VERSION 5.8 ;
BUSBITCHARS "[]" ;
DIVIDERCHAR "/" ;
UNITS
    DATABASE MICRONS 1000 ;
END UNITS

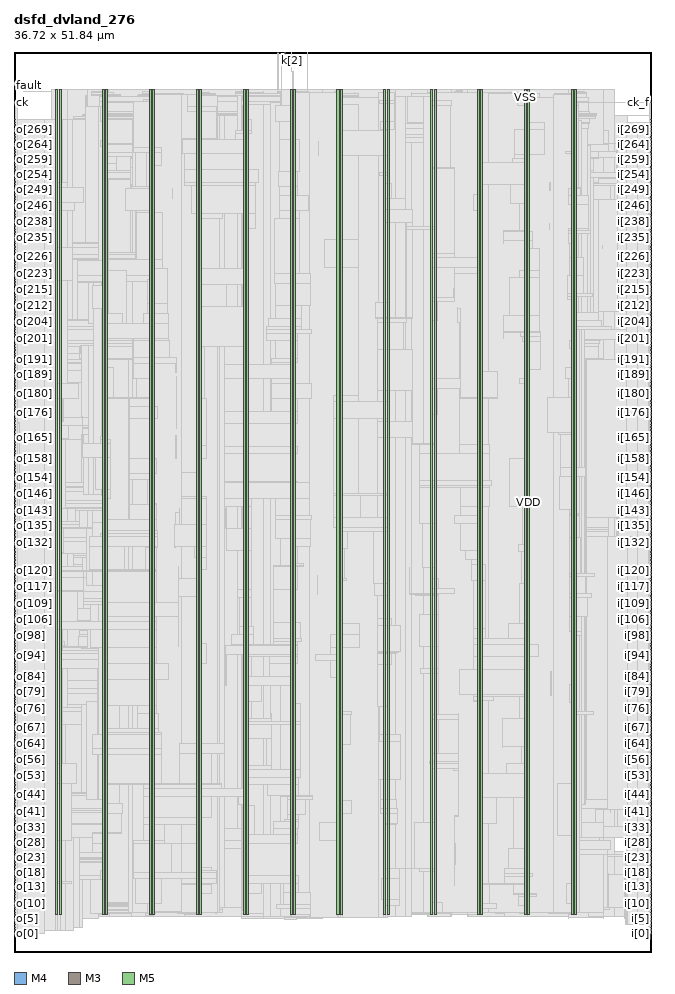
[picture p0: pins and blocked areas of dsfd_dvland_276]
MACRO dsfd_dvland_276
  FOREIGN dsfd_dvland_276 0 0 ;
  CLASS BLOCK ;
  SIZE 36.72 BY 51.84 ;
  PIN ck
    DIRECTION INPUT ;
    USE SIGNAL ;
    PORT
      LAYER M4 ;
        RECT  0 48.912 0.084 48.936 ;
    END
  END ck
  PIN ck_f
    DIRECTION INPUT ;
    USE SIGNAL ;
    PORT
      LAYER M4 ;
        RECT  36.636 48.912 36.72 48.936 ;
    END
  END ck_f
  PIN fault
    DIRECTION OUTPUT ;
    USE SIGNAL ;
    PORT
      LAYER M4 ;
        RECT  0 49.92 0.084 49.944 ;
    END
  END fault
  PIN i[0]
    DIRECTION INPUT ;
    USE SIGNAL ;
    PORT
      LAYER M4 ;
        RECT  36.636 1.056 36.72 1.08 ;
    END
  END i[0]
  PIN i[100]
    DIRECTION INPUT ;
    USE SIGNAL ;
    PORT
      LAYER M4 ;
        RECT  36.636 18.096 36.72 18.12 ;
    END
  END i[100]
  PIN i[101]
    DIRECTION INPUT ;
    USE SIGNAL ;
    PORT
      LAYER M4 ;
        RECT  36.636 18.288 36.72 18.312 ;
    END
  END i[101]
  PIN i[102]
    DIRECTION INPUT ;
    USE SIGNAL ;
    PORT
      LAYER M4 ;
        RECT  36.636 18.48 36.72 18.504 ;
    END
  END i[102]
  PIN i[103]
    DIRECTION INPUT ;
    USE SIGNAL ;
    PORT
      LAYER M4 ;
        RECT  36.636 18.624 36.72 18.648 ;
    END
  END i[103]
  PIN i[104]
    DIRECTION INPUT ;
    USE SIGNAL ;
    PORT
      LAYER M4 ;
        RECT  36.636 18.816 36.72 18.84 ;
    END
  END i[104]
  PIN i[105]
    DIRECTION INPUT ;
    USE SIGNAL ;
    PORT
      LAYER M4 ;
        RECT  36.636 18.96 36.72 18.984 ;
    END
  END i[105]
  PIN i[106]
    DIRECTION INPUT ;
    USE SIGNAL ;
    PORT
      LAYER M4 ;
        RECT  36.636 19.152 36.72 19.176 ;
    END
  END i[106]
  PIN i[107]
    DIRECTION INPUT ;
    USE SIGNAL ;
    PORT
      LAYER M4 ;
        RECT  36.636 19.296 36.72 19.32 ;
    END
  END i[107]
  PIN i[108]
    DIRECTION INPUT ;
    USE SIGNAL ;
    PORT
      LAYER M4 ;
        RECT  36.636 19.488 36.72 19.512 ;
    END
  END i[108]
  PIN i[109]
    DIRECTION INPUT ;
    USE SIGNAL ;
    PORT
      LAYER M4 ;
        RECT  36.636 19.632 36.72 19.656 ;
    END
  END i[109]
  PIN i[10]
    DIRECTION INPUT ;
    USE SIGNAL ;
    PORT
      LAYER M4 ;
        RECT  36.636 2.784 36.72 2.808 ;
    END
  END i[10]
  PIN i[110]
    DIRECTION INPUT ;
    USE SIGNAL ;
    PORT
      LAYER M4 ;
        RECT  36.636 19.824 36.72 19.848 ;
    END
  END i[110]
  PIN i[111]
    DIRECTION INPUT ;
    USE SIGNAL ;
    PORT
      LAYER M4 ;
        RECT  36.636 19.968 36.72 19.992 ;
    END
  END i[111]
  PIN i[112]
    DIRECTION INPUT ;
    USE SIGNAL ;
    PORT
      LAYER M4 ;
        RECT  36.636 20.16 36.72 20.184 ;
    END
  END i[112]
  PIN i[113]
    DIRECTION INPUT ;
    USE SIGNAL ;
    PORT
      LAYER M4 ;
        RECT  36.636 20.352 36.72 20.376 ;
    END
  END i[113]
  PIN i[114]
    DIRECTION INPUT ;
    USE SIGNAL ;
    PORT
      LAYER M4 ;
        RECT  36.636 20.496 36.72 20.52 ;
    END
  END i[114]
  PIN i[115]
    DIRECTION INPUT ;
    USE SIGNAL ;
    PORT
      LAYER M4 ;
        RECT  36.636 20.688 36.72 20.712 ;
    END
  END i[115]
  PIN i[116]
    DIRECTION INPUT ;
    USE SIGNAL ;
    PORT
      LAYER M4 ;
        RECT  36.636 20.832 36.72 20.856 ;
    END
  END i[116]
  PIN i[117]
    DIRECTION INPUT ;
    USE SIGNAL ;
    PORT
      LAYER M4 ;
        RECT  36.636 21.024 36.72 21.048 ;
    END
  END i[117]
  PIN i[118]
    DIRECTION INPUT ;
    USE SIGNAL ;
    PORT
      LAYER M4 ;
        RECT  36.636 21.168 36.72 21.192 ;
    END
  END i[118]
  PIN i[119]
    DIRECTION INPUT ;
    USE SIGNAL ;
    PORT
      LAYER M4 ;
        RECT  36.636 21.36 36.72 21.384 ;
    END
  END i[119]
  PIN i[11]
    DIRECTION INPUT ;
    USE SIGNAL ;
    PORT
      LAYER M4 ;
        RECT  36.636 2.928 36.72 2.952 ;
    END
  END i[11]
  PIN i[120]
    DIRECTION INPUT ;
    USE SIGNAL ;
    PORT
      LAYER M4 ;
        RECT  36.636 21.504 36.72 21.528 ;
    END
  END i[120]
  PIN i[121]
    DIRECTION INPUT ;
    USE SIGNAL ;
    PORT
      LAYER M4 ;
        RECT  36.636 21.696 36.72 21.72 ;
    END
  END i[121]
  PIN i[122]
    DIRECTION INPUT ;
    USE SIGNAL ;
    PORT
      LAYER M4 ;
        RECT  36.636 21.888 36.72 21.912 ;
    END
  END i[122]
  PIN i[123]
    DIRECTION INPUT ;
    USE SIGNAL ;
    PORT
      LAYER M4 ;
        RECT  36.636 22.032 36.72 22.056 ;
    END
  END i[123]
  PIN i[124]
    DIRECTION INPUT ;
    USE SIGNAL ;
    PORT
      LAYER M4 ;
        RECT  36.636 22.224 36.72 22.248 ;
    END
  END i[124]
  PIN i[125]
    DIRECTION INPUT ;
    USE SIGNAL ;
    PORT
      LAYER M4 ;
        RECT  36.636 22.368 36.72 22.392 ;
    END
  END i[125]
  PIN i[126]
    DIRECTION INPUT ;
    USE SIGNAL ;
    PORT
      LAYER M4 ;
        RECT  36.636 22.56 36.72 22.584 ;
    END
  END i[126]
  PIN i[127]
    DIRECTION INPUT ;
    USE SIGNAL ;
    PORT
      LAYER M4 ;
        RECT  36.636 22.704 36.72 22.728 ;
    END
  END i[127]
  PIN i[128]
    DIRECTION INPUT ;
    USE SIGNAL ;
    PORT
      LAYER M4 ;
        RECT  36.636 22.896 36.72 22.92 ;
    END
  END i[128]
  PIN i[129]
    DIRECTION INPUT ;
    USE SIGNAL ;
    PORT
      LAYER M4 ;
        RECT  36.636 23.04 36.72 23.064 ;
    END
  END i[129]
  PIN i[12]
    DIRECTION INPUT ;
    USE SIGNAL ;
    PORT
      LAYER M4 ;
        RECT  36.636 3.12 36.72 3.144 ;
    END
  END i[12]
  PIN i[130]
    DIRECTION INPUT ;
    USE SIGNAL ;
    PORT
      LAYER M4 ;
        RECT  36.636 23.232 36.72 23.256 ;
    END
  END i[130]
  PIN i[131]
    DIRECTION INPUT ;
    USE SIGNAL ;
    PORT
      LAYER M4 ;
        RECT  36.636 23.424 36.72 23.448 ;
    END
  END i[131]
  PIN i[132]
    DIRECTION INPUT ;
    USE SIGNAL ;
    PORT
      LAYER M4 ;
        RECT  36.636 23.568 36.72 23.592 ;
    END
  END i[132]
  PIN i[133]
    DIRECTION INPUT ;
    USE SIGNAL ;
    PORT
      LAYER M4 ;
        RECT  36.636 23.76 36.72 23.784 ;
    END
  END i[133]
  PIN i[134]
    DIRECTION INPUT ;
    USE SIGNAL ;
    PORT
      LAYER M4 ;
        RECT  36.636 23.904 36.72 23.928 ;
    END
  END i[134]
  PIN i[135]
    DIRECTION INPUT ;
    USE SIGNAL ;
    PORT
      LAYER M4 ;
        RECT  36.636 24.096 36.72 24.12 ;
    END
  END i[135]
  PIN i[136]
    DIRECTION INPUT ;
    USE SIGNAL ;
    PORT
      LAYER M4 ;
        RECT  36.636 24.24 36.72 24.264 ;
    END
  END i[136]
  PIN i[137]
    DIRECTION INPUT ;
    USE SIGNAL ;
    PORT
      LAYER M4 ;
        RECT  36.636 24.432 36.72 24.456 ;
    END
  END i[137]
  PIN i[138]
    DIRECTION INPUT ;
    USE SIGNAL ;
    PORT
      LAYER M4 ;
        RECT  36.636 24.576 36.72 24.6 ;
    END
  END i[138]
  PIN i[139]
    DIRECTION INPUT ;
    USE SIGNAL ;
    PORT
      LAYER M4 ;
        RECT  36.636 24.768 36.72 24.792 ;
    END
  END i[139]
  PIN i[13]
    DIRECTION INPUT ;
    USE SIGNAL ;
    PORT
      LAYER M4 ;
        RECT  36.636 3.312 36.72 3.336 ;
    END
  END i[13]
  PIN i[140]
    DIRECTION INPUT ;
    USE SIGNAL ;
    PORT
      LAYER M4 ;
        RECT  36.636 24.912 36.72 24.936 ;
    END
  END i[140]
  PIN i[141]
    DIRECTION INPUT ;
    USE SIGNAL ;
    PORT
      LAYER M4 ;
        RECT  36.636 25.104 36.72 25.128 ;
    END
  END i[141]
  PIN i[142]
    DIRECTION INPUT ;
    USE SIGNAL ;
    PORT
      LAYER M4 ;
        RECT  36.636 25.296 36.72 25.32 ;
    END
  END i[142]
  PIN i[143]
    DIRECTION INPUT ;
    USE SIGNAL ;
    PORT
      LAYER M4 ;
        RECT  36.636 25.44 36.72 25.464 ;
    END
  END i[143]
  PIN i[144]
    DIRECTION INPUT ;
    USE SIGNAL ;
    PORT
      LAYER M4 ;
        RECT  36.636 25.632 36.72 25.656 ;
    END
  END i[144]
  PIN i[145]
    DIRECTION INPUT ;
    USE SIGNAL ;
    PORT
      LAYER M4 ;
        RECT  36.636 25.776 36.72 25.8 ;
    END
  END i[145]
  PIN i[146]
    DIRECTION INPUT ;
    USE SIGNAL ;
    PORT
      LAYER M4 ;
        RECT  36.636 25.968 36.72 25.992 ;
    END
  END i[146]
  PIN i[147]
    DIRECTION INPUT ;
    USE SIGNAL ;
    PORT
      LAYER M4 ;
        RECT  36.636 26.112 36.72 26.136 ;
    END
  END i[147]
  PIN i[148]
    DIRECTION INPUT ;
    USE SIGNAL ;
    PORT
      LAYER M4 ;
        RECT  36.636 26.304 36.72 26.328 ;
    END
  END i[148]
  PIN i[149]
    DIRECTION INPUT ;
    USE SIGNAL ;
    PORT
      LAYER M4 ;
        RECT  36.636 26.448 36.72 26.472 ;
    END
  END i[149]
  PIN i[14]
    DIRECTION INPUT ;
    USE SIGNAL ;
    PORT
      LAYER M4 ;
        RECT  36.636 3.456 36.72 3.48 ;
    END
  END i[14]
  PIN i[150]
    DIRECTION INPUT ;
    USE SIGNAL ;
    PORT
      LAYER M4 ;
        RECT  36.636 26.64 36.72 26.664 ;
    END
  END i[150]
  PIN i[151]
    DIRECTION INPUT ;
    USE SIGNAL ;
    PORT
      LAYER M4 ;
        RECT  36.636 26.832 36.72 26.856 ;
    END
  END i[151]
  PIN i[152]
    DIRECTION INPUT ;
    USE SIGNAL ;
    PORT
      LAYER M4 ;
        RECT  36.636 26.976 36.72 27 ;
    END
  END i[152]
  PIN i[153]
    DIRECTION INPUT ;
    USE SIGNAL ;
    PORT
      LAYER M4 ;
        RECT  36.636 27.168 36.72 27.192 ;
    END
  END i[153]
  PIN i[154]
    DIRECTION INPUT ;
    USE SIGNAL ;
    PORT
      LAYER M4 ;
        RECT  36.636 27.312 36.72 27.336 ;
    END
  END i[154]
  PIN i[155]
    DIRECTION INPUT ;
    USE SIGNAL ;
    PORT
      LAYER M4 ;
        RECT  36.636 27.504 36.72 27.528 ;
    END
  END i[155]
  PIN i[156]
    DIRECTION INPUT ;
    USE SIGNAL ;
    PORT
      LAYER M4 ;
        RECT  36.636 27.648 36.72 27.672 ;
    END
  END i[156]
  PIN i[157]
    DIRECTION INPUT ;
    USE SIGNAL ;
    PORT
      LAYER M4 ;
        RECT  36.636 27.84 36.72 27.864 ;
    END
  END i[157]
  PIN i[158]
    DIRECTION INPUT ;
    USE SIGNAL ;
    PORT
      LAYER M4 ;
        RECT  36.636 27.984 36.72 28.008 ;
    END
  END i[158]
  PIN i[159]
    DIRECTION INPUT ;
    USE SIGNAL ;
    PORT
      LAYER M4 ;
        RECT  36.636 28.176 36.72 28.2 ;
    END
  END i[159]
  PIN i[15]
    DIRECTION INPUT ;
    USE SIGNAL ;
    PORT
      LAYER M4 ;
        RECT  36.636 3.648 36.72 3.672 ;
    END
  END i[15]
  PIN i[160]
    DIRECTION INPUT ;
    USE SIGNAL ;
    PORT
      LAYER M4 ;
        RECT  36.636 28.32 36.72 28.344 ;
    END
  END i[160]
  PIN i[161]
    DIRECTION INPUT ;
    USE SIGNAL ;
    PORT
      LAYER M4 ;
        RECT  36.636 28.512 36.72 28.536 ;
    END
  END i[161]
  PIN i[162]
    DIRECTION INPUT ;
    USE SIGNAL ;
    PORT
      LAYER M4 ;
        RECT  36.636 28.704 36.72 28.728 ;
    END
  END i[162]
  PIN i[163]
    DIRECTION INPUT ;
    USE SIGNAL ;
    PORT
      LAYER M4 ;
        RECT  36.636 28.848 36.72 28.872 ;
    END
  END i[163]
  PIN i[164]
    DIRECTION INPUT ;
    USE SIGNAL ;
    PORT
      LAYER M4 ;
        RECT  36.636 29.04 36.72 29.064 ;
    END
  END i[164]
  PIN i[165]
    DIRECTION INPUT ;
    USE SIGNAL ;
    PORT
      LAYER M4 ;
        RECT  36.636 29.184 36.72 29.208 ;
    END
  END i[165]
  PIN i[166]
    DIRECTION INPUT ;
    USE SIGNAL ;
    PORT
      LAYER M4 ;
        RECT  36.636 29.376 36.72 29.4 ;
    END
  END i[166]
  PIN i[167]
    DIRECTION INPUT ;
    USE SIGNAL ;
    PORT
      LAYER M4 ;
        RECT  36.636 29.52 36.72 29.544 ;
    END
  END i[167]
  PIN i[168]
    DIRECTION INPUT ;
    USE SIGNAL ;
    PORT
      LAYER M4 ;
        RECT  36.636 29.712 36.72 29.736 ;
    END
  END i[168]
  PIN i[169]
    DIRECTION INPUT ;
    USE SIGNAL ;
    PORT
      LAYER M4 ;
        RECT  36.636 29.856 36.72 29.88 ;
    END
  END i[169]
  PIN i[16]
    DIRECTION INPUT ;
    USE SIGNAL ;
    PORT
      LAYER M4 ;
        RECT  36.636 3.792 36.72 3.816 ;
    END
  END i[16]
  PIN i[170]
    DIRECTION INPUT ;
    USE SIGNAL ;
    PORT
      LAYER M4 ;
        RECT  36.636 30.048 36.72 30.072 ;
    END
  END i[170]
  PIN i[171]
    DIRECTION INPUT ;
    USE SIGNAL ;
    PORT
      LAYER M4 ;
        RECT  36.636 30.24 36.72 30.264 ;
    END
  END i[171]
  PIN i[172]
    DIRECTION INPUT ;
    USE SIGNAL ;
    PORT
      LAYER M4 ;
        RECT  36.636 30.384 36.72 30.408 ;
    END
  END i[172]
  PIN i[173]
    DIRECTION INPUT ;
    USE SIGNAL ;
    PORT
      LAYER M4 ;
        RECT  36.636 30.576 36.72 30.6 ;
    END
  END i[173]
  PIN i[174]
    DIRECTION INPUT ;
    USE SIGNAL ;
    PORT
      LAYER M4 ;
        RECT  36.636 30.72 36.72 30.744 ;
    END
  END i[174]
  PIN i[175]
    DIRECTION INPUT ;
    USE SIGNAL ;
    PORT
      LAYER M4 ;
        RECT  36.636 30.912 36.72 30.936 ;
    END
  END i[175]
  PIN i[176]
    DIRECTION INPUT ;
    USE SIGNAL ;
    PORT
      LAYER M4 ;
        RECT  36.636 31.056 36.72 31.08 ;
    END
  END i[176]
  PIN i[177]
    DIRECTION INPUT ;
    USE SIGNAL ;
    PORT
      LAYER M4 ;
        RECT  36.636 31.248 36.72 31.272 ;
    END
  END i[177]
  PIN i[178]
    DIRECTION INPUT ;
    USE SIGNAL ;
    PORT
      LAYER M4 ;
        RECT  36.636 31.392 36.72 31.416 ;
    END
  END i[178]
  PIN i[179]
    DIRECTION INPUT ;
    USE SIGNAL ;
    PORT
      LAYER M4 ;
        RECT  36.636 31.584 36.72 31.608 ;
    END
  END i[179]
  PIN i[17]
    DIRECTION INPUT ;
    USE SIGNAL ;
    PORT
      LAYER M4 ;
        RECT  36.636 3.984 36.72 4.008 ;
    END
  END i[17]
  PIN i[180]
    DIRECTION INPUT ;
    USE SIGNAL ;
    PORT
      LAYER M4 ;
        RECT  36.636 31.728 36.72 31.752 ;
    END
  END i[180]
  PIN i[181]
    DIRECTION INPUT ;
    USE SIGNAL ;
    PORT
      LAYER M4 ;
        RECT  36.636 31.92 36.72 31.944 ;
    END
  END i[181]
  PIN i[182]
    DIRECTION INPUT ;
    USE SIGNAL ;
    PORT
      LAYER M4 ;
        RECT  36.636 32.112 36.72 32.136 ;
    END
  END i[182]
  PIN i[183]
    DIRECTION INPUT ;
    USE SIGNAL ;
    PORT
      LAYER M4 ;
        RECT  36.636 32.256 36.72 32.28 ;
    END
  END i[183]
  PIN i[184]
    DIRECTION INPUT ;
    USE SIGNAL ;
    PORT
      LAYER M4 ;
        RECT  36.636 32.448 36.72 32.472 ;
    END
  END i[184]
  PIN i[185]
    DIRECTION INPUT ;
    USE SIGNAL ;
    PORT
      LAYER M4 ;
        RECT  36.636 32.592 36.72 32.616 ;
    END
  END i[185]
  PIN i[186]
    DIRECTION INPUT ;
    USE SIGNAL ;
    PORT
      LAYER M4 ;
        RECT  36.636 32.784 36.72 32.808 ;
    END
  END i[186]
  PIN i[187]
    DIRECTION INPUT ;
    USE SIGNAL ;
    PORT
      LAYER M4 ;
        RECT  36.636 32.928 36.72 32.952 ;
    END
  END i[187]
  PIN i[188]
    DIRECTION INPUT ;
    USE SIGNAL ;
    PORT
      LAYER M4 ;
        RECT  36.636 33.12 36.72 33.144 ;
    END
  END i[188]
  PIN i[189]
    DIRECTION INPUT ;
    USE SIGNAL ;
    PORT
      LAYER M4 ;
        RECT  36.636 33.264 36.72 33.288 ;
    END
  END i[189]
  PIN i[18]
    DIRECTION INPUT ;
    USE SIGNAL ;
    PORT
      LAYER M4 ;
        RECT  36.636 4.128 36.72 4.152 ;
    END
  END i[18]
  PIN i[190]
    DIRECTION INPUT ;
    USE SIGNAL ;
    PORT
      LAYER M4 ;
        RECT  36.636 33.456 36.72 33.48 ;
    END
  END i[190]
  PIN i[191]
    DIRECTION INPUT ;
    USE SIGNAL ;
    PORT
      LAYER M4 ;
        RECT  36.636 33.648 36.72 33.672 ;
    END
  END i[191]
  PIN i[192]
    DIRECTION INPUT ;
    USE SIGNAL ;
    PORT
      LAYER M4 ;
        RECT  36.636 33.792 36.72 33.816 ;
    END
  END i[192]
  PIN i[193]
    DIRECTION INPUT ;
    USE SIGNAL ;
    PORT
      LAYER M4 ;
        RECT  36.636 33.984 36.72 34.008 ;
    END
  END i[193]
  PIN i[194]
    DIRECTION INPUT ;
    USE SIGNAL ;
    PORT
      LAYER M4 ;
        RECT  36.636 34.128 36.72 34.152 ;
    END
  END i[194]
  PIN i[195]
    DIRECTION INPUT ;
    USE SIGNAL ;
    PORT
      LAYER M4 ;
        RECT  36.636 34.32 36.72 34.344 ;
    END
  END i[195]
  PIN i[196]
    DIRECTION INPUT ;
    USE SIGNAL ;
    PORT
      LAYER M4 ;
        RECT  36.636 34.464 36.72 34.488 ;
    END
  END i[196]
  PIN i[197]
    DIRECTION INPUT ;
    USE SIGNAL ;
    PORT
      LAYER M4 ;
        RECT  36.636 34.656 36.72 34.68 ;
    END
  END i[197]
  PIN i[198]
    DIRECTION INPUT ;
    USE SIGNAL ;
    PORT
      LAYER M4 ;
        RECT  36.636 34.8 36.72 34.824 ;
    END
  END i[198]
  PIN i[199]
    DIRECTION INPUT ;
    USE SIGNAL ;
    PORT
      LAYER M4 ;
        RECT  36.636 34.992 36.72 35.016 ;
    END
  END i[199]
  PIN i[19]
    DIRECTION INPUT ;
    USE SIGNAL ;
    PORT
      LAYER M4 ;
        RECT  36.636 4.32 36.72 4.344 ;
    END
  END i[19]
  PIN i[1]
    DIRECTION INPUT ;
    USE SIGNAL ;
    PORT
      LAYER M4 ;
        RECT  36.636 1.248 36.72 1.272 ;
    END
  END i[1]
  PIN i[200]
    DIRECTION INPUT ;
    USE SIGNAL ;
    PORT
      LAYER M4 ;
        RECT  36.636 35.184 36.72 35.208 ;
    END
  END i[200]
  PIN i[201]
    DIRECTION INPUT ;
    USE SIGNAL ;
    PORT
      LAYER M4 ;
        RECT  36.636 35.328 36.72 35.352 ;
    END
  END i[201]
  PIN i[202]
    DIRECTION INPUT ;
    USE SIGNAL ;
    PORT
      LAYER M4 ;
        RECT  36.636 35.52 36.72 35.544 ;
    END
  END i[202]
  PIN i[203]
    DIRECTION INPUT ;
    USE SIGNAL ;
    PORT
      LAYER M4 ;
        RECT  36.636 35.664 36.72 35.688 ;
    END
  END i[203]
  PIN i[204]
    DIRECTION INPUT ;
    USE SIGNAL ;
    PORT
      LAYER M4 ;
        RECT  36.636 35.856 36.72 35.88 ;
    END
  END i[204]
  PIN i[205]
    DIRECTION INPUT ;
    USE SIGNAL ;
    PORT
      LAYER M4 ;
        RECT  36.636 36 36.72 36.024 ;
    END
  END i[205]
  PIN i[206]
    DIRECTION INPUT ;
    USE SIGNAL ;
    PORT
      LAYER M4 ;
        RECT  36.636 36.192 36.72 36.216 ;
    END
  END i[206]
  PIN i[207]
    DIRECTION INPUT ;
    USE SIGNAL ;
    PORT
      LAYER M4 ;
        RECT  36.636 36.336 36.72 36.36 ;
    END
  END i[207]
  PIN i[208]
    DIRECTION INPUT ;
    USE SIGNAL ;
    PORT
      LAYER M4 ;
        RECT  36.636 36.528 36.72 36.552 ;
    END
  END i[208]
  PIN i[209]
    DIRECTION INPUT ;
    USE SIGNAL ;
    PORT
      LAYER M4 ;
        RECT  36.636 36.672 36.72 36.696 ;
    END
  END i[209]
  PIN i[20]
    DIRECTION INPUT ;
    USE SIGNAL ;
    PORT
      LAYER M4 ;
        RECT  36.636 4.464 36.72 4.488 ;
    END
  END i[20]
  PIN i[210]
    DIRECTION INPUT ;
    USE SIGNAL ;
    PORT
      LAYER M4 ;
        RECT  36.636 36.864 36.72 36.888 ;
    END
  END i[210]
  PIN i[211]
    DIRECTION INPUT ;
    USE SIGNAL ;
    PORT
      LAYER M4 ;
        RECT  36.636 37.056 36.72 37.08 ;
    END
  END i[211]
  PIN i[212]
    DIRECTION INPUT ;
    USE SIGNAL ;
    PORT
      LAYER M4 ;
        RECT  36.636 37.2 36.72 37.224 ;
    END
  END i[212]
  PIN i[213]
    DIRECTION INPUT ;
    USE SIGNAL ;
    PORT
      LAYER M4 ;
        RECT  36.636 37.392 36.72 37.416 ;
    END
  END i[213]
  PIN i[214]
    DIRECTION INPUT ;
    USE SIGNAL ;
    PORT
      LAYER M4 ;
        RECT  36.636 37.536 36.72 37.56 ;
    END
  END i[214]
  PIN i[215]
    DIRECTION INPUT ;
    USE SIGNAL ;
    PORT
      LAYER M4 ;
        RECT  36.636 37.728 36.72 37.752 ;
    END
  END i[215]
  PIN i[216]
    DIRECTION INPUT ;
    USE SIGNAL ;
    PORT
      LAYER M4 ;
        RECT  36.636 37.872 36.72 37.896 ;
    END
  END i[216]
  PIN i[217]
    DIRECTION INPUT ;
    USE SIGNAL ;
    PORT
      LAYER M4 ;
        RECT  36.636 38.064 36.72 38.088 ;
    END
  END i[217]
  PIN i[218]
    DIRECTION INPUT ;
    USE SIGNAL ;
    PORT
      LAYER M4 ;
        RECT  36.636 38.208 36.72 38.232 ;
    END
  END i[218]
  PIN i[219]
    DIRECTION INPUT ;
    USE SIGNAL ;
    PORT
      LAYER M4 ;
        RECT  36.636 38.4 36.72 38.424 ;
    END
  END i[219]
  PIN i[21]
    DIRECTION INPUT ;
    USE SIGNAL ;
    PORT
      LAYER M4 ;
        RECT  36.636 4.656 36.72 4.68 ;
    END
  END i[21]
  PIN i[220]
    DIRECTION INPUT ;
    USE SIGNAL ;
    PORT
      LAYER M4 ;
        RECT  36.636 38.592 36.72 38.616 ;
    END
  END i[220]
  PIN i[221]
    DIRECTION INPUT ;
    USE SIGNAL ;
    PORT
      LAYER M4 ;
        RECT  36.636 38.736 36.72 38.76 ;
    END
  END i[221]
  PIN i[222]
    DIRECTION INPUT ;
    USE SIGNAL ;
    PORT
      LAYER M4 ;
        RECT  36.636 38.928 36.72 38.952 ;
    END
  END i[222]
  PIN i[223]
    DIRECTION INPUT ;
    USE SIGNAL ;
    PORT
      LAYER M4 ;
        RECT  36.636 39.072 36.72 39.096 ;
    END
  END i[223]
  PIN i[224]
    DIRECTION INPUT ;
    USE SIGNAL ;
    PORT
      LAYER M4 ;
        RECT  36.636 39.264 36.72 39.288 ;
    END
  END i[224]
  PIN i[225]
    DIRECTION INPUT ;
    USE SIGNAL ;
    PORT
      LAYER M4 ;
        RECT  36.636 39.408 36.72 39.432 ;
    END
  END i[225]
  PIN i[226]
    DIRECTION INPUT ;
    USE SIGNAL ;
    PORT
      LAYER M4 ;
        RECT  36.636 39.6 36.72 39.624 ;
    END
  END i[226]
  PIN i[227]
    DIRECTION INPUT ;
    USE SIGNAL ;
    PORT
      LAYER M4 ;
        RECT  36.636 39.744 36.72 39.768 ;
    END
  END i[227]
  PIN i[228]
    DIRECTION INPUT ;
    USE SIGNAL ;
    PORT
      LAYER M4 ;
        RECT  36.636 39.936 36.72 39.96 ;
    END
  END i[228]
  PIN i[229]
    DIRECTION INPUT ;
    USE SIGNAL ;
    PORT
      LAYER M4 ;
        RECT  36.636 40.08 36.72 40.104 ;
    END
  END i[229]
  PIN i[22]
    DIRECTION INPUT ;
    USE SIGNAL ;
    PORT
      LAYER M4 ;
        RECT  36.636 4.8 36.72 4.824 ;
    END
  END i[22]
  PIN i[230]
    DIRECTION INPUT ;
    USE SIGNAL ;
    PORT
      LAYER M4 ;
        RECT  36.636 40.272 36.72 40.296 ;
    END
  END i[230]
  PIN i[231]
    DIRECTION INPUT ;
    USE SIGNAL ;
    PORT
      LAYER M4 ;
        RECT  36.636 40.464 36.72 40.488 ;
    END
  END i[231]
  PIN i[232]
    DIRECTION INPUT ;
    USE SIGNAL ;
    PORT
      LAYER M4 ;
        RECT  36.636 40.608 36.72 40.632 ;
    END
  END i[232]
  PIN i[233]
    DIRECTION INPUT ;
    USE SIGNAL ;
    PORT
      LAYER M4 ;
        RECT  36.636 40.8 36.72 40.824 ;
    END
  END i[233]
  PIN i[234]
    DIRECTION INPUT ;
    USE SIGNAL ;
    PORT
      LAYER M4 ;
        RECT  36.636 40.944 36.72 40.968 ;
    END
  END i[234]
  PIN i[235]
    DIRECTION INPUT ;
    USE SIGNAL ;
    PORT
      LAYER M4 ;
        RECT  36.636 41.136 36.72 41.16 ;
    END
  END i[235]
  PIN i[236]
    DIRECTION INPUT ;
    USE SIGNAL ;
    PORT
      LAYER M4 ;
        RECT  36.636 41.28 36.72 41.304 ;
    END
  END i[236]
  PIN i[237]
    DIRECTION INPUT ;
    USE SIGNAL ;
    PORT
      LAYER M4 ;
        RECT  36.636 41.472 36.72 41.496 ;
    END
  END i[237]
  PIN i[238]
    DIRECTION INPUT ;
    USE SIGNAL ;
    PORT
      LAYER M4 ;
        RECT  36.636 41.616 36.72 41.64 ;
    END
  END i[238]
  PIN i[239]
    DIRECTION INPUT ;
    USE SIGNAL ;
    PORT
      LAYER M4 ;
        RECT  36.636 41.808 36.72 41.832 ;
    END
  END i[239]
  PIN i[23]
    DIRECTION INPUT ;
    USE SIGNAL ;
    PORT
      LAYER M4 ;
        RECT  36.636 4.992 36.72 5.016 ;
    END
  END i[23]
  PIN i[240]
    DIRECTION INPUT ;
    USE SIGNAL ;
    PORT
      LAYER M4 ;
        RECT  36.636 42 36.72 42.024 ;
    END
  END i[240]
  PIN i[241]
    DIRECTION INPUT ;
    USE SIGNAL ;
    PORT
      LAYER M4 ;
        RECT  36.636 42.144 36.72 42.168 ;
    END
  END i[241]
  PIN i[242]
    DIRECTION INPUT ;
    USE SIGNAL ;
    PORT
      LAYER M4 ;
        RECT  36.636 42.336 36.72 42.36 ;
    END
  END i[242]
  PIN i[243]
    DIRECTION INPUT ;
    USE SIGNAL ;
    PORT
      LAYER M4 ;
        RECT  36.636 42.48 36.72 42.504 ;
    END
  END i[243]
  PIN i[244]
    DIRECTION INPUT ;
    USE SIGNAL ;
    PORT
      LAYER M4 ;
        RECT  36.636 42.672 36.72 42.696 ;
    END
  END i[244]
  PIN i[245]
    DIRECTION INPUT ;
    USE SIGNAL ;
    PORT
      LAYER M4 ;
        RECT  36.636 42.816 36.72 42.84 ;
    END
  END i[245]
  PIN i[246]
    DIRECTION INPUT ;
    USE SIGNAL ;
    PORT
      LAYER M4 ;
        RECT  36.636 43.008 36.72 43.032 ;
    END
  END i[246]
  PIN i[247]
    DIRECTION INPUT ;
    USE SIGNAL ;
    PORT
      LAYER M4 ;
        RECT  36.636 43.152 36.72 43.176 ;
    END
  END i[247]
  PIN i[248]
    DIRECTION INPUT ;
    USE SIGNAL ;
    PORT
      LAYER M4 ;
        RECT  36.636 43.344 36.72 43.368 ;
    END
  END i[248]
  PIN i[249]
    DIRECTION INPUT ;
    USE SIGNAL ;
    PORT
      LAYER M4 ;
        RECT  36.636 43.488 36.72 43.512 ;
    END
  END i[249]
  PIN i[24]
    DIRECTION INPUT ;
    USE SIGNAL ;
    PORT
      LAYER M4 ;
        RECT  36.636 5.184 36.72 5.208 ;
    END
  END i[24]
  PIN i[250]
    DIRECTION INPUT ;
    USE SIGNAL ;
    PORT
      LAYER M4 ;
        RECT  36.636 43.68 36.72 43.704 ;
    END
  END i[250]
  PIN i[251]
    DIRECTION INPUT ;
    USE SIGNAL ;
    PORT
      LAYER M4 ;
        RECT  36.636 43.872 36.72 43.896 ;
    END
  END i[251]
  PIN i[252]
    DIRECTION INPUT ;
    USE SIGNAL ;
    PORT
      LAYER M4 ;
        RECT  36.636 44.016 36.72 44.04 ;
    END
  END i[252]
  PIN i[253]
    DIRECTION INPUT ;
    USE SIGNAL ;
    PORT
      LAYER M4 ;
        RECT  36.636 44.208 36.72 44.232 ;
    END
  END i[253]
  PIN i[254]
    DIRECTION INPUT ;
    USE SIGNAL ;
    PORT
      LAYER M4 ;
        RECT  36.636 44.352 36.72 44.376 ;
    END
  END i[254]
  PIN i[255]
    DIRECTION INPUT ;
    USE SIGNAL ;
    PORT
      LAYER M4 ;
        RECT  36.636 44.544 36.72 44.568 ;
    END
  END i[255]
  PIN i[256]
    DIRECTION INPUT ;
    USE SIGNAL ;
    PORT
      LAYER M4 ;
        RECT  36.636 44.688 36.72 44.712 ;
    END
  END i[256]
  PIN i[257]
    DIRECTION INPUT ;
    USE SIGNAL ;
    PORT
      LAYER M4 ;
        RECT  36.636 44.88 36.72 44.904 ;
    END
  END i[257]
  PIN i[258]
    DIRECTION INPUT ;
    USE SIGNAL ;
    PORT
      LAYER M4 ;
        RECT  36.636 45.024 36.72 45.048 ;
    END
  END i[258]
  PIN i[259]
    DIRECTION INPUT ;
    USE SIGNAL ;
    PORT
      LAYER M4 ;
        RECT  36.636 45.216 36.72 45.24 ;
    END
  END i[259]
  PIN i[25]
    DIRECTION INPUT ;
    USE SIGNAL ;
    PORT
      LAYER M4 ;
        RECT  36.636 5.328 36.72 5.352 ;
    END
  END i[25]
  PIN i[260]
    DIRECTION INPUT ;
    USE SIGNAL ;
    PORT
      LAYER M4 ;
        RECT  36.636 45.408 36.72 45.432 ;
    END
  END i[260]
  PIN i[261]
    DIRECTION INPUT ;
    USE SIGNAL ;
    PORT
      LAYER M4 ;
        RECT  36.636 45.552 36.72 45.576 ;
    END
  END i[261]
  PIN i[262]
    DIRECTION INPUT ;
    USE SIGNAL ;
    PORT
      LAYER M4 ;
        RECT  36.636 45.744 36.72 45.768 ;
    END
  END i[262]
  PIN i[263]
    DIRECTION INPUT ;
    USE SIGNAL ;
    PORT
      LAYER M4 ;
        RECT  36.636 45.888 36.72 45.912 ;
    END
  END i[263]
  PIN i[264]
    DIRECTION INPUT ;
    USE SIGNAL ;
    PORT
      LAYER M4 ;
        RECT  36.636 46.08 36.72 46.104 ;
    END
  END i[264]
  PIN i[265]
    DIRECTION INPUT ;
    USE SIGNAL ;
    PORT
      LAYER M4 ;
        RECT  36.636 46.224 36.72 46.248 ;
    END
  END i[265]
  PIN i[266]
    DIRECTION INPUT ;
    USE SIGNAL ;
    PORT
      LAYER M4 ;
        RECT  36.636 46.416 36.72 46.44 ;
    END
  END i[266]
  PIN i[267]
    DIRECTION INPUT ;
    USE SIGNAL ;
    PORT
      LAYER M4 ;
        RECT  36.636 46.56 36.72 46.584 ;
    END
  END i[267]
  PIN i[268]
    DIRECTION INPUT ;
    USE SIGNAL ;
    PORT
      LAYER M4 ;
        RECT  36.636 46.752 36.72 46.776 ;
    END
  END i[268]
  PIN i[269]
    DIRECTION INPUT ;
    USE SIGNAL ;
    PORT
      LAYER M4 ;
        RECT  36.636 46.944 36.72 46.968 ;
    END
  END i[269]
  PIN i[26]
    DIRECTION INPUT ;
    USE SIGNAL ;
    PORT
      LAYER M4 ;
        RECT  36.636 5.52 36.72 5.544 ;
    END
  END i[26]
  PIN i[270]
    DIRECTION INPUT ;
    USE SIGNAL ;
    PORT
      LAYER M4 ;
        RECT  36.636 47.088 36.72 47.112 ;
    END
  END i[270]
  PIN i[271]
    DIRECTION INPUT ;
    USE SIGNAL ;
    PORT
      LAYER M4 ;
        RECT  36.636 47.28 36.72 47.304 ;
    END
  END i[271]
  PIN i[272]
    DIRECTION INPUT ;
    USE SIGNAL ;
    PORT
      LAYER M4 ;
        RECT  36.636 47.424 36.72 47.448 ;
    END
  END i[272]
  PIN i[273]
    DIRECTION INPUT ;
    USE SIGNAL ;
    PORT
      LAYER M4 ;
        RECT  36.636 47.616 36.72 47.64 ;
    END
  END i[273]
  PIN i[274]
    DIRECTION INPUT ;
    USE SIGNAL ;
    PORT
      LAYER M4 ;
        RECT  36.636 47.76 36.72 47.784 ;
    END
  END i[274]
  PIN i[275]
    DIRECTION INPUT ;
    USE SIGNAL ;
    PORT
      LAYER M4 ;
        RECT  36.636 47.952 36.72 47.976 ;
    END
  END i[275]
  PIN i[27]
    DIRECTION INPUT ;
    USE SIGNAL ;
    PORT
      LAYER M4 ;
        RECT  36.636 5.664 36.72 5.688 ;
    END
  END i[27]
  PIN i[28]
    DIRECTION INPUT ;
    USE SIGNAL ;
    PORT
      LAYER M4 ;
        RECT  36.636 5.856 36.72 5.88 ;
    END
  END i[28]
  PIN i[29]
    DIRECTION INPUT ;
    USE SIGNAL ;
    PORT
      LAYER M4 ;
        RECT  36.636 6 36.72 6.024 ;
    END
  END i[29]
  PIN i[2]
    DIRECTION INPUT ;
    USE SIGNAL ;
    PORT
      LAYER M4 ;
        RECT  36.636 1.392 36.72 1.416 ;
    END
  END i[2]
  PIN i[30]
    DIRECTION INPUT ;
    USE SIGNAL ;
    PORT
      LAYER M4 ;
        RECT  36.636 6.192 36.72 6.216 ;
    END
  END i[30]
  PIN i[31]
    DIRECTION INPUT ;
    USE SIGNAL ;
    PORT
      LAYER M4 ;
        RECT  36.636 6.336 36.72 6.36 ;
    END
  END i[31]
  PIN i[32]
    DIRECTION INPUT ;
    USE SIGNAL ;
    PORT
      LAYER M4 ;
        RECT  36.636 6.528 36.72 6.552 ;
    END
  END i[32]
  PIN i[33]
    DIRECTION INPUT ;
    USE SIGNAL ;
    PORT
      LAYER M4 ;
        RECT  36.636 6.72 36.72 6.744 ;
    END
  END i[33]
  PIN i[34]
    DIRECTION INPUT ;
    USE SIGNAL ;
    PORT
      LAYER M4 ;
        RECT  36.636 6.864 36.72 6.888 ;
    END
  END i[34]
  PIN i[35]
    DIRECTION INPUT ;
    USE SIGNAL ;
    PORT
      LAYER M4 ;
        RECT  36.636 7.056 36.72 7.08 ;
    END
  END i[35]
  PIN i[36]
    DIRECTION INPUT ;
    USE SIGNAL ;
    PORT
      LAYER M4 ;
        RECT  36.636 7.2 36.72 7.224 ;
    END
  END i[36]
  PIN i[37]
    DIRECTION INPUT ;
    USE SIGNAL ;
    PORT
      LAYER M4 ;
        RECT  36.636 7.392 36.72 7.416 ;
    END
  END i[37]
  PIN i[38]
    DIRECTION INPUT ;
    USE SIGNAL ;
    PORT
      LAYER M4 ;
        RECT  36.636 7.536 36.72 7.56 ;
    END
  END i[38]
  PIN i[39]
    DIRECTION INPUT ;
    USE SIGNAL ;
    PORT
      LAYER M4 ;
        RECT  36.636 7.728 36.72 7.752 ;
    END
  END i[39]
  PIN i[3]
    DIRECTION INPUT ;
    USE SIGNAL ;
    PORT
      LAYER M4 ;
        RECT  36.636 1.584 36.72 1.608 ;
    END
  END i[3]
  PIN i[40]
    DIRECTION INPUT ;
    USE SIGNAL ;
    PORT
      LAYER M4 ;
        RECT  36.636 7.872 36.72 7.896 ;
    END
  END i[40]
  PIN i[41]
    DIRECTION INPUT ;
    USE SIGNAL ;
    PORT
      LAYER M4 ;
        RECT  36.636 8.064 36.72 8.088 ;
    END
  END i[41]
  PIN i[42]
    DIRECTION INPUT ;
    USE SIGNAL ;
    PORT
      LAYER M4 ;
        RECT  36.636 8.208 36.72 8.232 ;
    END
  END i[42]
  PIN i[43]
    DIRECTION INPUT ;
    USE SIGNAL ;
    PORT
      LAYER M4 ;
        RECT  36.636 8.4 36.72 8.424 ;
    END
  END i[43]
  PIN i[44]
    DIRECTION INPUT ;
    USE SIGNAL ;
    PORT
      LAYER M4 ;
        RECT  36.636 8.592 36.72 8.616 ;
    END
  END i[44]
  PIN i[45]
    DIRECTION INPUT ;
    USE SIGNAL ;
    PORT
      LAYER M4 ;
        RECT  36.636 8.736 36.72 8.76 ;
    END
  END i[45]
  PIN i[46]
    DIRECTION INPUT ;
    USE SIGNAL ;
    PORT
      LAYER M4 ;
        RECT  36.636 8.928 36.72 8.952 ;
    END
  END i[46]
  PIN i[47]
    DIRECTION INPUT ;
    USE SIGNAL ;
    PORT
      LAYER M4 ;
        RECT  36.636 9.072 36.72 9.096 ;
    END
  END i[47]
  PIN i[48]
    DIRECTION INPUT ;
    USE SIGNAL ;
    PORT
      LAYER M4 ;
        RECT  36.636 9.264 36.72 9.288 ;
    END
  END i[48]
  PIN i[49]
    DIRECTION INPUT ;
    USE SIGNAL ;
    PORT
      LAYER M4 ;
        RECT  36.636 9.408 36.72 9.432 ;
    END
  END i[49]
  PIN i[4]
    DIRECTION INPUT ;
    USE SIGNAL ;
    PORT
      LAYER M4 ;
        RECT  36.636 1.776 36.72 1.8 ;
    END
  END i[4]
  PIN i[50]
    DIRECTION INPUT ;
    USE SIGNAL ;
    PORT
      LAYER M4 ;
        RECT  36.636 9.6 36.72 9.624 ;
    END
  END i[50]
  PIN i[51]
    DIRECTION INPUT ;
    USE SIGNAL ;
    PORT
      LAYER M4 ;
        RECT  36.636 9.744 36.72 9.768 ;
    END
  END i[51]
  PIN i[52]
    DIRECTION INPUT ;
    USE SIGNAL ;
    PORT
      LAYER M4 ;
        RECT  36.636 9.936 36.72 9.96 ;
    END
  END i[52]
  PIN i[53]
    DIRECTION INPUT ;
    USE SIGNAL ;
    PORT
      LAYER M4 ;
        RECT  36.636 10.128 36.72 10.152 ;
    END
  END i[53]
  PIN i[54]
    DIRECTION INPUT ;
    USE SIGNAL ;
    PORT
      LAYER M4 ;
        RECT  36.636 10.272 36.72 10.296 ;
    END
  END i[54]
  PIN i[55]
    DIRECTION INPUT ;
    USE SIGNAL ;
    PORT
      LAYER M4 ;
        RECT  36.636 10.464 36.72 10.488 ;
    END
  END i[55]
  PIN i[56]
    DIRECTION INPUT ;
    USE SIGNAL ;
    PORT
      LAYER M4 ;
        RECT  36.636 10.608 36.72 10.632 ;
    END
  END i[56]
  PIN i[57]
    DIRECTION INPUT ;
    USE SIGNAL ;
    PORT
      LAYER M4 ;
        RECT  36.636 10.8 36.72 10.824 ;
    END
  END i[57]
  PIN i[58]
    DIRECTION INPUT ;
    USE SIGNAL ;
    PORT
      LAYER M4 ;
        RECT  36.636 10.944 36.72 10.968 ;
    END
  END i[58]
  PIN i[59]
    DIRECTION INPUT ;
    USE SIGNAL ;
    PORT
      LAYER M4 ;
        RECT  36.636 11.136 36.72 11.16 ;
    END
  END i[59]
  PIN i[5]
    DIRECTION INPUT ;
    USE SIGNAL ;
    PORT
      LAYER M4 ;
        RECT  36.636 1.92 36.72 1.944 ;
    END
  END i[5]
  PIN i[60]
    DIRECTION INPUT ;
    USE SIGNAL ;
    PORT
      LAYER M4 ;
        RECT  36.636 11.28 36.72 11.304 ;
    END
  END i[60]
  PIN i[61]
    DIRECTION INPUT ;
    USE SIGNAL ;
    PORT
      LAYER M4 ;
        RECT  36.636 11.472 36.72 11.496 ;
    END
  END i[61]
  PIN i[62]
    DIRECTION INPUT ;
    USE SIGNAL ;
    PORT
      LAYER M4 ;
        RECT  36.636 11.664 36.72 11.688 ;
    END
  END i[62]
  PIN i[63]
    DIRECTION INPUT ;
    USE SIGNAL ;
    PORT
      LAYER M4 ;
        RECT  36.636 11.808 36.72 11.832 ;
    END
  END i[63]
  PIN i[64]
    DIRECTION INPUT ;
    USE SIGNAL ;
    PORT
      LAYER M4 ;
        RECT  36.636 12 36.72 12.024 ;
    END
  END i[64]
  PIN i[65]
    DIRECTION INPUT ;
    USE SIGNAL ;
    PORT
      LAYER M4 ;
        RECT  36.636 12.144 36.72 12.168 ;
    END
  END i[65]
  PIN i[66]
    DIRECTION INPUT ;
    USE SIGNAL ;
    PORT
      LAYER M4 ;
        RECT  36.636 12.336 36.72 12.36 ;
    END
  END i[66]
  PIN i[67]
    DIRECTION INPUT ;
    USE SIGNAL ;
    PORT
      LAYER M4 ;
        RECT  36.636 12.48 36.72 12.504 ;
    END
  END i[67]
  PIN i[68]
    DIRECTION INPUT ;
    USE SIGNAL ;
    PORT
      LAYER M4 ;
        RECT  36.636 12.672 36.72 12.696 ;
    END
  END i[68]
  PIN i[69]
    DIRECTION INPUT ;
    USE SIGNAL ;
    PORT
      LAYER M4 ;
        RECT  36.636 12.816 36.72 12.84 ;
    END
  END i[69]
  PIN i[6]
    DIRECTION INPUT ;
    USE SIGNAL ;
    PORT
      LAYER M4 ;
        RECT  36.636 2.112 36.72 2.136 ;
    END
  END i[6]
  PIN i[70]
    DIRECTION INPUT ;
    USE SIGNAL ;
    PORT
      LAYER M4 ;
        RECT  36.636 13.008 36.72 13.032 ;
    END
  END i[70]
  PIN i[71]
    DIRECTION INPUT ;
    USE SIGNAL ;
    PORT
      LAYER M4 ;
        RECT  36.636 13.152 36.72 13.176 ;
    END
  END i[71]
  PIN i[72]
    DIRECTION INPUT ;
    USE SIGNAL ;
    PORT
      LAYER M4 ;
        RECT  36.636 13.344 36.72 13.368 ;
    END
  END i[72]
  PIN i[73]
    DIRECTION INPUT ;
    USE SIGNAL ;
    PORT
      LAYER M4 ;
        RECT  36.636 13.536 36.72 13.56 ;
    END
  END i[73]
  PIN i[74]
    DIRECTION INPUT ;
    USE SIGNAL ;
    PORT
      LAYER M4 ;
        RECT  36.636 13.68 36.72 13.704 ;
    END
  END i[74]
  PIN i[75]
    DIRECTION INPUT ;
    USE SIGNAL ;
    PORT
      LAYER M4 ;
        RECT  36.636 13.872 36.72 13.896 ;
    END
  END i[75]
  PIN i[76]
    DIRECTION INPUT ;
    USE SIGNAL ;
    PORT
      LAYER M4 ;
        RECT  36.636 14.016 36.72 14.04 ;
    END
  END i[76]
  PIN i[77]
    DIRECTION INPUT ;
    USE SIGNAL ;
    PORT
      LAYER M4 ;
        RECT  36.636 14.208 36.72 14.232 ;
    END
  END i[77]
  PIN i[78]
    DIRECTION INPUT ;
    USE SIGNAL ;
    PORT
      LAYER M4 ;
        RECT  36.636 14.352 36.72 14.376 ;
    END
  END i[78]
  PIN i[79]
    DIRECTION INPUT ;
    USE SIGNAL ;
    PORT
      LAYER M4 ;
        RECT  36.636 14.544 36.72 14.568 ;
    END
  END i[79]
  PIN i[7]
    DIRECTION INPUT ;
    USE SIGNAL ;
    PORT
      LAYER M4 ;
        RECT  36.636 2.256 36.72 2.28 ;
    END
  END i[7]
  PIN i[80]
    DIRECTION INPUT ;
    USE SIGNAL ;
    PORT
      LAYER M4 ;
        RECT  36.636 14.688 36.72 14.712 ;
    END
  END i[80]
  PIN i[81]
    DIRECTION INPUT ;
    USE SIGNAL ;
    PORT
      LAYER M4 ;
        RECT  36.636 14.88 36.72 14.904 ;
    END
  END i[81]
  PIN i[82]
    DIRECTION INPUT ;
    USE SIGNAL ;
    PORT
      LAYER M4 ;
        RECT  36.636 15.072 36.72 15.096 ;
    END
  END i[82]
  PIN i[83]
    DIRECTION INPUT ;
    USE SIGNAL ;
    PORT
      LAYER M4 ;
        RECT  36.636 15.216 36.72 15.24 ;
    END
  END i[83]
  PIN i[84]
    DIRECTION INPUT ;
    USE SIGNAL ;
    PORT
      LAYER M4 ;
        RECT  36.636 15.408 36.72 15.432 ;
    END
  END i[84]
  PIN i[85]
    DIRECTION INPUT ;
    USE SIGNAL ;
    PORT
      LAYER M4 ;
        RECT  36.636 15.552 36.72 15.576 ;
    END
  END i[85]
  PIN i[86]
    DIRECTION INPUT ;
    USE SIGNAL ;
    PORT
      LAYER M4 ;
        RECT  36.636 15.744 36.72 15.768 ;
    END
  END i[86]
  PIN i[87]
    DIRECTION INPUT ;
    USE SIGNAL ;
    PORT
      LAYER M4 ;
        RECT  36.636 15.888 36.72 15.912 ;
    END
  END i[87]
  PIN i[88]
    DIRECTION INPUT ;
    USE SIGNAL ;
    PORT
      LAYER M4 ;
        RECT  36.636 16.08 36.72 16.104 ;
    END
  END i[88]
  PIN i[89]
    DIRECTION INPUT ;
    USE SIGNAL ;
    PORT
      LAYER M4 ;
        RECT  36.636 16.224 36.72 16.248 ;
    END
  END i[89]
  PIN i[8]
    DIRECTION INPUT ;
    USE SIGNAL ;
    PORT
      LAYER M4 ;
        RECT  36.636 2.448 36.72 2.472 ;
    END
  END i[8]
  PIN i[90]
    DIRECTION INPUT ;
    USE SIGNAL ;
    PORT
      LAYER M4 ;
        RECT  36.636 16.416 36.72 16.44 ;
    END
  END i[90]
  PIN i[91]
    DIRECTION INPUT ;
    USE SIGNAL ;
    PORT
      LAYER M4 ;
        RECT  36.636 16.56 36.72 16.584 ;
    END
  END i[91]
  PIN i[92]
    DIRECTION INPUT ;
    USE SIGNAL ;
    PORT
      LAYER M4 ;
        RECT  36.636 16.752 36.72 16.776 ;
    END
  END i[92]
  PIN i[93]
    DIRECTION INPUT ;
    USE SIGNAL ;
    PORT
      LAYER M4 ;
        RECT  36.636 16.944 36.72 16.968 ;
    END
  END i[93]
  PIN i[94]
    DIRECTION INPUT ;
    USE SIGNAL ;
    PORT
      LAYER M4 ;
        RECT  36.636 17.088 36.72 17.112 ;
    END
  END i[94]
  PIN i[95]
    DIRECTION INPUT ;
    USE SIGNAL ;
    PORT
      LAYER M4 ;
        RECT  36.636 17.28 36.72 17.304 ;
    END
  END i[95]
  PIN i[96]
    DIRECTION INPUT ;
    USE SIGNAL ;
    PORT
      LAYER M4 ;
        RECT  36.636 17.424 36.72 17.448 ;
    END
  END i[96]
  PIN i[97]
    DIRECTION INPUT ;
    USE SIGNAL ;
    PORT
      LAYER M4 ;
        RECT  36.636 17.616 36.72 17.64 ;
    END
  END i[97]
  PIN i[98]
    DIRECTION INPUT ;
    USE SIGNAL ;
    PORT
      LAYER M4 ;
        RECT  36.636 17.76 36.72 17.784 ;
    END
  END i[98]
  PIN i[99]
    DIRECTION INPUT ;
    USE SIGNAL ;
    PORT
      LAYER M4 ;
        RECT  36.636 17.952 36.72 17.976 ;
    END
  END i[99]
  PIN i[9]
    DIRECTION INPUT ;
    USE SIGNAL ;
    PORT
      LAYER M4 ;
        RECT  36.636 2.592 36.72 2.616 ;
    END
  END i[9]
  PIN k[0]
    DIRECTION INPUT ;
    USE SIGNAL ;
    PORT
      LAYER M3 ;
        RECT  15.192 51.802 15.21 51.84 ;
    END
  END k[0]
  PIN k[1]
    DIRECTION INPUT ;
    USE SIGNAL ;
    PORT
      LAYER M5 ;
        RECT  15.6 51.756 15.624 51.84 ;
    END
  END k[1]
  PIN k[2]
    DIRECTION INPUT ;
    USE SIGNAL ;
    PORT
      LAYER M3 ;
        RECT  15.984 51.802 16.002 51.84 ;
    END
  END k[2]
  PIN o[0]
    DIRECTION OUTPUT ;
    USE SIGNAL ;
    PORT
      LAYER M4 ;
        RECT  0 1.056 0.084 1.08 ;
    END
  END o[0]
  PIN o[100]
    DIRECTION OUTPUT ;
    USE SIGNAL ;
    PORT
      LAYER M4 ;
        RECT  0 18.096 0.084 18.12 ;
    END
  END o[100]
  PIN o[101]
    DIRECTION OUTPUT ;
    USE SIGNAL ;
    PORT
      LAYER M4 ;
        RECT  0 18.288 0.084 18.312 ;
    END
  END o[101]
  PIN o[102]
    DIRECTION OUTPUT ;
    USE SIGNAL ;
    PORT
      LAYER M4 ;
        RECT  0 18.48 0.084 18.504 ;
    END
  END o[102]
  PIN o[103]
    DIRECTION OUTPUT ;
    USE SIGNAL ;
    PORT
      LAYER M4 ;
        RECT  0 18.624 0.084 18.648 ;
    END
  END o[103]
  PIN o[104]
    DIRECTION OUTPUT ;
    USE SIGNAL ;
    PORT
      LAYER M4 ;
        RECT  0 18.816 0.084 18.84 ;
    END
  END o[104]
  PIN o[105]
    DIRECTION OUTPUT ;
    USE SIGNAL ;
    PORT
      LAYER M4 ;
        RECT  0 18.96 0.084 18.984 ;
    END
  END o[105]
  PIN o[106]
    DIRECTION OUTPUT ;
    USE SIGNAL ;
    PORT
      LAYER M4 ;
        RECT  0 19.152 0.084 19.176 ;
    END
  END o[106]
  PIN o[107]
    DIRECTION OUTPUT ;
    USE SIGNAL ;
    PORT
      LAYER M4 ;
        RECT  0 19.296 0.084 19.32 ;
    END
  END o[107]
  PIN o[108]
    DIRECTION OUTPUT ;
    USE SIGNAL ;
    PORT
      LAYER M4 ;
        RECT  0 19.488 0.084 19.512 ;
    END
  END o[108]
  PIN o[109]
    DIRECTION OUTPUT ;
    USE SIGNAL ;
    PORT
      LAYER M4 ;
        RECT  0 19.632 0.084 19.656 ;
    END
  END o[109]
  PIN o[10]
    DIRECTION OUTPUT ;
    USE SIGNAL ;
    PORT
      LAYER M4 ;
        RECT  0 2.784 0.084 2.808 ;
    END
  END o[10]
  PIN o[110]
    DIRECTION OUTPUT ;
    USE SIGNAL ;
    PORT
      LAYER M4 ;
        RECT  0 19.824 0.084 19.848 ;
    END
  END o[110]
  PIN o[111]
    DIRECTION OUTPUT ;
    USE SIGNAL ;
    PORT
      LAYER M4 ;
        RECT  0 19.968 0.084 19.992 ;
    END
  END o[111]
  PIN o[112]
    DIRECTION OUTPUT ;
    USE SIGNAL ;
    PORT
      LAYER M4 ;
        RECT  0 20.16 0.084 20.184 ;
    END
  END o[112]
  PIN o[113]
    DIRECTION OUTPUT ;
    USE SIGNAL ;
    PORT
      LAYER M4 ;
        RECT  0 20.352 0.084 20.376 ;
    END
  END o[113]
  PIN o[114]
    DIRECTION OUTPUT ;
    USE SIGNAL ;
    PORT
      LAYER M4 ;
        RECT  0 20.496 0.084 20.52 ;
    END
  END o[114]
  PIN o[115]
    DIRECTION OUTPUT ;
    USE SIGNAL ;
    PORT
      LAYER M4 ;
        RECT  0 20.688 0.084 20.712 ;
    END
  END o[115]
  PIN o[116]
    DIRECTION OUTPUT ;
    USE SIGNAL ;
    PORT
      LAYER M4 ;
        RECT  0 20.832 0.084 20.856 ;
    END
  END o[116]
  PIN o[117]
    DIRECTION OUTPUT ;
    USE SIGNAL ;
    PORT
      LAYER M4 ;
        RECT  0 21.024 0.084 21.048 ;
    END
  END o[117]
  PIN o[118]
    DIRECTION OUTPUT ;
    USE SIGNAL ;
    PORT
      LAYER M4 ;
        RECT  0 21.168 0.084 21.192 ;
    END
  END o[118]
  PIN o[119]
    DIRECTION OUTPUT ;
    USE SIGNAL ;
    PORT
      LAYER M4 ;
        RECT  0 21.36 0.084 21.384 ;
    END
  END o[119]
  PIN o[11]
    DIRECTION OUTPUT ;
    USE SIGNAL ;
    PORT
      LAYER M4 ;
        RECT  0 2.928 0.084 2.952 ;
    END
  END o[11]
  PIN o[120]
    DIRECTION OUTPUT ;
    USE SIGNAL ;
    PORT
      LAYER M4 ;
        RECT  0 21.504 0.084 21.528 ;
    END
  END o[120]
  PIN o[121]
    DIRECTION OUTPUT ;
    USE SIGNAL ;
    PORT
      LAYER M4 ;
        RECT  0 21.696 0.084 21.72 ;
    END
  END o[121]
  PIN o[122]
    DIRECTION OUTPUT ;
    USE SIGNAL ;
    PORT
      LAYER M4 ;
        RECT  0 21.888 0.084 21.912 ;
    END
  END o[122]
  PIN o[123]
    DIRECTION OUTPUT ;
    USE SIGNAL ;
    PORT
      LAYER M4 ;
        RECT  0 22.032 0.084 22.056 ;
    END
  END o[123]
  PIN o[124]
    DIRECTION OUTPUT ;
    USE SIGNAL ;
    PORT
      LAYER M4 ;
        RECT  0 22.224 0.084 22.248 ;
    END
  END o[124]
  PIN o[125]
    DIRECTION OUTPUT ;
    USE SIGNAL ;
    PORT
      LAYER M4 ;
        RECT  0 22.368 0.084 22.392 ;
    END
  END o[125]
  PIN o[126]
    DIRECTION OUTPUT ;
    USE SIGNAL ;
    PORT
      LAYER M4 ;
        RECT  0 22.56 0.084 22.584 ;
    END
  END o[126]
  PIN o[127]
    DIRECTION OUTPUT ;
    USE SIGNAL ;
    PORT
      LAYER M4 ;
        RECT  0 22.704 0.084 22.728 ;
    END
  END o[127]
  PIN o[128]
    DIRECTION OUTPUT ;
    USE SIGNAL ;
    PORT
      LAYER M4 ;
        RECT  0 22.896 0.084 22.92 ;
    END
  END o[128]
  PIN o[129]
    DIRECTION OUTPUT ;
    USE SIGNAL ;
    PORT
      LAYER M4 ;
        RECT  0 23.04 0.084 23.064 ;
    END
  END o[129]
  PIN o[12]
    DIRECTION OUTPUT ;
    USE SIGNAL ;
    PORT
      LAYER M4 ;
        RECT  0 3.12 0.084 3.144 ;
    END
  END o[12]
  PIN o[130]
    DIRECTION OUTPUT ;
    USE SIGNAL ;
    PORT
      LAYER M4 ;
        RECT  0 23.232 0.084 23.256 ;
    END
  END o[130]
  PIN o[131]
    DIRECTION OUTPUT ;
    USE SIGNAL ;
    PORT
      LAYER M4 ;
        RECT  0 23.424 0.084 23.448 ;
    END
  END o[131]
  PIN o[132]
    DIRECTION OUTPUT ;
    USE SIGNAL ;
    PORT
      LAYER M4 ;
        RECT  0 23.568 0.084 23.592 ;
    END
  END o[132]
  PIN o[133]
    DIRECTION OUTPUT ;
    USE SIGNAL ;
    PORT
      LAYER M4 ;
        RECT  0 23.76 0.084 23.784 ;
    END
  END o[133]
  PIN o[134]
    DIRECTION OUTPUT ;
    USE SIGNAL ;
    PORT
      LAYER M4 ;
        RECT  0 23.904 0.084 23.928 ;
    END
  END o[134]
  PIN o[135]
    DIRECTION OUTPUT ;
    USE SIGNAL ;
    PORT
      LAYER M4 ;
        RECT  0 24.096 0.084 24.12 ;
    END
  END o[135]
  PIN o[136]
    DIRECTION OUTPUT ;
    USE SIGNAL ;
    PORT
      LAYER M4 ;
        RECT  0 24.24 0.084 24.264 ;
    END
  END o[136]
  PIN o[137]
    DIRECTION OUTPUT ;
    USE SIGNAL ;
    PORT
      LAYER M4 ;
        RECT  0 24.432 0.084 24.456 ;
    END
  END o[137]
  PIN o[138]
    DIRECTION OUTPUT ;
    USE SIGNAL ;
    PORT
      LAYER M4 ;
        RECT  0 24.576 0.084 24.6 ;
    END
  END o[138]
  PIN o[139]
    DIRECTION OUTPUT ;
    USE SIGNAL ;
    PORT
      LAYER M4 ;
        RECT  0 24.768 0.084 24.792 ;
    END
  END o[139]
  PIN o[13]
    DIRECTION OUTPUT ;
    USE SIGNAL ;
    PORT
      LAYER M4 ;
        RECT  0 3.312 0.084 3.336 ;
    END
  END o[13]
  PIN o[140]
    DIRECTION OUTPUT ;
    USE SIGNAL ;
    PORT
      LAYER M4 ;
        RECT  0 24.912 0.084 24.936 ;
    END
  END o[140]
  PIN o[141]
    DIRECTION OUTPUT ;
    USE SIGNAL ;
    PORT
      LAYER M4 ;
        RECT  0 25.104 0.084 25.128 ;
    END
  END o[141]
  PIN o[142]
    DIRECTION OUTPUT ;
    USE SIGNAL ;
    PORT
      LAYER M4 ;
        RECT  0 25.296 0.084 25.32 ;
    END
  END o[142]
  PIN o[143]
    DIRECTION OUTPUT ;
    USE SIGNAL ;
    PORT
      LAYER M4 ;
        RECT  0 25.44 0.084 25.464 ;
    END
  END o[143]
  PIN o[144]
    DIRECTION OUTPUT ;
    USE SIGNAL ;
    PORT
      LAYER M4 ;
        RECT  0 25.632 0.084 25.656 ;
    END
  END o[144]
  PIN o[145]
    DIRECTION OUTPUT ;
    USE SIGNAL ;
    PORT
      LAYER M4 ;
        RECT  0 25.776 0.084 25.8 ;
    END
  END o[145]
  PIN o[146]
    DIRECTION OUTPUT ;
    USE SIGNAL ;
    PORT
      LAYER M4 ;
        RECT  0 25.968 0.084 25.992 ;
    END
  END o[146]
  PIN o[147]
    DIRECTION OUTPUT ;
    USE SIGNAL ;
    PORT
      LAYER M4 ;
        RECT  0 26.112 0.084 26.136 ;
    END
  END o[147]
  PIN o[148]
    DIRECTION OUTPUT ;
    USE SIGNAL ;
    PORT
      LAYER M4 ;
        RECT  0 26.304 0.084 26.328 ;
    END
  END o[148]
  PIN o[149]
    DIRECTION OUTPUT ;
    USE SIGNAL ;
    PORT
      LAYER M4 ;
        RECT  0 26.448 0.084 26.472 ;
    END
  END o[149]
  PIN o[14]
    DIRECTION OUTPUT ;
    USE SIGNAL ;
    PORT
      LAYER M4 ;
        RECT  0 3.456 0.084 3.48 ;
    END
  END o[14]
  PIN o[150]
    DIRECTION OUTPUT ;
    USE SIGNAL ;
    PORT
      LAYER M4 ;
        RECT  0 26.64 0.084 26.664 ;
    END
  END o[150]
  PIN o[151]
    DIRECTION OUTPUT ;
    USE SIGNAL ;
    PORT
      LAYER M4 ;
        RECT  0 26.832 0.084 26.856 ;
    END
  END o[151]
  PIN o[152]
    DIRECTION OUTPUT ;
    USE SIGNAL ;
    PORT
      LAYER M4 ;
        RECT  0 26.976 0.084 27 ;
    END
  END o[152]
  PIN o[153]
    DIRECTION OUTPUT ;
    USE SIGNAL ;
    PORT
      LAYER M4 ;
        RECT  0 27.168 0.084 27.192 ;
    END
  END o[153]
  PIN o[154]
    DIRECTION OUTPUT ;
    USE SIGNAL ;
    PORT
      LAYER M4 ;
        RECT  0 27.312 0.084 27.336 ;
    END
  END o[154]
  PIN o[155]
    DIRECTION OUTPUT ;
    USE SIGNAL ;
    PORT
      LAYER M4 ;
        RECT  0 27.504 0.084 27.528 ;
    END
  END o[155]
  PIN o[156]
    DIRECTION OUTPUT ;
    USE SIGNAL ;
    PORT
      LAYER M4 ;
        RECT  0 27.648 0.084 27.672 ;
    END
  END o[156]
  PIN o[157]
    DIRECTION OUTPUT ;
    USE SIGNAL ;
    PORT
      LAYER M4 ;
        RECT  0 27.84 0.084 27.864 ;
    END
  END o[157]
  PIN o[158]
    DIRECTION OUTPUT ;
    USE SIGNAL ;
    PORT
      LAYER M4 ;
        RECT  0 27.984 0.084 28.008 ;
    END
  END o[158]
  PIN o[159]
    DIRECTION OUTPUT ;
    USE SIGNAL ;
    PORT
      LAYER M4 ;
        RECT  0 28.176 0.084 28.2 ;
    END
  END o[159]
  PIN o[15]
    DIRECTION OUTPUT ;
    USE SIGNAL ;
    PORT
      LAYER M4 ;
        RECT  0 3.648 0.084 3.672 ;
    END
  END o[15]
  PIN o[160]
    DIRECTION OUTPUT ;
    USE SIGNAL ;
    PORT
      LAYER M4 ;
        RECT  0 28.32 0.084 28.344 ;
    END
  END o[160]
  PIN o[161]
    DIRECTION OUTPUT ;
    USE SIGNAL ;
    PORT
      LAYER M4 ;
        RECT  0 28.512 0.084 28.536 ;
    END
  END o[161]
  PIN o[162]
    DIRECTION OUTPUT ;
    USE SIGNAL ;
    PORT
      LAYER M4 ;
        RECT  0 28.704 0.084 28.728 ;
    END
  END o[162]
  PIN o[163]
    DIRECTION OUTPUT ;
    USE SIGNAL ;
    PORT
      LAYER M4 ;
        RECT  0 28.848 0.084 28.872 ;
    END
  END o[163]
  PIN o[164]
    DIRECTION OUTPUT ;
    USE SIGNAL ;
    PORT
      LAYER M4 ;
        RECT  0 29.04 0.084 29.064 ;
    END
  END o[164]
  PIN o[165]
    DIRECTION OUTPUT ;
    USE SIGNAL ;
    PORT
      LAYER M4 ;
        RECT  0 29.184 0.084 29.208 ;
    END
  END o[165]
  PIN o[166]
    DIRECTION OUTPUT ;
    USE SIGNAL ;
    PORT
      LAYER M4 ;
        RECT  0 29.376 0.084 29.4 ;
    END
  END o[166]
  PIN o[167]
    DIRECTION OUTPUT ;
    USE SIGNAL ;
    PORT
      LAYER M4 ;
        RECT  0 29.52 0.084 29.544 ;
    END
  END o[167]
  PIN o[168]
    DIRECTION OUTPUT ;
    USE SIGNAL ;
    PORT
      LAYER M4 ;
        RECT  0 29.712 0.084 29.736 ;
    END
  END o[168]
  PIN o[169]
    DIRECTION OUTPUT ;
    USE SIGNAL ;
    PORT
      LAYER M4 ;
        RECT  0 29.856 0.084 29.88 ;
    END
  END o[169]
  PIN o[16]
    DIRECTION OUTPUT ;
    USE SIGNAL ;
    PORT
      LAYER M4 ;
        RECT  0 3.792 0.084 3.816 ;
    END
  END o[16]
  PIN o[170]
    DIRECTION OUTPUT ;
    USE SIGNAL ;
    PORT
      LAYER M4 ;
        RECT  0 30.048 0.084 30.072 ;
    END
  END o[170]
  PIN o[171]
    DIRECTION OUTPUT ;
    USE SIGNAL ;
    PORT
      LAYER M4 ;
        RECT  0 30.24 0.084 30.264 ;
    END
  END o[171]
  PIN o[172]
    DIRECTION OUTPUT ;
    USE SIGNAL ;
    PORT
      LAYER M4 ;
        RECT  0 30.384 0.084 30.408 ;
    END
  END o[172]
  PIN o[173]
    DIRECTION OUTPUT ;
    USE SIGNAL ;
    PORT
      LAYER M4 ;
        RECT  0 30.576 0.084 30.6 ;
    END
  END o[173]
  PIN o[174]
    DIRECTION OUTPUT ;
    USE SIGNAL ;
    PORT
      LAYER M4 ;
        RECT  0 30.72 0.084 30.744 ;
    END
  END o[174]
  PIN o[175]
    DIRECTION OUTPUT ;
    USE SIGNAL ;
    PORT
      LAYER M4 ;
        RECT  0 30.912 0.084 30.936 ;
    END
  END o[175]
  PIN o[176]
    DIRECTION OUTPUT ;
    USE SIGNAL ;
    PORT
      LAYER M4 ;
        RECT  0 31.056 0.084 31.08 ;
    END
  END o[176]
  PIN o[177]
    DIRECTION OUTPUT ;
    USE SIGNAL ;
    PORT
      LAYER M4 ;
        RECT  0 31.248 0.084 31.272 ;
    END
  END o[177]
  PIN o[178]
    DIRECTION OUTPUT ;
    USE SIGNAL ;
    PORT
      LAYER M4 ;
        RECT  0 31.392 0.084 31.416 ;
    END
  END o[178]
  PIN o[179]
    DIRECTION OUTPUT ;
    USE SIGNAL ;
    PORT
      LAYER M4 ;
        RECT  0 31.584 0.084 31.608 ;
    END
  END o[179]
  PIN o[17]
    DIRECTION OUTPUT ;
    USE SIGNAL ;
    PORT
      LAYER M4 ;
        RECT  0 3.984 0.084 4.008 ;
    END
  END o[17]
  PIN o[180]
    DIRECTION OUTPUT ;
    USE SIGNAL ;
    PORT
      LAYER M4 ;
        RECT  0 31.728 0.084 31.752 ;
    END
  END o[180]
  PIN o[181]
    DIRECTION OUTPUT ;
    USE SIGNAL ;
    PORT
      LAYER M4 ;
        RECT  0 31.92 0.084 31.944 ;
    END
  END o[181]
  PIN o[182]
    DIRECTION OUTPUT ;
    USE SIGNAL ;
    PORT
      LAYER M4 ;
        RECT  0 32.112 0.084 32.136 ;
    END
  END o[182]
  PIN o[183]
    DIRECTION OUTPUT ;
    USE SIGNAL ;
    PORT
      LAYER M4 ;
        RECT  0 32.256 0.084 32.28 ;
    END
  END o[183]
  PIN o[184]
    DIRECTION OUTPUT ;
    USE SIGNAL ;
    PORT
      LAYER M4 ;
        RECT  0 32.448 0.084 32.472 ;
    END
  END o[184]
  PIN o[185]
    DIRECTION OUTPUT ;
    USE SIGNAL ;
    PORT
      LAYER M4 ;
        RECT  0 32.592 0.084 32.616 ;
    END
  END o[185]
  PIN o[186]
    DIRECTION OUTPUT ;
    USE SIGNAL ;
    PORT
      LAYER M4 ;
        RECT  0 32.784 0.084 32.808 ;
    END
  END o[186]
  PIN o[187]
    DIRECTION OUTPUT ;
    USE SIGNAL ;
    PORT
      LAYER M4 ;
        RECT  0 32.928 0.084 32.952 ;
    END
  END o[187]
  PIN o[188]
    DIRECTION OUTPUT ;
    USE SIGNAL ;
    PORT
      LAYER M4 ;
        RECT  0 33.12 0.084 33.144 ;
    END
  END o[188]
  PIN o[189]
    DIRECTION OUTPUT ;
    USE SIGNAL ;
    PORT
      LAYER M4 ;
        RECT  0 33.264 0.084 33.288 ;
    END
  END o[189]
  PIN o[18]
    DIRECTION OUTPUT ;
    USE SIGNAL ;
    PORT
      LAYER M4 ;
        RECT  0 4.128 0.084 4.152 ;
    END
  END o[18]
  PIN o[190]
    DIRECTION OUTPUT ;
    USE SIGNAL ;
    PORT
      LAYER M4 ;
        RECT  0 33.456 0.084 33.48 ;
    END
  END o[190]
  PIN o[191]
    DIRECTION OUTPUT ;
    USE SIGNAL ;
    PORT
      LAYER M4 ;
        RECT  0 33.648 0.084 33.672 ;
    END
  END o[191]
  PIN o[192]
    DIRECTION OUTPUT ;
    USE SIGNAL ;
    PORT
      LAYER M4 ;
        RECT  0 33.792 0.084 33.816 ;
    END
  END o[192]
  PIN o[193]
    DIRECTION OUTPUT ;
    USE SIGNAL ;
    PORT
      LAYER M4 ;
        RECT  0 33.984 0.084 34.008 ;
    END
  END o[193]
  PIN o[194]
    DIRECTION OUTPUT ;
    USE SIGNAL ;
    PORT
      LAYER M4 ;
        RECT  0 34.128 0.084 34.152 ;
    END
  END o[194]
  PIN o[195]
    DIRECTION OUTPUT ;
    USE SIGNAL ;
    PORT
      LAYER M4 ;
        RECT  0 34.32 0.084 34.344 ;
    END
  END o[195]
  PIN o[196]
    DIRECTION OUTPUT ;
    USE SIGNAL ;
    PORT
      LAYER M4 ;
        RECT  0 34.464 0.084 34.488 ;
    END
  END o[196]
  PIN o[197]
    DIRECTION OUTPUT ;
    USE SIGNAL ;
    PORT
      LAYER M4 ;
        RECT  0 34.656 0.084 34.68 ;
    END
  END o[197]
  PIN o[198]
    DIRECTION OUTPUT ;
    USE SIGNAL ;
    PORT
      LAYER M4 ;
        RECT  0 34.8 0.084 34.824 ;
    END
  END o[198]
  PIN o[199]
    DIRECTION OUTPUT ;
    USE SIGNAL ;
    PORT
      LAYER M4 ;
        RECT  0 34.992 0.084 35.016 ;
    END
  END o[199]
  PIN o[19]
    DIRECTION OUTPUT ;
    USE SIGNAL ;
    PORT
      LAYER M4 ;
        RECT  0 4.32 0.084 4.344 ;
    END
  END o[19]
  PIN o[1]
    DIRECTION OUTPUT ;
    USE SIGNAL ;
    PORT
      LAYER M4 ;
        RECT  0 1.248 0.084 1.272 ;
    END
  END o[1]
  PIN o[200]
    DIRECTION OUTPUT ;
    USE SIGNAL ;
    PORT
      LAYER M4 ;
        RECT  0 35.184 0.084 35.208 ;
    END
  END o[200]
  PIN o[201]
    DIRECTION OUTPUT ;
    USE SIGNAL ;
    PORT
      LAYER M4 ;
        RECT  0 35.328 0.084 35.352 ;
    END
  END o[201]
  PIN o[202]
    DIRECTION OUTPUT ;
    USE SIGNAL ;
    PORT
      LAYER M4 ;
        RECT  0 35.52 0.084 35.544 ;
    END
  END o[202]
  PIN o[203]
    DIRECTION OUTPUT ;
    USE SIGNAL ;
    PORT
      LAYER M4 ;
        RECT  0 35.664 0.084 35.688 ;
    END
  END o[203]
  PIN o[204]
    DIRECTION OUTPUT ;
    USE SIGNAL ;
    PORT
      LAYER M4 ;
        RECT  0 35.856 0.084 35.88 ;
    END
  END o[204]
  PIN o[205]
    DIRECTION OUTPUT ;
    USE SIGNAL ;
    PORT
      LAYER M4 ;
        RECT  0 36 0.084 36.024 ;
    END
  END o[205]
  PIN o[206]
    DIRECTION OUTPUT ;
    USE SIGNAL ;
    PORT
      LAYER M4 ;
        RECT  0 36.192 0.084 36.216 ;
    END
  END o[206]
  PIN o[207]
    DIRECTION OUTPUT ;
    USE SIGNAL ;
    PORT
      LAYER M4 ;
        RECT  0 36.336 0.084 36.36 ;
    END
  END o[207]
  PIN o[208]
    DIRECTION OUTPUT ;
    USE SIGNAL ;
    PORT
      LAYER M4 ;
        RECT  0 36.528 0.084 36.552 ;
    END
  END o[208]
  PIN o[209]
    DIRECTION OUTPUT ;
    USE SIGNAL ;
    PORT
      LAYER M4 ;
        RECT  0 36.672 0.084 36.696 ;
    END
  END o[209]
  PIN o[20]
    DIRECTION OUTPUT ;
    USE SIGNAL ;
    PORT
      LAYER M4 ;
        RECT  0 4.464 0.084 4.488 ;
    END
  END o[20]
  PIN o[210]
    DIRECTION OUTPUT ;
    USE SIGNAL ;
    PORT
      LAYER M4 ;
        RECT  0 36.864 0.084 36.888 ;
    END
  END o[210]
  PIN o[211]
    DIRECTION OUTPUT ;
    USE SIGNAL ;
    PORT
      LAYER M4 ;
        RECT  0 37.056 0.084 37.08 ;
    END
  END o[211]
  PIN o[212]
    DIRECTION OUTPUT ;
    USE SIGNAL ;
    PORT
      LAYER M4 ;
        RECT  0 37.2 0.084 37.224 ;
    END
  END o[212]
  PIN o[213]
    DIRECTION OUTPUT ;
    USE SIGNAL ;
    PORT
      LAYER M4 ;
        RECT  0 37.392 0.084 37.416 ;
    END
  END o[213]
  PIN o[214]
    DIRECTION OUTPUT ;
    USE SIGNAL ;
    PORT
      LAYER M4 ;
        RECT  0 37.536 0.084 37.56 ;
    END
  END o[214]
  PIN o[215]
    DIRECTION OUTPUT ;
    USE SIGNAL ;
    PORT
      LAYER M4 ;
        RECT  0 37.728 0.084 37.752 ;
    END
  END o[215]
  PIN o[216]
    DIRECTION OUTPUT ;
    USE SIGNAL ;
    PORT
      LAYER M4 ;
        RECT  0 37.872 0.084 37.896 ;
    END
  END o[216]
  PIN o[217]
    DIRECTION OUTPUT ;
    USE SIGNAL ;
    PORT
      LAYER M4 ;
        RECT  0 38.064 0.084 38.088 ;
    END
  END o[217]
  PIN o[218]
    DIRECTION OUTPUT ;
    USE SIGNAL ;
    PORT
      LAYER M4 ;
        RECT  0 38.208 0.084 38.232 ;
    END
  END o[218]
  PIN o[219]
    DIRECTION OUTPUT ;
    USE SIGNAL ;
    PORT
      LAYER M4 ;
        RECT  0 38.4 0.084 38.424 ;
    END
  END o[219]
  PIN o[21]
    DIRECTION OUTPUT ;
    USE SIGNAL ;
    PORT
      LAYER M4 ;
        RECT  0 4.656 0.084 4.68 ;
    END
  END o[21]
  PIN o[220]
    DIRECTION OUTPUT ;
    USE SIGNAL ;
    PORT
      LAYER M4 ;
        RECT  0 38.592 0.084 38.616 ;
    END
  END o[220]
  PIN o[221]
    DIRECTION OUTPUT ;
    USE SIGNAL ;
    PORT
      LAYER M4 ;
        RECT  0 38.736 0.084 38.76 ;
    END
  END o[221]
  PIN o[222]
    DIRECTION OUTPUT ;
    USE SIGNAL ;
    PORT
      LAYER M4 ;
        RECT  0 38.928 0.084 38.952 ;
    END
  END o[222]
  PIN o[223]
    DIRECTION OUTPUT ;
    USE SIGNAL ;
    PORT
      LAYER M4 ;
        RECT  0 39.072 0.084 39.096 ;
    END
  END o[223]
  PIN o[224]
    DIRECTION OUTPUT ;
    USE SIGNAL ;
    PORT
      LAYER M4 ;
        RECT  0 39.264 0.084 39.288 ;
    END
  END o[224]
  PIN o[225]
    DIRECTION OUTPUT ;
    USE SIGNAL ;
    PORT
      LAYER M4 ;
        RECT  0 39.408 0.084 39.432 ;
    END
  END o[225]
  PIN o[226]
    DIRECTION OUTPUT ;
    USE SIGNAL ;
    PORT
      LAYER M4 ;
        RECT  0 39.6 0.084 39.624 ;
    END
  END o[226]
  PIN o[227]
    DIRECTION OUTPUT ;
    USE SIGNAL ;
    PORT
      LAYER M4 ;
        RECT  0 39.744 0.084 39.768 ;
    END
  END o[227]
  PIN o[228]
    DIRECTION OUTPUT ;
    USE SIGNAL ;
    PORT
      LAYER M4 ;
        RECT  0 39.936 0.084 39.96 ;
    END
  END o[228]
  PIN o[229]
    DIRECTION OUTPUT ;
    USE SIGNAL ;
    PORT
      LAYER M4 ;
        RECT  0 40.08 0.084 40.104 ;
    END
  END o[229]
  PIN o[22]
    DIRECTION OUTPUT ;
    USE SIGNAL ;
    PORT
      LAYER M4 ;
        RECT  0 4.8 0.084 4.824 ;
    END
  END o[22]
  PIN o[230]
    DIRECTION OUTPUT ;
    USE SIGNAL ;
    PORT
      LAYER M4 ;
        RECT  0 40.272 0.084 40.296 ;
    END
  END o[230]
  PIN o[231]
    DIRECTION OUTPUT ;
    USE SIGNAL ;
    PORT
      LAYER M4 ;
        RECT  0 40.464 0.084 40.488 ;
    END
  END o[231]
  PIN o[232]
    DIRECTION OUTPUT ;
    USE SIGNAL ;
    PORT
      LAYER M4 ;
        RECT  0 40.608 0.084 40.632 ;
    END
  END o[232]
  PIN o[233]
    DIRECTION OUTPUT ;
    USE SIGNAL ;
    PORT
      LAYER M4 ;
        RECT  0 40.8 0.084 40.824 ;
    END
  END o[233]
  PIN o[234]
    DIRECTION OUTPUT ;
    USE SIGNAL ;
    PORT
      LAYER M4 ;
        RECT  0 40.944 0.084 40.968 ;
    END
  END o[234]
  PIN o[235]
    DIRECTION OUTPUT ;
    USE SIGNAL ;
    PORT
      LAYER M4 ;
        RECT  0 41.136 0.084 41.16 ;
    END
  END o[235]
  PIN o[236]
    DIRECTION OUTPUT ;
    USE SIGNAL ;
    PORT
      LAYER M4 ;
        RECT  0 41.28 0.084 41.304 ;
    END
  END o[236]
  PIN o[237]
    DIRECTION OUTPUT ;
    USE SIGNAL ;
    PORT
      LAYER M4 ;
        RECT  0 41.472 0.084 41.496 ;
    END
  END o[237]
  PIN o[238]
    DIRECTION OUTPUT ;
    USE SIGNAL ;
    PORT
      LAYER M4 ;
        RECT  0 41.616 0.084 41.64 ;
    END
  END o[238]
  PIN o[239]
    DIRECTION OUTPUT ;
    USE SIGNAL ;
    PORT
      LAYER M4 ;
        RECT  0 41.808 0.084 41.832 ;
    END
  END o[239]
  PIN o[23]
    DIRECTION OUTPUT ;
    USE SIGNAL ;
    PORT
      LAYER M4 ;
        RECT  0 4.992 0.084 5.016 ;
    END
  END o[23]
  PIN o[240]
    DIRECTION OUTPUT ;
    USE SIGNAL ;
    PORT
      LAYER M4 ;
        RECT  0 42 0.084 42.024 ;
    END
  END o[240]
  PIN o[241]
    DIRECTION OUTPUT ;
    USE SIGNAL ;
    PORT
      LAYER M4 ;
        RECT  0 42.144 0.084 42.168 ;
    END
  END o[241]
  PIN o[242]
    DIRECTION OUTPUT ;
    USE SIGNAL ;
    PORT
      LAYER M4 ;
        RECT  0 42.336 0.084 42.36 ;
    END
  END o[242]
  PIN o[243]
    DIRECTION OUTPUT ;
    USE SIGNAL ;
    PORT
      LAYER M4 ;
        RECT  0 42.48 0.084 42.504 ;
    END
  END o[243]
  PIN o[244]
    DIRECTION OUTPUT ;
    USE SIGNAL ;
    PORT
      LAYER M4 ;
        RECT  0 42.672 0.084 42.696 ;
    END
  END o[244]
  PIN o[245]
    DIRECTION OUTPUT ;
    USE SIGNAL ;
    PORT
      LAYER M4 ;
        RECT  0 42.816 0.084 42.84 ;
    END
  END o[245]
  PIN o[246]
    DIRECTION OUTPUT ;
    USE SIGNAL ;
    PORT
      LAYER M4 ;
        RECT  0 43.008 0.084 43.032 ;
    END
  END o[246]
  PIN o[247]
    DIRECTION OUTPUT ;
    USE SIGNAL ;
    PORT
      LAYER M4 ;
        RECT  0 43.152 0.084 43.176 ;
    END
  END o[247]
  PIN o[248]
    DIRECTION OUTPUT ;
    USE SIGNAL ;
    PORT
      LAYER M4 ;
        RECT  0 43.344 0.084 43.368 ;
    END
  END o[248]
  PIN o[249]
    DIRECTION OUTPUT ;
    USE SIGNAL ;
    PORT
      LAYER M4 ;
        RECT  0 43.488 0.084 43.512 ;
    END
  END o[249]
  PIN o[24]
    DIRECTION OUTPUT ;
    USE SIGNAL ;
    PORT
      LAYER M4 ;
        RECT  0 5.184 0.084 5.208 ;
    END
  END o[24]
  PIN o[250]
    DIRECTION OUTPUT ;
    USE SIGNAL ;
    PORT
      LAYER M4 ;
        RECT  0 43.68 0.084 43.704 ;
    END
  END o[250]
  PIN o[251]
    DIRECTION OUTPUT ;
    USE SIGNAL ;
    PORT
      LAYER M4 ;
        RECT  0 43.872 0.084 43.896 ;
    END
  END o[251]
  PIN o[252]
    DIRECTION OUTPUT ;
    USE SIGNAL ;
    PORT
      LAYER M4 ;
        RECT  0 44.016 0.084 44.04 ;
    END
  END o[252]
  PIN o[253]
    DIRECTION OUTPUT ;
    USE SIGNAL ;
    PORT
      LAYER M4 ;
        RECT  0 44.208 0.084 44.232 ;
    END
  END o[253]
  PIN o[254]
    DIRECTION OUTPUT ;
    USE SIGNAL ;
    PORT
      LAYER M4 ;
        RECT  0 44.352 0.084 44.376 ;
    END
  END o[254]
  PIN o[255]
    DIRECTION OUTPUT ;
    USE SIGNAL ;
    PORT
      LAYER M4 ;
        RECT  0 44.544 0.084 44.568 ;
    END
  END o[255]
  PIN o[256]
    DIRECTION OUTPUT ;
    USE SIGNAL ;
    PORT
      LAYER M4 ;
        RECT  0 44.688 0.084 44.712 ;
    END
  END o[256]
  PIN o[257]
    DIRECTION OUTPUT ;
    USE SIGNAL ;
    PORT
      LAYER M4 ;
        RECT  0 44.88 0.084 44.904 ;
    END
  END o[257]
  PIN o[258]
    DIRECTION OUTPUT ;
    USE SIGNAL ;
    PORT
      LAYER M4 ;
        RECT  0 45.024 0.084 45.048 ;
    END
  END o[258]
  PIN o[259]
    DIRECTION OUTPUT ;
    USE SIGNAL ;
    PORT
      LAYER M4 ;
        RECT  0 45.216 0.084 45.24 ;
    END
  END o[259]
  PIN o[25]
    DIRECTION OUTPUT ;
    USE SIGNAL ;
    PORT
      LAYER M4 ;
        RECT  0 5.328 0.084 5.352 ;
    END
  END o[25]
  PIN o[260]
    DIRECTION OUTPUT ;
    USE SIGNAL ;
    PORT
      LAYER M4 ;
        RECT  0 45.408 0.084 45.432 ;
    END
  END o[260]
  PIN o[261]
    DIRECTION OUTPUT ;
    USE SIGNAL ;
    PORT
      LAYER M4 ;
        RECT  0 45.552 0.084 45.576 ;
    END
  END o[261]
  PIN o[262]
    DIRECTION OUTPUT ;
    USE SIGNAL ;
    PORT
      LAYER M4 ;
        RECT  0 45.744 0.084 45.768 ;
    END
  END o[262]
  PIN o[263]
    DIRECTION OUTPUT ;
    USE SIGNAL ;
    PORT
      LAYER M4 ;
        RECT  0 45.888 0.084 45.912 ;
    END
  END o[263]
  PIN o[264]
    DIRECTION OUTPUT ;
    USE SIGNAL ;
    PORT
      LAYER M4 ;
        RECT  0 46.08 0.084 46.104 ;
    END
  END o[264]
  PIN o[265]
    DIRECTION OUTPUT ;
    USE SIGNAL ;
    PORT
      LAYER M4 ;
        RECT  0 46.224 0.084 46.248 ;
    END
  END o[265]
  PIN o[266]
    DIRECTION OUTPUT ;
    USE SIGNAL ;
    PORT
      LAYER M4 ;
        RECT  0 46.416 0.084 46.44 ;
    END
  END o[266]
  PIN o[267]
    DIRECTION OUTPUT ;
    USE SIGNAL ;
    PORT
      LAYER M4 ;
        RECT  0 46.56 0.084 46.584 ;
    END
  END o[267]
  PIN o[268]
    DIRECTION OUTPUT ;
    USE SIGNAL ;
    PORT
      LAYER M4 ;
        RECT  0 46.752 0.084 46.776 ;
    END
  END o[268]
  PIN o[269]
    DIRECTION OUTPUT ;
    USE SIGNAL ;
    PORT
      LAYER M4 ;
        RECT  0 46.944 0.084 46.968 ;
    END
  END o[269]
  PIN o[26]
    DIRECTION OUTPUT ;
    USE SIGNAL ;
    PORT
      LAYER M4 ;
        RECT  0 5.52 0.084 5.544 ;
    END
  END o[26]
  PIN o[270]
    DIRECTION OUTPUT ;
    USE SIGNAL ;
    PORT
      LAYER M4 ;
        RECT  0 47.088 0.084 47.112 ;
    END
  END o[270]
  PIN o[271]
    DIRECTION OUTPUT ;
    USE SIGNAL ;
    PORT
      LAYER M4 ;
        RECT  0 47.28 0.084 47.304 ;
    END
  END o[271]
  PIN o[272]
    DIRECTION OUTPUT ;
    USE SIGNAL ;
    PORT
      LAYER M4 ;
        RECT  0 47.424 0.084 47.448 ;
    END
  END o[272]
  PIN o[273]
    DIRECTION OUTPUT ;
    USE SIGNAL ;
    PORT
      LAYER M4 ;
        RECT  0 47.616 0.084 47.64 ;
    END
  END o[273]
  PIN o[274]
    DIRECTION OUTPUT ;
    USE SIGNAL ;
    PORT
      LAYER M4 ;
        RECT  0 47.76 0.084 47.784 ;
    END
  END o[274]
  PIN o[275]
    DIRECTION OUTPUT ;
    USE SIGNAL ;
    PORT
      LAYER M4 ;
        RECT  0 47.952 0.084 47.976 ;
    END
  END o[275]
  PIN o[27]
    DIRECTION OUTPUT ;
    USE SIGNAL ;
    PORT
      LAYER M4 ;
        RECT  0 5.664 0.084 5.688 ;
    END
  END o[27]
  PIN o[28]
    DIRECTION OUTPUT ;
    USE SIGNAL ;
    PORT
      LAYER M4 ;
        RECT  0 5.856 0.084 5.88 ;
    END
  END o[28]
  PIN o[29]
    DIRECTION OUTPUT ;
    USE SIGNAL ;
    PORT
      LAYER M4 ;
        RECT  0 6 0.084 6.024 ;
    END
  END o[29]
  PIN o[2]
    DIRECTION OUTPUT ;
    USE SIGNAL ;
    PORT
      LAYER M4 ;
        RECT  0 1.392 0.084 1.416 ;
    END
  END o[2]
  PIN o[30]
    DIRECTION OUTPUT ;
    USE SIGNAL ;
    PORT
      LAYER M4 ;
        RECT  0 6.192 0.084 6.216 ;
    END
  END o[30]
  PIN o[31]
    DIRECTION OUTPUT ;
    USE SIGNAL ;
    PORT
      LAYER M4 ;
        RECT  0 6.336 0.084 6.36 ;
    END
  END o[31]
  PIN o[32]
    DIRECTION OUTPUT ;
    USE SIGNAL ;
    PORT
      LAYER M4 ;
        RECT  0 6.528 0.084 6.552 ;
    END
  END o[32]
  PIN o[33]
    DIRECTION OUTPUT ;
    USE SIGNAL ;
    PORT
      LAYER M4 ;
        RECT  0 6.72 0.084 6.744 ;
    END
  END o[33]
  PIN o[34]
    DIRECTION OUTPUT ;
    USE SIGNAL ;
    PORT
      LAYER M4 ;
        RECT  0 6.864 0.084 6.888 ;
    END
  END o[34]
  PIN o[35]
    DIRECTION OUTPUT ;
    USE SIGNAL ;
    PORT
      LAYER M4 ;
        RECT  0 7.056 0.084 7.08 ;
    END
  END o[35]
  PIN o[36]
    DIRECTION OUTPUT ;
    USE SIGNAL ;
    PORT
      LAYER M4 ;
        RECT  0 7.2 0.084 7.224 ;
    END
  END o[36]
  PIN o[37]
    DIRECTION OUTPUT ;
    USE SIGNAL ;
    PORT
      LAYER M4 ;
        RECT  0 7.392 0.084 7.416 ;
    END
  END o[37]
  PIN o[38]
    DIRECTION OUTPUT ;
    USE SIGNAL ;
    PORT
      LAYER M4 ;
        RECT  0 7.536 0.084 7.56 ;
    END
  END o[38]
  PIN o[39]
    DIRECTION OUTPUT ;
    USE SIGNAL ;
    PORT
      LAYER M4 ;
        RECT  0 7.728 0.084 7.752 ;
    END
  END o[39]
  PIN o[3]
    DIRECTION OUTPUT ;
    USE SIGNAL ;
    PORT
      LAYER M4 ;
        RECT  0 1.584 0.084 1.608 ;
    END
  END o[3]
  PIN o[40]
    DIRECTION OUTPUT ;
    USE SIGNAL ;
    PORT
      LAYER M4 ;
        RECT  0 7.872 0.084 7.896 ;
    END
  END o[40]
  PIN o[41]
    DIRECTION OUTPUT ;
    USE SIGNAL ;
    PORT
      LAYER M4 ;
        RECT  0 8.064 0.084 8.088 ;
    END
  END o[41]
  PIN o[42]
    DIRECTION OUTPUT ;
    USE SIGNAL ;
    PORT
      LAYER M4 ;
        RECT  0 8.208 0.084 8.232 ;
    END
  END o[42]
  PIN o[43]
    DIRECTION OUTPUT ;
    USE SIGNAL ;
    PORT
      LAYER M4 ;
        RECT  0 8.4 0.084 8.424 ;
    END
  END o[43]
  PIN o[44]
    DIRECTION OUTPUT ;
    USE SIGNAL ;
    PORT
      LAYER M4 ;
        RECT  0 8.592 0.084 8.616 ;
    END
  END o[44]
  PIN o[45]
    DIRECTION OUTPUT ;
    USE SIGNAL ;
    PORT
      LAYER M4 ;
        RECT  0 8.736 0.084 8.76 ;
    END
  END o[45]
  PIN o[46]
    DIRECTION OUTPUT ;
    USE SIGNAL ;
    PORT
      LAYER M4 ;
        RECT  0 8.928 0.084 8.952 ;
    END
  END o[46]
  PIN o[47]
    DIRECTION OUTPUT ;
    USE SIGNAL ;
    PORT
      LAYER M4 ;
        RECT  0 9.072 0.084 9.096 ;
    END
  END o[47]
  PIN o[48]
    DIRECTION OUTPUT ;
    USE SIGNAL ;
    PORT
      LAYER M4 ;
        RECT  0 9.264 0.084 9.288 ;
    END
  END o[48]
  PIN o[49]
    DIRECTION OUTPUT ;
    USE SIGNAL ;
    PORT
      LAYER M4 ;
        RECT  0 9.408 0.084 9.432 ;
    END
  END o[49]
  PIN o[4]
    DIRECTION OUTPUT ;
    USE SIGNAL ;
    PORT
      LAYER M4 ;
        RECT  0 1.776 0.084 1.8 ;
    END
  END o[4]
  PIN o[50]
    DIRECTION OUTPUT ;
    USE SIGNAL ;
    PORT
      LAYER M4 ;
        RECT  0 9.6 0.084 9.624 ;
    END
  END o[50]
  PIN o[51]
    DIRECTION OUTPUT ;
    USE SIGNAL ;
    PORT
      LAYER M4 ;
        RECT  0 9.744 0.084 9.768 ;
    END
  END o[51]
  PIN o[52]
    DIRECTION OUTPUT ;
    USE SIGNAL ;
    PORT
      LAYER M4 ;
        RECT  0 9.936 0.084 9.96 ;
    END
  END o[52]
  PIN o[53]
    DIRECTION OUTPUT ;
    USE SIGNAL ;
    PORT
      LAYER M4 ;
        RECT  0 10.128 0.084 10.152 ;
    END
  END o[53]
  PIN o[54]
    DIRECTION OUTPUT ;
    USE SIGNAL ;
    PORT
      LAYER M4 ;
        RECT  0 10.272 0.084 10.296 ;
    END
  END o[54]
  PIN o[55]
    DIRECTION OUTPUT ;
    USE SIGNAL ;
    PORT
      LAYER M4 ;
        RECT  0 10.464 0.084 10.488 ;
    END
  END o[55]
  PIN o[56]
    DIRECTION OUTPUT ;
    USE SIGNAL ;
    PORT
      LAYER M4 ;
        RECT  0 10.608 0.084 10.632 ;
    END
  END o[56]
  PIN o[57]
    DIRECTION OUTPUT ;
    USE SIGNAL ;
    PORT
      LAYER M4 ;
        RECT  0 10.8 0.084 10.824 ;
    END
  END o[57]
  PIN o[58]
    DIRECTION OUTPUT ;
    USE SIGNAL ;
    PORT
      LAYER M4 ;
        RECT  0 10.944 0.084 10.968 ;
    END
  END o[58]
  PIN o[59]
    DIRECTION OUTPUT ;
    USE SIGNAL ;
    PORT
      LAYER M4 ;
        RECT  0 11.136 0.084 11.16 ;
    END
  END o[59]
  PIN o[5]
    DIRECTION OUTPUT ;
    USE SIGNAL ;
    PORT
      LAYER M4 ;
        RECT  0 1.92 0.084 1.944 ;
    END
  END o[5]
  PIN o[60]
    DIRECTION OUTPUT ;
    USE SIGNAL ;
    PORT
      LAYER M4 ;
        RECT  0 11.28 0.084 11.304 ;
    END
  END o[60]
  PIN o[61]
    DIRECTION OUTPUT ;
    USE SIGNAL ;
    PORT
      LAYER M4 ;
        RECT  0 11.472 0.084 11.496 ;
    END
  END o[61]
  PIN o[62]
    DIRECTION OUTPUT ;
    USE SIGNAL ;
    PORT
      LAYER M4 ;
        RECT  0 11.664 0.084 11.688 ;
    END
  END o[62]
  PIN o[63]
    DIRECTION OUTPUT ;
    USE SIGNAL ;
    PORT
      LAYER M4 ;
        RECT  0 11.808 0.084 11.832 ;
    END
  END o[63]
  PIN o[64]
    DIRECTION OUTPUT ;
    USE SIGNAL ;
    PORT
      LAYER M4 ;
        RECT  0 12 0.084 12.024 ;
    END
  END o[64]
  PIN o[65]
    DIRECTION OUTPUT ;
    USE SIGNAL ;
    PORT
      LAYER M4 ;
        RECT  0 12.144 0.084 12.168 ;
    END
  END o[65]
  PIN o[66]
    DIRECTION OUTPUT ;
    USE SIGNAL ;
    PORT
      LAYER M4 ;
        RECT  0 12.336 0.084 12.36 ;
    END
  END o[66]
  PIN o[67]
    DIRECTION OUTPUT ;
    USE SIGNAL ;
    PORT
      LAYER M4 ;
        RECT  0 12.48 0.084 12.504 ;
    END
  END o[67]
  PIN o[68]
    DIRECTION OUTPUT ;
    USE SIGNAL ;
    PORT
      LAYER M4 ;
        RECT  0 12.672 0.084 12.696 ;
    END
  END o[68]
  PIN o[69]
    DIRECTION OUTPUT ;
    USE SIGNAL ;
    PORT
      LAYER M4 ;
        RECT  0 12.816 0.084 12.84 ;
    END
  END o[69]
  PIN o[6]
    DIRECTION OUTPUT ;
    USE SIGNAL ;
    PORT
      LAYER M4 ;
        RECT  0 2.112 0.084 2.136 ;
    END
  END o[6]
  PIN o[70]
    DIRECTION OUTPUT ;
    USE SIGNAL ;
    PORT
      LAYER M4 ;
        RECT  0 13.008 0.084 13.032 ;
    END
  END o[70]
  PIN o[71]
    DIRECTION OUTPUT ;
    USE SIGNAL ;
    PORT
      LAYER M4 ;
        RECT  0 13.152 0.084 13.176 ;
    END
  END o[71]
  PIN o[72]
    DIRECTION OUTPUT ;
    USE SIGNAL ;
    PORT
      LAYER M4 ;
        RECT  0 13.344 0.084 13.368 ;
    END
  END o[72]
  PIN o[73]
    DIRECTION OUTPUT ;
    USE SIGNAL ;
    PORT
      LAYER M4 ;
        RECT  0 13.536 0.084 13.56 ;
    END
  END o[73]
  PIN o[74]
    DIRECTION OUTPUT ;
    USE SIGNAL ;
    PORT
      LAYER M4 ;
        RECT  0 13.68 0.084 13.704 ;
    END
  END o[74]
  PIN o[75]
    DIRECTION OUTPUT ;
    USE SIGNAL ;
    PORT
      LAYER M4 ;
        RECT  0 13.872 0.084 13.896 ;
    END
  END o[75]
  PIN o[76]
    DIRECTION OUTPUT ;
    USE SIGNAL ;
    PORT
      LAYER M4 ;
        RECT  0 14.016 0.084 14.04 ;
    END
  END o[76]
  PIN o[77]
    DIRECTION OUTPUT ;
    USE SIGNAL ;
    PORT
      LAYER M4 ;
        RECT  0 14.208 0.084 14.232 ;
    END
  END o[77]
  PIN o[78]
    DIRECTION OUTPUT ;
    USE SIGNAL ;
    PORT
      LAYER M4 ;
        RECT  0 14.352 0.084 14.376 ;
    END
  END o[78]
  PIN o[79]
    DIRECTION OUTPUT ;
    USE SIGNAL ;
    PORT
      LAYER M4 ;
        RECT  0 14.544 0.084 14.568 ;
    END
  END o[79]
  PIN o[7]
    DIRECTION OUTPUT ;
    USE SIGNAL ;
    PORT
      LAYER M4 ;
        RECT  0 2.256 0.084 2.28 ;
    END
  END o[7]
  PIN o[80]
    DIRECTION OUTPUT ;
    USE SIGNAL ;
    PORT
      LAYER M4 ;
        RECT  0 14.688 0.084 14.712 ;
    END
  END o[80]
  PIN o[81]
    DIRECTION OUTPUT ;
    USE SIGNAL ;
    PORT
      LAYER M4 ;
        RECT  0 14.88 0.084 14.904 ;
    END
  END o[81]
  PIN o[82]
    DIRECTION OUTPUT ;
    USE SIGNAL ;
    PORT
      LAYER M4 ;
        RECT  0 15.072 0.084 15.096 ;
    END
  END o[82]
  PIN o[83]
    DIRECTION OUTPUT ;
    USE SIGNAL ;
    PORT
      LAYER M4 ;
        RECT  0 15.216 0.084 15.24 ;
    END
  END o[83]
  PIN o[84]
    DIRECTION OUTPUT ;
    USE SIGNAL ;
    PORT
      LAYER M4 ;
        RECT  0 15.408 0.084 15.432 ;
    END
  END o[84]
  PIN o[85]
    DIRECTION OUTPUT ;
    USE SIGNAL ;
    PORT
      LAYER M4 ;
        RECT  0 15.552 0.084 15.576 ;
    END
  END o[85]
  PIN o[86]
    DIRECTION OUTPUT ;
    USE SIGNAL ;
    PORT
      LAYER M4 ;
        RECT  0 15.744 0.084 15.768 ;
    END
  END o[86]
  PIN o[87]
    DIRECTION OUTPUT ;
    USE SIGNAL ;
    PORT
      LAYER M4 ;
        RECT  0 15.888 0.084 15.912 ;
    END
  END o[87]
  PIN o[88]
    DIRECTION OUTPUT ;
    USE SIGNAL ;
    PORT
      LAYER M4 ;
        RECT  0 16.08 0.084 16.104 ;
    END
  END o[88]
  PIN o[89]
    DIRECTION OUTPUT ;
    USE SIGNAL ;
    PORT
      LAYER M4 ;
        RECT  0 16.224 0.084 16.248 ;
    END
  END o[89]
  PIN o[8]
    DIRECTION OUTPUT ;
    USE SIGNAL ;
    PORT
      LAYER M4 ;
        RECT  0 2.448 0.084 2.472 ;
    END
  END o[8]
  PIN o[90]
    DIRECTION OUTPUT ;
    USE SIGNAL ;
    PORT
      LAYER M4 ;
        RECT  0 16.416 0.084 16.44 ;
    END
  END o[90]
  PIN o[91]
    DIRECTION OUTPUT ;
    USE SIGNAL ;
    PORT
      LAYER M4 ;
        RECT  0 16.56 0.084 16.584 ;
    END
  END o[91]
  PIN o[92]
    DIRECTION OUTPUT ;
    USE SIGNAL ;
    PORT
      LAYER M4 ;
        RECT  0 16.752 0.084 16.776 ;
    END
  END o[92]
  PIN o[93]
    DIRECTION OUTPUT ;
    USE SIGNAL ;
    PORT
      LAYER M4 ;
        RECT  0 16.944 0.084 16.968 ;
    END
  END o[93]
  PIN o[94]
    DIRECTION OUTPUT ;
    USE SIGNAL ;
    PORT
      LAYER M4 ;
        RECT  0 17.088 0.084 17.112 ;
    END
  END o[94]
  PIN o[95]
    DIRECTION OUTPUT ;
    USE SIGNAL ;
    PORT
      LAYER M4 ;
        RECT  0 17.28 0.084 17.304 ;
    END
  END o[95]
  PIN o[96]
    DIRECTION OUTPUT ;
    USE SIGNAL ;
    PORT
      LAYER M4 ;
        RECT  0 17.424 0.084 17.448 ;
    END
  END o[96]
  PIN o[97]
    DIRECTION OUTPUT ;
    USE SIGNAL ;
    PORT
      LAYER M4 ;
        RECT  0 17.616 0.084 17.64 ;
    END
  END o[97]
  PIN o[98]
    DIRECTION OUTPUT ;
    USE SIGNAL ;
    PORT
      LAYER M4 ;
        RECT  0 17.76 0.084 17.784 ;
    END
  END o[98]
  PIN o[99]
    DIRECTION OUTPUT ;
    USE SIGNAL ;
    PORT
      LAYER M4 ;
        RECT  0 17.952 0.084 17.976 ;
    END
  END o[99]
  PIN o[9]
    DIRECTION OUTPUT ;
    USE SIGNAL ;
    PORT
      LAYER M4 ;
        RECT  0 2.592 0.084 2.616 ;
    END
  END o[9]
  PIN rs
    DIRECTION INPUT ;
    USE SIGNAL ;
    PORT
      LAYER M3 ;
        RECT  16.884 51.802 16.902 51.84 ;
    END
  END rs
  PIN VDD
    DIRECTION INOUT ;
    USE POWER ;
    PORT
      LAYER M5 ;
        RECT  32.292 2.151 32.412 49.689 ;
        RECT  29.592 2.151 29.712 49.689 ;
        RECT  26.892 2.151 27.012 49.689 ;
        RECT  24.192 2.151 24.312 49.689 ;
        RECT  21.492 2.151 21.612 49.689 ;
        RECT  18.792 2.151 18.912 49.689 ;
        RECT  16.092 2.151 16.212 49.689 ;
        RECT  13.392 2.151 13.512 49.689 ;
        RECT  10.692 2.151 10.812 49.689 ;
        RECT  7.992 2.151 8.112 49.689 ;
        RECT  5.292 2.151 5.412 49.689 ;
        RECT  2.592 2.151 2.712 49.689 ;
    END
  END VDD
  PIN VSS
    DIRECTION INOUT ;
    USE GROUND ;
    PORT
      LAYER M5 ;
        RECT  32.1 2.137 32.22 49.703 ;
        RECT  29.4 2.137 29.52 49.703 ;
        RECT  26.7 2.137 26.82 49.703 ;
        RECT  24 2.137 24.12 49.703 ;
        RECT  21.3 2.137 21.42 49.703 ;
        RECT  18.6 2.137 18.72 49.703 ;
        RECT  15.9 2.137 16.02 49.703 ;
        RECT  13.2 2.137 13.32 49.703 ;
        RECT  10.5 2.137 10.62 49.703 ;
        RECT  7.8 2.137 7.92 49.703 ;
        RECT  5.1 2.137 5.22 49.703 ;
        RECT  2.4 2.137 2.52 49.703 ;
    END
  END VSS
  OBS
    LAYER RVTN ;
     RECT  2.16 2.16 34.56 2.295 ;
     RECT  2.16 2.565 34.56 2.835 ;
     RECT  2.16 3.105 34.56 3.375 ;
     RECT  2.16 3.645 34.56 3.915 ;
     RECT  2.16 4.185 34.56 4.455 ;
     RECT  2.16 4.725 34.56 4.995 ;
     RECT  2.16 5.265 34.56 5.535 ;
     RECT  2.16 5.805 34.56 6.075 ;
     RECT  2.16 6.345 34.56 6.615 ;
     RECT  2.16 6.885 34.56 7.155 ;
     RECT  2.16 7.425 34.56 7.695 ;
     RECT  2.16 7.965 34.56 8.235 ;
     RECT  2.16 8.505 34.56 8.775 ;
     RECT  2.16 9.045 34.56 9.315 ;
     RECT  2.16 9.585 34.56 9.855 ;
     RECT  2.16 10.125 34.56 10.395 ;
     RECT  2.16 10.665 34.56 10.935 ;
     RECT  2.16 11.205 34.56 11.475 ;
     RECT  2.16 11.745 34.56 12.015 ;
     RECT  2.16 12.285 34.56 12.555 ;
     RECT  2.16 12.825 34.56 13.095 ;
     RECT  2.16 13.365 34.56 13.635 ;
     RECT  2.16 13.905 34.56 14.175 ;
     RECT  2.16 14.445 34.56 14.715 ;
     RECT  2.16 14.985 34.56 15.255 ;
     RECT  2.16 15.525 34.56 15.795 ;
     RECT  2.16 16.065 34.56 16.335 ;
     RECT  2.16 16.605 34.56 16.875 ;
     RECT  2.16 17.145 34.56 17.415 ;
     RECT  2.16 17.685 34.56 17.955 ;
     RECT  2.16 18.225 34.56 18.495 ;
     RECT  2.16 18.765 34.56 19.035 ;
     RECT  2.16 19.305 34.56 19.575 ;
     RECT  2.16 19.845 34.56 20.115 ;
     RECT  2.16 20.385 34.56 20.655 ;
     RECT  2.16 20.925 34.56 21.195 ;
     RECT  2.16 21.465 34.56 21.735 ;
     RECT  2.16 22.005 34.56 22.275 ;
     RECT  2.16 22.545 34.56 22.815 ;
     RECT  2.16 23.085 34.56 23.355 ;
     RECT  2.16 23.625 34.56 23.895 ;
     RECT  2.16 24.165 34.56 24.435 ;
     RECT  2.16 24.705 34.56 24.975 ;
     RECT  2.16 25.245 34.56 25.515 ;
     RECT  2.16 25.785 34.56 26.055 ;
     RECT  2.16 26.325 34.56 26.595 ;
     RECT  2.16 26.865 34.56 27.135 ;
     RECT  2.16 27.405 34.56 27.675 ;
     RECT  2.16 27.945 34.56 28.215 ;
     RECT  2.16 28.485 34.56 28.755 ;
     RECT  2.16 29.025 34.56 29.295 ;
     RECT  2.16 29.565 34.56 29.835 ;
     RECT  2.16 30.105 34.56 30.375 ;
     RECT  2.16 30.645 34.56 30.915 ;
     RECT  2.16 31.185 34.56 31.455 ;
     RECT  2.16 31.725 34.56 31.995 ;
     RECT  2.16 32.265 34.56 32.535 ;
     RECT  2.16 32.805 34.56 33.075 ;
     RECT  2.16 33.345 34.56 33.615 ;
     RECT  2.16 33.885 34.56 34.155 ;
     RECT  2.16 34.425 34.56 34.695 ;
     RECT  2.16 34.965 34.56 35.235 ;
     RECT  2.16 35.505 34.56 35.775 ;
     RECT  2.16 36.045 34.56 36.315 ;
     RECT  2.16 36.585 34.56 36.855 ;
     RECT  2.16 37.125 34.56 37.395 ;
     RECT  2.16 37.665 34.56 37.935 ;
     RECT  2.16 38.205 34.56 38.475 ;
     RECT  2.16 38.745 34.56 39.015 ;
     RECT  2.16 39.285 34.56 39.555 ;
     RECT  2.16 39.825 34.56 40.095 ;
     RECT  2.16 40.365 34.56 40.635 ;
     RECT  2.16 40.905 34.56 41.175 ;
     RECT  2.16 41.445 34.56 41.715 ;
     RECT  2.16 41.985 34.56 42.255 ;
     RECT  2.16 42.525 34.56 42.795 ;
     RECT  2.16 43.065 34.56 43.335 ;
     RECT  2.16 43.605 34.56 43.875 ;
     RECT  2.16 44.145 34.56 44.415 ;
     RECT  2.16 44.685 34.56 44.955 ;
     RECT  2.16 45.225 34.56 45.495 ;
     RECT  2.16 45.765 34.56 46.035 ;
     RECT  2.16 46.305 34.56 46.575 ;
     RECT  2.16 46.845 34.56 47.115 ;
     RECT  2.16 47.385 34.56 47.655 ;
     RECT  2.16 47.925 34.56 48.195 ;
     RECT  2.16 48.465 34.56 48.735 ;
     RECT  2.16 49.005 34.56 49.275 ;
     RECT  2.16 49.545 34.56 49.68 ;
    LAYER RVTP ;
     RECT  2.16 2.295 34.56 2.565 ;
     RECT  2.16 2.835 34.56 3.105 ;
     RECT  2.16 3.375 34.56 3.645 ;
     RECT  2.16 3.915 34.56 4.185 ;
     RECT  2.16 4.455 34.56 4.725 ;
     RECT  2.16 4.995 34.56 5.265 ;
     RECT  2.16 5.535 34.56 5.805 ;
     RECT  2.16 6.075 34.56 6.345 ;
     RECT  2.16 6.615 34.56 6.885 ;
     RECT  2.16 7.155 34.56 7.425 ;
     RECT  2.16 7.695 34.56 7.965 ;
     RECT  2.16 8.235 34.56 8.505 ;
     RECT  2.16 8.775 34.56 9.045 ;
     RECT  2.16 9.315 34.56 9.585 ;
     RECT  2.16 9.855 34.56 10.125 ;
     RECT  2.16 10.395 34.56 10.665 ;
     RECT  2.16 10.935 34.56 11.205 ;
     RECT  2.16 11.475 34.56 11.745 ;
     RECT  2.16 12.015 34.56 12.285 ;
     RECT  2.16 12.555 34.56 12.825 ;
     RECT  2.16 13.095 34.56 13.365 ;
     RECT  2.16 13.635 34.56 13.905 ;
     RECT  2.16 14.175 34.56 14.445 ;
     RECT  2.16 14.715 34.56 14.985 ;
     RECT  2.16 15.255 34.56 15.525 ;
     RECT  2.16 15.795 34.56 16.065 ;
     RECT  2.16 16.335 34.56 16.605 ;
     RECT  2.16 16.875 34.56 17.145 ;
     RECT  2.16 17.415 34.56 17.685 ;
     RECT  2.16 17.955 34.56 18.225 ;
     RECT  2.16 18.495 34.56 18.765 ;
     RECT  2.16 19.035 34.56 19.305 ;
     RECT  2.16 19.575 34.56 19.845 ;
     RECT  2.16 20.115 34.56 20.385 ;
     RECT  2.16 20.655 34.56 20.925 ;
     RECT  2.16 21.195 34.56 21.465 ;
     RECT  2.16 21.735 34.56 22.005 ;
     RECT  2.16 22.275 34.56 22.545 ;
     RECT  2.16 22.815 34.56 23.085 ;
     RECT  2.16 23.355 34.56 23.625 ;
     RECT  2.16 23.895 34.56 24.165 ;
     RECT  2.16 24.435 34.56 24.705 ;
     RECT  2.16 24.975 34.56 25.245 ;
     RECT  2.16 25.515 34.56 25.785 ;
     RECT  2.16 26.055 34.56 26.325 ;
     RECT  2.16 26.595 34.56 26.865 ;
     RECT  2.16 27.135 34.56 27.405 ;
     RECT  2.16 27.675 34.56 27.945 ;
     RECT  2.16 28.215 34.56 28.485 ;
     RECT  2.16 28.755 34.56 29.025 ;
     RECT  2.16 29.295 34.56 29.565 ;
     RECT  2.16 29.835 34.56 30.105 ;
     RECT  2.16 30.375 34.56 30.645 ;
     RECT  2.16 30.915 34.56 31.185 ;
     RECT  2.16 31.455 34.56 31.725 ;
     RECT  2.16 31.995 34.56 32.265 ;
     RECT  2.16 32.535 34.56 32.805 ;
     RECT  2.16 33.075 34.56 33.345 ;
     RECT  2.16 33.615 34.56 33.885 ;
     RECT  2.16 34.155 34.56 34.425 ;
     RECT  2.16 34.695 34.56 34.965 ;
     RECT  2.16 35.235 34.56 35.505 ;
     RECT  2.16 35.775 34.56 36.045 ;
     RECT  2.16 36.315 34.56 36.585 ;
     RECT  2.16 36.855 34.56 37.125 ;
     RECT  2.16 37.395 34.56 37.665 ;
     RECT  2.16 37.935 34.56 38.205 ;
     RECT  2.16 38.475 34.56 38.745 ;
     RECT  2.16 39.015 34.56 39.285 ;
     RECT  2.16 39.555 34.56 39.825 ;
     RECT  2.16 40.095 34.56 40.365 ;
     RECT  2.16 40.635 34.56 40.905 ;
     RECT  2.16 41.175 34.56 41.445 ;
     RECT  2.16 41.715 34.56 41.985 ;
     RECT  2.16 42.255 34.56 42.525 ;
     RECT  2.16 42.795 34.56 43.065 ;
     RECT  2.16 43.335 34.56 43.605 ;
     RECT  2.16 43.875 34.56 44.145 ;
     RECT  2.16 44.415 34.56 44.685 ;
     RECT  2.16 44.955 34.56 45.225 ;
     RECT  2.16 45.495 34.56 45.765 ;
     RECT  2.16 46.035 34.56 46.305 ;
     RECT  2.16 46.575 34.56 46.845 ;
     RECT  2.16 47.115 34.56 47.385 ;
     RECT  2.16 47.655 34.56 47.925 ;
     RECT  2.16 48.195 34.56 48.465 ;
     RECT  2.16 48.735 34.56 49.005 ;
     RECT  2.16 49.275 34.56 49.545 ;
    LAYER M1 ;
     RECT  2.16 2.151 34.56 49.689 ;
    LAYER M2 ;
     RECT  0.103 37.026 0.499 37.044 ;
     RECT  0.103 16.506 0.535 16.524 ;
     RECT  1.723 2.646 2.16 2.664 ;
     RECT  0.535 6.786 2.16 6.804 ;
     RECT  1.975 8.136 2.16 8.154 ;
     RECT  0.103 10.026 2.16 10.044 ;
     RECT  0.535 11.286 2.16 11.304 ;
     RECT  0.103 13.536 2.16 13.554 ;
     RECT  0.535 16.506 2.16 17.676 ;
     RECT  0.535 20.97 2.16 21.726 ;
     RECT  0.535 26.136 2.16 26.586 ;
     RECT  0.103 30.618 2.16 30.636 ;
     RECT  0.103 31.896 2.16 31.914 ;
     RECT  0.103 34.056 2.16 34.074 ;
     RECT  0.499 37.026 2.16 37.764 ;
     RECT  0.535 39.186 2.16 39.204 ;
     RECT  0.535 40.41 2.16 40.428 ;
     RECT  0.535 42.156 2.16 43.704 ;
     RECT  0.535 49.554 2.16 49.572 ;
     RECT  2.16 2.151 3.091 49.689 ;
     RECT  3.091 2.106 4.243 49.689 ;
     RECT  4.243 2.07 5.431 49.689 ;
     RECT  5.431 2.034 13.099 49.689 ;
     RECT  13.099 1.926 15.583 49.689 ;
     RECT  15.979 50.706 16.079 50.724 ;
     RECT  15.583 1.881 16.295 49.689 ;
     RECT  16.295 1.926 17.771 49.689 ;
     RECT  17.771 1.998 18.779 49.689 ;
     RECT  18.779 2.106 21.947 49.689 ;
     RECT  21.947 2.151 23.827 49.689 ;
     RECT  23.827 2.034 25.187 49.689 ;
     RECT  25.187 2.151 26.131 49.689 ;
     RECT  26.131 2.034 31.927 49.689 ;
     RECT  31.927 1.962 33.971 49.689 ;
     RECT  33.971 2.034 34.56 49.689 ;
     RECT  34.56 21.708 34.691 33.066 ;
     RECT  34.56 6.588 34.763 19.944 ;
     RECT  34.691 21.708 34.763 32.868 ;
     RECT  34.763 15.84 34.799 19.944 ;
     RECT  34.763 22.896 34.799 32.868 ;
     RECT  34.56 33.93 35.303 37.692 ;
     RECT  34.56 2.034 35.339 5.796 ;
     RECT  34.763 6.588 35.339 10.044 ;
     RECT  34.763 10.908 35.339 11.808 ;
     RECT  34.763 12.906 35.339 15.084 ;
     RECT  34.799 16.038 35.339 19.944 ;
     RECT  34.56 20.7 35.339 20.718 ;
     RECT  34.763 21.708 35.339 22.068 ;
     RECT  34.799 28.26 35.339 32.22 ;
     RECT  35.303 33.93 35.339 36.684 ;
     RECT  34.56 38.646 35.339 48.186 ;
     RECT  35.339 29.916 35.375 32.22 ;
     RECT  35.339 34.164 35.375 34.758 ;
     RECT  35.339 40.338 35.375 41.508 ;
     RECT  35.339 42.264 35.375 45.828 ;
     RECT  35.339 10.908 35.843 10.926 ;
     RECT  35.339 16.038 35.843 17.676 ;
     RECT  35.339 38.646 35.843 39.276 ;
     RECT  35.339 4.5 35.915 5.796 ;
     RECT  35.339 6.588 35.915 9.036 ;
     RECT  35.339 19.35 35.915 19.944 ;
     RECT  34.799 22.896 35.915 27.504 ;
     RECT  35.375 31.266 35.915 32.22 ;
     RECT  35.375 40.338 35.915 41.436 ;
     RECT  35.375 42.264 35.915 43.866 ;
     RECT  35.339 2.034 35.951 3.402 ;
     RECT  35.339 9.828 35.951 10.044 ;
     RECT  35.339 12.906 35.951 13.662 ;
     RECT  35.915 22.896 35.951 24.93 ;
     RECT  35.339 28.566 35.951 29.124 ;
     RECT  35.915 32.202 35.951 32.22 ;
     RECT  35.375 34.47 35.951 34.758 ;
     RECT  35.339 35.55 35.951 36.684 ;
     RECT  35.303 37.476 35.951 37.692 ;
     RECT  35.843 38.646 35.951 38.664 ;
     RECT  35.915 40.806 35.951 41.004 ;
     RECT  35.915 42.264 35.951 43.668 ;
     RECT  35.375 44.964 35.951 45.828 ;
     RECT  35.951 42.876 35.987 43.434 ;
     RECT  35.915 26.028 36.023 27.504 ;
     RECT  35.951 36.666 36.023 36.684 ;
     RECT  35.951 2.106 36.563 3.402 ;
     RECT  35.915 4.5 36.563 5.058 ;
     RECT  36.023 26.874 36.563 27.504 ;
     RECT  36.563 2.646 36.599 3.402 ;
     RECT  35.951 9.828 36.599 9.918 ;
     RECT  35.951 23.436 36.599 24.93 ;
     RECT  35.339 46.62 36.599 47.412 ;
     RECT  36.599 3.384 36.635 3.402 ;
     RECT  36.563 4.5 36.635 4.518 ;
     RECT  35.915 7.2 36.635 8.334 ;
     RECT  36.599 9.828 36.635 9.846 ;
     RECT  35.339 11.79 36.635 11.808 ;
     RECT  35.339 15.066 36.635 15.084 ;
     RECT  35.843 16.038 36.635 17.1 ;
     RECT  35.339 18.576 36.635 18.594 ;
     RECT  35.915 19.35 36.635 19.872 ;
     RECT  35.339 21.708 36.635 21.726 ;
     RECT  36.599 23.436 36.635 24.264 ;
     RECT  36.023 26.028 36.635 26.046 ;
     RECT  36.563 27.486 36.635 27.504 ;
     RECT  35.951 28.566 36.635 28.584 ;
     RECT  35.375 29.916 36.635 30.168 ;
     RECT  35.915 31.266 36.635 31.284 ;
     RECT  35.951 34.506 36.635 34.758 ;
     RECT  35.951 35.55 36.635 35.568 ;
     RECT  35.951 40.986 36.635 41.004 ;
     RECT  35.951 45.27 36.635 45.828 ;
     RECT  36.599 46.62 36.635 46.638 ;
     RECT  36.599 47.394 36.635 47.412 ;
     RECT  35.339 48.168 36.635 48.186 ;
    LAYER M3 ;
     RECT  36.612 1.051 36.63 1.243 ;
     RECT  3.384 1.243 3.402 1.387 ;
     RECT  36.576 1.243 36.63 1.387 ;
     RECT  3.384 1.387 3.906 1.579 ;
     RECT  1.728 1.051 1.746 1.771 ;
     RECT  3.06 1.579 3.906 1.771 ;
     RECT  35.244 1.579 35.262 1.771 ;
     RECT  35.244 1.771 35.334 1.915 ;
     RECT  13.104 1.921 13.122 1.957 ;
     RECT  15.588 1.876 16.29 1.993 ;
     RECT  4.86 1.915 4.878 2.029 ;
     RECT  15.588 1.993 16.902 2.029 ;
     RECT  33.948 1.957 33.966 2.029 ;
     RECT  35.172 1.915 35.334 2.029 ;
     RECT  36.54 1.387 36.63 2.029 ;
     RECT  13.104 1.957 14.382 2.059 ;
     RECT  1.728 1.771 3.906 2.065 ;
     RECT  4.86 2.029 5.454 2.065 ;
     RECT  13.104 2.059 14.418 2.065 ;
     RECT  21.456 2.011 21.474 2.101 ;
     RECT  9.792 2.101 9.81 2.143 ;
     RECT  18.756 1.993 18.774 2.143 ;
     RECT  21.456 2.101 21.942 2.143 ;
     RECT  23.832 2.029 23.85 2.143 ;
     RECT  26.136 2.029 26.154 2.143 ;
     RECT  29.556 2.101 29.574 2.143 ;
     RECT  31.932 1.957 31.95 2.143 ;
     RECT  7.56 2.101 8.046 2.191 ;
     RECT  13.104 2.065 14.742 2.191 ;
     RECT  15.552 2.029 16.902 2.191 ;
     RECT  17.748 1.921 17.766 2.191 ;
     RECT  18.615 2.143 18.774 2.191 ;
     RECT  22.86 2.059 22.878 2.191 ;
     RECT  23.832 2.143 24.105 2.191 ;
     RECT  25.164 2.029 25.182 2.191 ;
     RECT  28.224 2.101 28.242 2.191 ;
     RECT  31.932 2.143 32.205 2.191 ;
     RECT  1.728 2.065 5.526 2.227 ;
     RECT  6.768 2.065 6.786 2.227 ;
     RECT  9.792 2.143 10.605 2.227 ;
     RECT  21.315 2.143 21.942 2.227 ;
     RECT  22.68 2.191 22.878 2.227 ;
     RECT  23.832 2.191 25.182 2.227 ;
     RECT  29.415 2.143 29.574 2.227 ;
     RECT  31.356 2.191 32.205 2.227 ;
     RECT  26.136 2.143 26.805 2.251 ;
     RECT  29.124 2.227 29.574 2.251 ;
     RECT  30.78 2.227 32.205 2.251 ;
     RECT  7.56 2.191 8.154 2.263 ;
     RECT  9.432 2.227 10.605 2.263 ;
     RECT  11.628 2.227 11.646 2.263 ;
     RECT  21.312 2.227 25.182 2.263 ;
     RECT  26.1 2.251 26.805 2.263 ;
     RECT  1.728 2.227 6.786 2.299 ;
     RECT  7.56 2.263 10.605 2.299 ;
     RECT  21.312 2.263 26.805 2.299 ;
     RECT  21.024 2.299 26.805 2.335 ;
     RECT  27.756 2.191 28.242 2.335 ;
     RECT  29.124 2.251 32.205 2.335 ;
     RECT  33.084 2.029 33.966 2.371 ;
     RECT  1.728 2.299 10.605 2.413 ;
     RECT  13.104 2.191 18.774 2.413 ;
     RECT  21.024 2.335 32.238 2.413 ;
     RECT  32.976 2.371 33.966 2.413 ;
     RECT  1.728 2.413 10.797 2.461 ;
     RECT  11.556 2.263 12.006 2.461 ;
     RECT  13.104 2.413 18.897 2.461 ;
     RECT  21.024 2.413 33.966 2.461 ;
     RECT  13.104 2.461 19.782 2.533 ;
     RECT  13.104 2.533 20.214 2.605 ;
     RECT  21.024 2.461 34.29 2.605 ;
     RECT  13.104 2.605 34.29 2.621 ;
     RECT  1.728 2.461 12.006 2.641 ;
     RECT  1.728 2.641 12.15 2.669 ;
     RECT  2.304 2.669 12.15 2.731 ;
     RECT  13.104 2.621 33.966 2.731 ;
     RECT  2.304 2.731 33.966 2.795 ;
     RECT  35.172 2.029 36.63 2.957 ;
     RECT  36.288 2.957 36.63 3.245 ;
     RECT  35.172 2.957 35.334 3.307 ;
     RECT  2.304 2.795 25.686 3.541 ;
     RECT  26.496 2.795 33.966 3.541 ;
     RECT  0.108 3.787 0.126 3.917 ;
     RECT  2.304 3.541 33.966 3.991 ;
     RECT  1.152 3.979 1.17 4.205 ;
     RECT  35.136 3.307 35.334 4.253 ;
     RECT  2.304 3.991 34.29 4.415 ;
     RECT  34.236 4.415 34.29 4.487 ;
     RECT  36.54 3.245 36.63 4.523 ;
     RECT  34.236 4.487 34.254 4.541 ;
     RECT  35.244 4.253 35.334 4.987 ;
     RECT  36.54 4.523 36.558 4.987 ;
     RECT  35.244 4.987 36.558 4.991 ;
     RECT  2.304 4.415 33.39 5.161 ;
     RECT  2.304 5.161 33.678 5.233 ;
     RECT  2.268 5.233 33.678 5.341 ;
     RECT  2.268 5.341 33.822 5.357 ;
     RECT  2.304 5.357 33.822 5.431 ;
     RECT  35.28 4.991 36.558 5.549 ;
     RECT  35.28 5.549 36.486 5.603 ;
     RECT  2.304 5.431 34.182 5.881 ;
     RECT  2.304 5.881 34.362 6.449 ;
     RECT  35.316 5.603 36.486 6.523 ;
     RECT  35.316 6.523 36.63 6.845 ;
     RECT  35.316 6.845 35.37 7.051 ;
     RECT  0.54 6.781 0.558 7.085 ;
     RECT  35.28 7.051 35.37 7.151 ;
     RECT  35.316 7.151 35.37 7.259 ;
     RECT  2.304 6.449 33.75 7.321 ;
     RECT  2.304 7.321 33.93 7.385 ;
     RECT  33.48 7.385 33.93 7.469 ;
     RECT  35.352 7.259 35.37 7.565 ;
     RECT  36.576 6.845 36.63 7.867 ;
     RECT  2.304 7.385 32.67 8.059 ;
     RECT  1.98 8.059 32.67 8.159 ;
     RECT  33.48 7.469 33.498 8.203 ;
     RECT  34.344 8.041 34.362 8.203 ;
     RECT  2.304 8.159 32.67 8.239 ;
     RECT  33.48 8.203 34.362 8.239 ;
     RECT  0.108 8.395 0.126 8.525 ;
     RECT  2.304 8.239 34.362 9.005 ;
     RECT  35.892 7.867 36.63 9.067 ;
     RECT  2.304 9.005 34.254 9.113 ;
     RECT  35.316 9.067 36.63 9.383 ;
     RECT  0.144 9.403 0.162 9.581 ;
     RECT  2.304 9.113 33.714 9.739 ;
     RECT  2.268 9.739 33.714 9.869 ;
     RECT  2.268 9.869 33.678 9.959 ;
     RECT  35.928 9.383 36.63 10.049 ;
     RECT  36.432 10.049 36.63 10.157 ;
     RECT  0.108 10.021 0.126 10.301 ;
     RECT  34.74 10.267 34.758 10.391 ;
     RECT  36.612 10.157 36.63 10.733 ;
     RECT  2.304 9.959 33.678 10.741 ;
     RECT  2.304 10.741 33.75 10.769 ;
     RECT  35.172 10.459 35.334 10.795 ;
     RECT  31.248 10.769 33.75 10.831 ;
     RECT  35.172 10.795 35.838 10.931 ;
     RECT  31.248 10.831 33.822 10.939 ;
     RECT  31.248 10.939 33.858 11.012 ;
     RECT  31.248 11.012 33.822 11.165 ;
     RECT  31.248 11.165 33.642 11.237 ;
     RECT  2.304 10.769 30.51 11.309 ;
     RECT  0.54 11.281 0.558 11.501 ;
     RECT  36.288 11.371 36.306 11.501 ;
     RECT  35.172 10.931 35.334 11.543 ;
     RECT  7.524 11.309 30.51 11.551 ;
     RECT  31.248 11.237 33.606 11.551 ;
     RECT  2.304 11.309 6.786 12.091 ;
     RECT  7.524 11.551 33.606 12.091 ;
     RECT  36.504 11.659 36.63 12.269 ;
     RECT  36.504 12.269 36.558 12.317 ;
     RECT  34.74 11.803 34.758 12.331 ;
     RECT  2.304 12.091 33.606 12.361 ;
     RECT  34.74 12.331 35.334 12.551 ;
     RECT  2.304 12.361 33.678 12.631 ;
     RECT  35.316 12.551 35.334 12.901 ;
     RECT  36.504 12.317 36.522 12.901 ;
     RECT  2.304 12.631 34.182 13.019 ;
     RECT  35.316 12.901 36.522 13.339 ;
     RECT  35.316 13.339 36.63 13.469 ;
     RECT  0.108 13.531 0.126 13.709 ;
     RECT  2.304 13.019 33.822 13.829 ;
     RECT  35.316 13.469 36.558 14.045 ;
     RECT  2.304 13.829 33.426 14.099 ;
     RECT  34.2 13.945 34.218 14.099 ;
     RECT  1.152 14.107 1.17 14.237 ;
     RECT  36.54 14.045 36.558 14.237 ;
     RECT  35.316 14.045 35.334 14.513 ;
     RECT  2.304 14.099 32.742 14.881 ;
     RECT  2.304 14.881 32.778 14.917 ;
     RECT  36.612 14.683 36.63 15.067 ;
     RECT  2.304 14.917 33.822 15.179 ;
     RECT  34.74 14.539 34.758 15.251 ;
     RECT  36.54 15.067 36.63 15.739 ;
     RECT  0.144 15.787 0.162 15.917 ;
     RECT  34.776 15.835 34.794 15.917 ;
     RECT  2.34 15.179 33.822 15.989 ;
     RECT  2.34 15.989 33.21 16.025 ;
     RECT  2.34 16.025 33.138 16.075 ;
     RECT  2.304 16.075 33.138 16.141 ;
     RECT  36.468 15.739 36.63 16.141 ;
     RECT  34.596 16.033 34.758 16.214 ;
     RECT  2.268 16.141 33.138 16.253 ;
     RECT  34.596 16.214 34.686 16.295 ;
     RECT  0.108 16.501 0.126 16.589 ;
     RECT  2.304 16.253 33.138 16.843 ;
     RECT  33.984 16.411 34.002 16.843 ;
     RECT  35.928 16.141 36.63 17.105 ;
     RECT  2.304 16.843 34.002 17.179 ;
     RECT  35.928 17.105 36.594 17.213 ;
     RECT  35.928 17.213 36.558 17.275 ;
     RECT  2.304 17.179 34.362 17.339 ;
     RECT  35.244 17.275 36.558 17.411 ;
     RECT  2.415 17.339 34.362 17.519 ;
     RECT  2.415 17.519 33.57 17.609 ;
     RECT  34.344 17.519 34.362 17.609 ;
     RECT  2.415 17.609 2.97 17.681 ;
     RECT  35.316 17.411 36.558 17.681 ;
     RECT  0.54 17.041 0.558 17.789 ;
     RECT  2.415 17.681 2.898 17.879 ;
     RECT  2.415 17.879 2.79 17.987 ;
     RECT  35.316 17.681 35.334 18.023 ;
     RECT  2.415 17.987 2.754 18.091 ;
     RECT  36.54 17.681 36.558 18.125 ;
     RECT  3.708 17.609 33.57 18.149 ;
     RECT  3.744 18.149 33.57 18.301 ;
     RECT  3.744 18.301 33.606 18.535 ;
     RECT  3.744 18.535 34.218 18.841 ;
     RECT  2.304 18.091 2.754 19.003 ;
     RECT  3.744 18.841 34.362 19.003 ;
     RECT  2.304 19.003 34.362 19.103 ;
     RECT  35.316 19.291 35.334 19.337 ;
     RECT  36.612 18.475 36.63 19.483 ;
     RECT  36.54 19.483 36.63 19.819 ;
     RECT  35.856 19.819 36.63 19.877 ;
     RECT  35.856 19.877 35.91 19.949 ;
     RECT  35.856 19.949 35.874 19.997 ;
     RECT  2.304 19.103 33.822 20.191 ;
     RECT  2.304 20.191 34.038 20.345 ;
     RECT  0.144 20.395 0.162 20.525 ;
     RECT  35.316 20.683 35.334 20.723 ;
     RECT  2.304 20.345 33.822 20.759 ;
     RECT  36.54 20.827 36.558 20.923 ;
     RECT  36.54 20.923 36.63 21.005 ;
     RECT  6.984 20.759 33.822 21.469 ;
     RECT  6.984 21.469 33.966 21.533 ;
     RECT  18.576 21.533 33.966 21.541 ;
     RECT  2.304 20.759 6.246 21.547 ;
     RECT  6.984 21.533 17.802 21.547 ;
     RECT  35.244 21.355 35.262 21.803 ;
     RECT  36.612 21.005 36.63 21.917 ;
     RECT  35.316 22.027 35.334 22.073 ;
     RECT  2.304 21.547 17.802 22.199 ;
     RECT  0.54 20.965 0.558 22.253 ;
     RECT  3.42 22.199 17.802 22.315 ;
     RECT  18.576 21.541 34.434 22.315 ;
     RECT  2.304 22.199 2.697 22.621 ;
     RECT  3.42 22.315 34.434 22.699 ;
     RECT  2.268 22.621 2.697 22.733 ;
     RECT  3.42 22.699 34.758 22.811 ;
     RECT  36.288 22.363 36.306 22.891 ;
     RECT  2.304 22.733 2.697 22.981 ;
     RECT  3.42 22.811 34.182 22.981 ;
     RECT  35.928 22.891 36.306 23.419 ;
     RECT  0.324 23.419 0.342 23.563 ;
     RECT  0.108 23.563 0.342 23.597 ;
     RECT  2.304 22.981 34.182 23.629 ;
     RECT  0.108 23.597 0.162 23.693 ;
     RECT  35.136 23.035 35.154 23.693 ;
     RECT  35.928 23.419 36.63 23.789 ;
     RECT  2.304 23.629 34.218 24.235 ;
     RECT  2.268 24.235 34.218 24.359 ;
     RECT  0.144 23.693 0.162 24.461 ;
     RECT  2.304 24.359 34.218 24.467 ;
     RECT  36.432 23.789 36.63 24.511 ;
     RECT  35.928 24.511 36.63 24.605 ;
     RECT  2.304 24.467 3.798 24.629 ;
     RECT  2.304 24.629 3.762 24.809 ;
     RECT  3.564 24.809 3.762 25.411 ;
     RECT  4.536 24.467 34.218 25.411 ;
     RECT  35.28 25.099 35.334 25.435 ;
     RECT  36.54 24.605 36.63 25.435 ;
     RECT  2.412 24.809 2.754 25.531 ;
     RECT  3.564 25.411 34.218 25.531 ;
     RECT  2.412 25.531 34.218 25.591 ;
     RECT  0.108 25.531 0.126 25.661 ;
     RECT  35.28 25.435 36.63 25.771 ;
     RECT  35.136 25.771 36.63 25.853 ;
     RECT  2.412 25.591 34.362 25.861 ;
     RECT  2.304 25.861 34.362 25.997 ;
     RECT  35.28 25.853 36.63 26.051 ;
     RECT  33.804 25.997 34.362 26.159 ;
     RECT  2.304 25.997 32.886 26.519 ;
     RECT  2.34 26.519 32.886 26.761 ;
     RECT  35.28 26.051 36.306 26.827 ;
     RECT  2.34 26.761 32.958 26.833 ;
     RECT  0.54 26.131 0.558 26.861 ;
     RECT  35.28 26.827 36.558 26.905 ;
     RECT  0.108 26.971 0.126 27.101 ;
     RECT  2.34 26.833 33.138 27.211 ;
     RECT  34.02 26.159 34.362 27.211 ;
     RECT  2.34 27.211 34.362 27.301 ;
     RECT  35.244 26.905 36.558 27.481 ;
     RECT  35.244 27.481 36.63 27.533 ;
     RECT  2.304 27.301 34.362 27.985 ;
     RECT  35.244 27.533 36.018 27.985 ;
     RECT  2.304 27.985 36.018 28.205 ;
     RECT  35.316 28.205 36.018 28.507 ;
     RECT  35.316 28.507 36.63 28.541 ;
     RECT  35.928 28.541 36.63 28.589 ;
     RECT  2.304 28.205 34.218 28.733 ;
     RECT  35.928 28.589 36.018 28.877 ;
     RECT  35.928 28.877 35.946 29.213 ;
     RECT  2.304 28.733 34.182 29.219 ;
     RECT  3.924 29.219 34.182 29.405 ;
     RECT  2.304 29.219 3.15 29.549 ;
     RECT  35.316 29.515 35.334 29.561 ;
     RECT  36.612 29.707 36.63 30.173 ;
     RECT  3.924 29.405 34.074 30.181 ;
     RECT  3.924 30.181 34.182 30.221 ;
     RECT  34.056 30.221 34.182 30.235 ;
     RECT  2.304 29.549 3.114 30.343 ;
     RECT  3.924 30.221 33.174 30.343 ;
     RECT  36.54 30.427 36.558 30.605 ;
     RECT  35.352 30.883 35.37 30.907 ;
     RECT  35.316 30.907 35.37 30.983 ;
     RECT  2.304 30.343 33.174 30.991 ;
     RECT  34.056 30.235 34.218 30.991 ;
     RECT  36.612 31.051 36.63 31.289 ;
     RECT  2.304 30.991 34.218 31.421 ;
     RECT  2.376 31.421 34.218 31.531 ;
     RECT  35.352 30.983 35.37 31.579 ;
     RECT  2.376 31.531 34.434 31.721 ;
     RECT  34.416 31.721 34.434 31.793 ;
     RECT  35.352 31.579 35.91 31.915 ;
     RECT  2.376 31.721 33.57 31.919 ;
     RECT  0.108 30.613 0.126 31.949 ;
     RECT  34.668 31.915 35.91 32.141 ;
     RECT  2.376 31.919 33.21 32.305 ;
     RECT  2.304 32.305 33.21 32.431 ;
     RECT  2.268 32.431 33.21 32.477 ;
     RECT  35.928 32.197 35.946 32.477 ;
     RECT  34.668 32.141 34.794 32.539 ;
     RECT  34.164 32.539 34.794 32.729 ;
     RECT  2.304 32.477 33.21 32.809 ;
     RECT  34.668 32.729 34.794 33.071 ;
     RECT  36.468 32.971 36.486 33.115 ;
     RECT  36.468 33.115 36.558 33.293 ;
     RECT  36.54 33.293 36.558 33.355 ;
     RECT  2.304 32.809 33.57 33.511 ;
     RECT  2.304 33.511 33.642 33.889 ;
     RECT  35.316 33.643 35.334 33.953 ;
     RECT  2.304 33.889 33.678 33.961 ;
     RECT  2.304 33.961 33.966 34.115 ;
     RECT  3.744 34.115 33.966 34.187 ;
     RECT  0.108 34.051 0.126 34.349 ;
     RECT  35.352 34.159 35.37 34.465 ;
     RECT  36.54 33.355 36.63 34.465 ;
     RECT  35.352 34.465 36.63 34.763 ;
     RECT  35.352 34.763 36.558 34.829 ;
     RECT  2.304 34.115 2.934 34.861 ;
     RECT  3.744 34.187 33.678 34.861 ;
     RECT  35.316 34.987 35.334 35.033 ;
     RECT  2.304 34.861 33.678 35.041 ;
     RECT  2.304 35.041 33.714 35.239 ;
     RECT  36.468 34.829 36.558 35.515 ;
     RECT  34.776 35.509 34.794 35.693 ;
     RECT  2.304 35.239 33.786 35.851 ;
     RECT  0.108 35.755 0.126 35.885 ;
     RECT  36.468 35.515 36.63 35.885 ;
     RECT  2.304 35.851 34.434 36.041 ;
     RECT  36.468 35.885 36.558 36.085 ;
     RECT  35.928 36.085 36.558 36.331 ;
     RECT  2.304 36.041 33.858 36.383 ;
     RECT  35.316 36.331 36.558 37.051 ;
     RECT  0.108 37.021 0.126 37.085 ;
     RECT  35.28 37.051 36.558 37.121 ;
     RECT  2.304 36.383 33.678 37.399 ;
     RECT  35.892 37.121 36.558 37.421 ;
     RECT  2.304 37.399 34.29 37.531 ;
     RECT  1.98 37.531 34.29 37.661 ;
     RECT  0.504 37.471 0.558 37.757 ;
     RECT  35.892 37.421 35.946 37.757 ;
     RECT  2.304 37.661 34.29 37.901 ;
     RECT  2.376 37.901 34.29 38.173 ;
     RECT  0.504 37.757 0.522 38.237 ;
     RECT  2.376 38.173 34.434 38.399 ;
     RECT  35.928 37.757 35.946 38.443 ;
     RECT  2.376 38.399 34.362 38.641 ;
     RECT  35.928 38.443 36.306 38.779 ;
     RECT  35.928 38.779 36.558 38.923 ;
     RECT  2.304 38.641 34.362 38.957 ;
     RECT  35.82 38.923 36.558 39.019 ;
     RECT  35.352 39.019 36.558 39.067 ;
     RECT  35.316 39.067 36.558 39.281 ;
     RECT  0.54 39.181 0.558 39.437 ;
     RECT  2.415 38.957 34.362 39.865 ;
     RECT  2.415 39.865 34.434 39.931 ;
     RECT  2.304 39.931 34.434 40.163 ;
     RECT  35.316 39.281 35.37 40.333 ;
     RECT  36.432 39.281 36.558 40.333 ;
     RECT  35.316 40.333 36.558 40.433 ;
     RECT  0.54 40.405 0.558 40.493 ;
     RECT  2.304 40.163 34.362 40.559 ;
     RECT  35.352 40.433 36.558 40.795 ;
     RECT  2.304 40.559 34.038 40.829 ;
     RECT  35.352 40.795 36.63 41.009 ;
     RECT  0.144 41.179 0.162 41.309 ;
     RECT  2.415 40.829 34.038 41.467 ;
     RECT  35.352 41.009 36.558 41.501 ;
     RECT  36.504 41.501 36.558 41.549 ;
     RECT  2.415 41.467 34.182 41.611 ;
     RECT  35.352 41.501 35.37 41.611 ;
     RECT  2.304 41.611 34.182 41.639 ;
     RECT  35.316 41.611 35.37 41.837 ;
     RECT  36.504 41.549 36.522 42.173 ;
     RECT  2.304 41.639 33.894 42.529 ;
     RECT  2.304 42.529 33.93 42.799 ;
     RECT  34.668 42.331 34.686 42.799 ;
     RECT  2.304 42.799 34.686 43.003 ;
     RECT  35.82 42.259 35.982 43.003 ;
     RECT  2.304 43.003 35.982 43.133 ;
     RECT  35.352 43.133 35.982 43.867 ;
     RECT  0.54 42.151 0.558 44.045 ;
     RECT  2.304 43.133 34.362 44.149 ;
     RECT  35.316 43.867 35.982 44.149 ;
     RECT  2.304 44.149 35.982 44.249 ;
     RECT  2.415 44.249 35.982 44.573 ;
     RECT  35.928 44.573 35.982 44.587 ;
     RECT  2.415 44.573 34.794 44.879 ;
     RECT  2.415 44.879 33.678 44.915 ;
     RECT  35.928 44.587 36.558 45.019 ;
     RECT  2.415 44.915 33.39 45.023 ;
     RECT  34.74 44.879 34.794 45.257 ;
     RECT  2.415 45.023 5.922 45.391 ;
     RECT  35.928 45.019 36.63 45.437 ;
     RECT  6.696 45.023 33.39 45.733 ;
     RECT  6.696 45.733 33.678 45.769 ;
     RECT  2.304 45.391 5.922 45.805 ;
     RECT  6.696 45.769 34.218 45.805 ;
     RECT  2.304 45.805 34.218 46.075 ;
     RECT  36.612 45.437 36.63 46.411 ;
     RECT  2.304 46.075 34.254 46.499 ;
     RECT  33.948 46.499 34.254 46.543 ;
     RECT  35.316 45.547 35.334 46.543 ;
     RECT  2.304 46.499 33.03 46.589 ;
     RECT  33.948 46.543 35.334 46.589 ;
     RECT  2.304 46.589 32.922 46.939 ;
     RECT  1.98 46.939 32.922 47.069 ;
     RECT  35.28 46.589 35.334 47.077 ;
     RECT  36.576 46.411 36.63 47.077 ;
     RECT  35.28 47.077 36.63 47.117 ;
     RECT  0.144 47.131 0.162 47.309 ;
     RECT  33.948 46.589 34.254 47.309 ;
     RECT  2.304 47.069 32.922 47.419 ;
     RECT  35.28 47.117 35.37 47.453 ;
     RECT  35.28 47.453 35.334 47.611 ;
     RECT  34.74 47.611 35.334 47.651 ;
     RECT  2.304 47.419 33.102 47.695 ;
     RECT  2.304 47.695 33.138 47.759 ;
     RECT  2.34 47.759 2.697 47.849 ;
     RECT  35.316 47.651 35.334 47.885 ;
     RECT  3.42 47.759 33.138 48.001 ;
     RECT  3.42 48.001 33.498 48.119 ;
     RECT  3.96 48.119 33.498 48.163 ;
     RECT  36.612 47.117 36.63 48.191 ;
     RECT  3.96 48.163 33.57 48.263 ;
     RECT  4.14 48.263 33.57 48.299 ;
     RECT  4.14 48.299 33.138 48.389 ;
     RECT  4.896 48.389 33.066 48.965 ;
     RECT  20.664 48.965 33.066 49.001 ;
     RECT  22.788 49.001 33.066 49.199 ;
     RECT  22.896 49.199 32.958 49.229 ;
     RECT  20.664 49.001 21.978 49.235 ;
     RECT  4.896 48.965 19.854 49.271 ;
     RECT  4.14 48.389 4.158 49.307 ;
     RECT  7.092 49.271 19.854 49.343 ;
     RECT  4.896 49.271 6.138 49.351 ;
     RECT  7.164 49.343 11.61 49.373 ;
     RECT  4.464 49.351 6.138 49.379 ;
     RECT  7.164 49.373 9.774 49.379 ;
     RECT  2.415 47.849 2.697 49.427 ;
     RECT  12.78 49.343 19.854 49.427 ;
     RECT  7.416 49.379 9.774 49.469 ;
     RECT  10.515 49.373 11.61 49.469 ;
     RECT  12.78 49.427 18.774 49.469 ;
     RECT  19.584 49.427 19.854 49.469 ;
     RECT  22.896 49.229 30.258 49.469 ;
     RECT  31.104 49.229 32.958 49.469 ;
     RECT  4.464 49.379 5.742 49.505 ;
     RECT  10.515 49.469 11.25 49.505 ;
     RECT  12.78 49.469 14.382 49.505 ;
     RECT  19.584 49.469 19.602 49.505 ;
     RECT  22.896 49.469 22.914 49.505 ;
     RECT  23.796 49.469 25.83 49.505 ;
     RECT  26.715 49.469 29.505 49.505 ;
     RECT  32.115 49.469 32.958 49.505 ;
     RECT  15.192 49.469 17.442 49.517 ;
     RECT  18.468 49.469 18.774 49.517 ;
     RECT  20.988 49.235 21.978 49.517 ;
     RECT  24.015 49.505 25.83 49.517 ;
     RECT  26.715 49.505 27.342 49.517 ;
     RECT  4.464 49.505 5.274 49.541 ;
     RECT  7.416 49.469 7.905 49.541 ;
     RECT  12.78 49.505 13.305 49.541 ;
     RECT  14.364 49.505 14.382 49.541 ;
     RECT  15.192 49.517 16.938 49.541 ;
     RECT  5.115 49.541 5.274 49.577 ;
     RECT  7.632 49.541 7.905 49.577 ;
     RECT  15.192 49.541 16.902 49.577 ;
     RECT  18.468 49.517 18.705 49.577 ;
     RECT  21.315 49.517 21.474 49.577 ;
     RECT  25.344 49.517 25.83 49.577 ;
     RECT  28.584 49.505 28.602 49.577 ;
     RECT  32.115 49.505 32.85 49.577 ;
     RECT  25.488 49.577 25.83 49.613 ;
     RECT  2.415 49.427 2.505 49.697 ;
     RECT  5.115 49.577 5.205 49.697 ;
     RECT  7.815 49.577 7.905 49.697 ;
     RECT  10.515 49.505 10.605 49.697 ;
     RECT  13.215 49.541 13.305 49.697 ;
     RECT  15.192 49.577 16.074 49.697 ;
     RECT  18.615 49.577 18.705 49.697 ;
     RECT  21.315 49.577 21.405 49.697 ;
     RECT  24.015 49.517 24.105 49.697 ;
     RECT  26.715 49.517 26.805 49.697 ;
     RECT  29.415 49.505 29.505 49.697 ;
     RECT  32.115 49.577 32.205 49.697 ;
     RECT  0.54 49.549 0.558 49.949 ;
     RECT  16.056 49.697 16.074 50.701 ;
     RECT  15.984 50.701 16.074 50.729 ;
     RECT  15.192 49.697 15.21 51.821 ;
     RECT  15.984 50.729 16.002 51.821 ;
     RECT  16.884 49.577 16.902 51.821 ;
    LAYER M4 ;
     RECT  0.06 1.056 0.227 48.936 ;
     RECT  0.06 49.92 0.569 49.944 ;
     RECT  0.227 1.056 1.757 47.976 ;
     RECT  1.757 1.248 2.408 47.976 ;
     RECT  2.408 1.248 2.512 49.692 ;
     RECT  2.512 1.248 2.704 49.422 ;
     RECT  2.704 17.424 2.729 20.808 ;
     RECT  2.704 23.04 2.729 29.544 ;
     RECT  2.729 17.424 2.765 18.6 ;
     RECT  2.704 30.576 2.765 47.976 ;
     RECT  2.704 8.496 2.801 16.344 ;
     RECT  2.765 17.952 2.801 18.6 ;
     RECT  2.729 23.04 2.837 24.408 ;
     RECT  2.765 30.576 2.837 32.808 ;
     RECT  2.837 23.568 2.873 24.408 ;
     RECT  2.765 34.128 2.873 34.488 ;
     RECT  2.704 1.248 2.945 7.416 ;
     RECT  2.801 8.496 2.945 13.128 ;
     RECT  2.729 25.536 2.981 29.544 ;
     RECT  2.801 14.112 3.053 16.344 ;
     RECT  2.981 25.536 3.089 25.56 ;
     RECT  2.765 35.76 3.107 47.976 ;
     RECT  3.107 36.432 3.395 47.976 ;
     RECT  2.945 1.248 3.413 6.6 ;
     RECT  3.395 36.432 3.629 39.864 ;
     RECT  3.413 1.392 3.773 6.6 ;
     RECT  2.873 34.464 3.805 34.488 ;
     RECT  2.801 18.576 3.841 18.6 ;
     RECT  2.945 9.168 3.877 13.128 ;
     RECT  3.053 14.112 3.877 14.232 ;
     RECT  2.837 30.816 3.877 32.808 ;
     RECT  3.805 34.464 3.877 34.92 ;
     RECT  2.981 27.072 3.884 29.544 ;
     RECT  3.841 17.52 3.913 17.544 ;
     RECT  3.773 1.392 3.917 4.2 ;
     RECT  3.841 18.576 3.949 18.648 ;
     RECT  2.704 21.936 3.949 21.96 ;
     RECT  3.884 27.072 3.985 29.784 ;
     RECT  2.729 19.776 4.019 20.808 ;
     RECT  3.913 8.016 4.025 8.04 ;
     RECT  3.395 40.848 4.129 47.976 ;
     RECT  3.877 9.168 4.165 14.232 ;
     RECT  3.949 21.936 4.165 22.728 ;
     RECT  4.165 21.12 4.201 22.728 ;
     RECT  2.873 23.904 4.201 24.408 ;
     RECT  3.913 17.472 4.237 17.544 ;
     RECT  3.949 18.576 4.237 18.792 ;
     RECT  3.985 26.352 4.309 29.784 ;
     RECT  3.877 30.816 4.309 34.92 ;
     RECT  3.629 36.432 4.309 38.568 ;
     RECT  4.237 17.472 4.405 18.792 ;
     RECT  4.019 19.776 4.405 20.04 ;
     RECT  3.773 5.76 4.501 6.6 ;
     RECT  4.201 21.12 4.525 24.408 ;
     RECT  4.309 26.352 4.597 34.92 ;
     RECT  4.309 36.192 4.597 38.568 ;
     RECT  4.165 8.784 4.813 14.424 ;
     RECT  3.053 15.648 4.813 16.344 ;
     RECT  4.813 8.784 4.885 16.344 ;
     RECT  4.405 17.472 4.885 20.04 ;
     RECT  3.629 39.84 4.885 39.864 ;
     RECT  4.129 40.848 4.885 48.696 ;
     RECT  3.917 1.92 4.889 4.2 ;
     RECT  4.889 2.148 4.993 4.2 ;
     RECT  4.597 26.352 5.065 38.568 ;
     RECT  4.993 2.148 5.108 4.68 ;
     RECT  4.501 5.76 5.108 6.888 ;
     RECT  4.885 8.784 5.108 20.04 ;
     RECT  4.525 21.12 5.108 24.744 ;
     RECT  5.065 26.304 5.108 38.568 ;
     RECT  4.885 39.84 5.108 48.696 ;
     RECT  5.108 2.148 5.212 49.692 ;
     RECT  5.212 2.418 5.404 49.422 ;
     RECT  5.404 35.328 5.465 44.472 ;
     RECT  5.465 35.328 6.473 39.24 ;
     RECT  5.404 2.832 6.613 34.104 ;
     RECT  5.465 40.272 6.685 44.472 ;
     RECT  5.404 48.912 6.793 48.936 ;
     RECT  6.613 2.304 6.812 34.104 ;
     RECT  6.473 35.328 6.812 38.616 ;
     RECT  6.685 40.272 6.853 45.192 ;
     RECT  5.404 46.56 6.853 47.928 ;
     RECT  6.853 40.272 7.009 47.928 ;
     RECT  6.793 48.912 7.441 48.984 ;
     RECT  7.009 39.888 7.657 47.928 ;
     RECT  7.441 48.912 7.657 49.08 ;
     RECT  6.812 2.304 7.669 38.616 ;
     RECT  7.669 2.256 7.693 38.616 ;
     RECT  7.693 2.256 7.808 38.712 ;
     RECT  7.657 39.888 7.808 49.08 ;
     RECT  7.808 2.148 7.912 49.692 ;
     RECT  7.912 2.352 8.104 49.422 ;
     RECT  8.104 2.352 9.637 49.368 ;
     RECT  9.637 2.304 10.508 49.368 ;
     RECT  10.508 2.148 10.612 49.692 ;
     RECT  10.612 2.304 10.804 49.422 ;
     RECT  10.804 2.304 11.699 49.32 ;
     RECT  11.699 2.304 11.837 48.168 ;
     RECT  11.837 2.544 12.131 48.168 ;
     RECT  12.131 7.104 12.877 48.168 ;
     RECT  11.699 49.296 12.877 49.32 ;
     RECT  12.131 2.544 13.093 5.976 ;
     RECT  12.877 7.104 13.093 49.32 ;
     RECT  13.093 2.544 13.165 49.32 ;
     RECT  13.165 2.496 13.208 49.32 ;
     RECT  13.208 2.148 13.312 49.692 ;
     RECT  13.312 2.208 13.504 49.422 ;
     RECT  13.504 2.208 14.389 48.792 ;
     RECT  14.389 2.064 14.749 48.792 ;
     RECT  14.749 2.064 14.785 48.84 ;
     RECT  14.785 2.064 15.325 48.936 ;
     RECT  15.397 51.696 15.635 51.72 ;
     RECT  15.325 2.064 15.908 49.512 ;
     RECT  15.908 2.064 16.012 49.692 ;
     RECT  16.012 2.064 17.029 49.512 ;
     RECT  17.029 2.016 18.608 49.512 ;
     RECT  18.608 2.016 18.712 49.692 ;
     RECT  18.712 2.016 18.785 49.512 ;
     RECT  18.785 2.016 18.904 49.422 ;
     RECT  18.904 2.016 20.977 49.224 ;
     RECT  20.977 2.016 21.308 49.512 ;
     RECT  21.308 2.016 21.412 49.692 ;
     RECT  21.412 2.016 21.485 49.512 ;
     RECT  21.485 2.064 21.989 49.512 ;
     RECT  21.989 2.064 22.565 49.272 ;
     RECT  22.565 47.712 22.637 49.272 ;
     RECT  22.565 2.064 22.889 46.632 ;
     RECT  22.889 2.256 23.605 46.632 ;
     RECT  22.637 47.76 23.605 49.272 ;
     RECT  23.605 2.256 24.008 49.272 ;
     RECT  24.008 2.148 24.112 49.692 ;
     RECT  24.112 2.256 26.708 49.512 ;
     RECT  26.708 2.148 26.812 49.692 ;
     RECT  26.812 2.304 27.353 49.512 ;
     RECT  27.353 2.304 29.408 49.464 ;
     RECT  29.408 2.148 29.512 49.692 ;
     RECT  29.512 2.256 29.704 49.422 ;
     RECT  29.704 2.256 31.093 49.224 ;
     RECT  31.093 2.256 31.097 49.416 ;
     RECT  31.097 2.304 32.108 49.416 ;
     RECT  32.108 2.148 32.212 49.692 ;
     RECT  32.212 2.304 32.404 49.422 ;
     RECT  32.404 36.864 32.531 48.936 ;
     RECT  32.404 2.304 32.573 35.832 ;
     RECT  32.573 6.624 32.681 35.832 ;
     RECT  32.531 36.864 32.681 47.88 ;
     RECT  32.681 8.496 32.861 35.832 ;
     RECT  32.861 8.496 32.933 34.152 ;
     RECT  32.933 8.784 32.969 34.152 ;
     RECT  32.681 36.864 33.041 47.448 ;
     RECT  33.041 47.424 33.113 47.448 ;
     RECT  33.041 36.864 33.221 46.44 ;
     RECT  33.221 36.864 33.365 44.616 ;
     RECT  33.365 44.352 33.653 44.616 ;
     RECT  33.365 36.864 33.689 43.368 ;
     RECT  33.221 45.744 33.689 46.104 ;
     RECT  32.573 2.304 33.941 5.592 ;
     RECT  32.681 6.624 33.941 7.464 ;
     RECT  32.969 8.784 34.189 23.928 ;
     RECT  33.941 2.592 34.193 5.592 ;
     RECT  34.193 2.592 34.265 4.536 ;
     RECT  33.653 44.592 34.729 44.616 ;
     RECT  33.689 45.792 34.729 46.104 ;
     RECT  33.689 36.912 34.765 43.368 ;
     RECT  34.729 44.592 34.765 46.584 ;
     RECT  34.265 2.592 35.161 4.488 ;
     RECT  35.161 1.92 35.233 4.488 ;
     RECT  34.193 5.52 35.233 5.592 ;
     RECT  34.765 36.912 35.269 46.584 ;
     RECT  34.729 47.616 35.269 47.64 ;
     RECT  35.233 1.584 35.305 5.592 ;
     RECT  33.941 6.624 35.305 7.224 ;
     RECT  32.969 25.008 35.305 34.152 ;
     RECT  32.861 35.28 35.305 35.832 ;
     RECT  35.269 36.912 35.305 47.64 ;
     RECT  35.305 1.584 35.341 7.224 ;
     RECT  34.189 8.208 35.341 23.928 ;
     RECT  35.341 1.584 35.917 23.928 ;
     RECT  35.305 25.008 35.917 47.784 ;
     RECT  35.917 1.584 36.529 47.784 ;
     RECT  36.529 1.392 36.565 47.784 ;
     RECT  36.565 1.248 36.601 47.784 ;
     RECT  32.531 48.912 36.601 48.936 ;
     RECT  36.601 1.056 36.684 48.936 ;
    LAYER M5 ;
     RECT  2.4 2.137 2.52 2.151 ;
     RECT  5.1 2.137 5.22 2.151 ;
     RECT  7.8 2.137 7.92 2.151 ;
     RECT  10.5 2.137 10.62 2.151 ;
     RECT  13.2 2.137 13.32 2.151 ;
     RECT  15.9 2.137 16.02 2.151 ;
     RECT  17.04 2.005 17.064 2.151 ;
     RECT  18.6 2.137 18.72 2.151 ;
     RECT  21.3 2.137 21.42 2.151 ;
     RECT  24 2.137 24.12 2.151 ;
     RECT  26.7 2.137 26.82 2.151 ;
     RECT  29.4 2.137 29.52 2.151 ;
     RECT  32.1 2.137 32.22 2.151 ;
     RECT  5.1 2.151 5.412 2.245 ;
     RECT  7.8 2.151 8.112 2.245 ;
     RECT  24 2.151 24.312 2.245 ;
     RECT  24 2.245 24.408 2.293 ;
     RECT  15.9 2.151 17.064 2.485 ;
     RECT  26.7 2.151 27.012 2.533 ;
     RECT  21.3 2.151 21.612 2.677 ;
     RECT  29.4 2.151 29.712 2.677 ;
     RECT  15.12 2.485 17.064 2.723 ;
     RECT  26.7 2.533 27.768 2.819 ;
     RECT  7.68 2.245 8.112 2.821 ;
     RECT  32.1 2.151 32.412 2.821 ;
     RECT  24 2.293 24.696 2.867 ;
     RECT  21.3 2.677 22.2 3.013 ;
     RECT  29.04 2.677 29.712 3.205 ;
     RECT  35.904 3.061 35.928 3.251 ;
     RECT  29.04 3.205 30.072 3.301 ;
     RECT  28.752 3.301 30.072 3.395 ;
     RECT  10.5 2.151 10.812 3.397 ;
     RECT  13.2 2.151 13.512 3.397 ;
     RECT  15.504 2.723 17.064 3.443 ;
     RECT  10.5 3.397 11.4 3.877 ;
     RECT  26.7 2.819 27.384 3.877 ;
     RECT  28.752 3.395 29.712 3.877 ;
     RECT  26.7 3.877 29.712 3.923 ;
     RECT  2.4 2.151 2.712 3.925 ;
     RECT  9.648 3.877 11.4 3.925 ;
     RECT  31.824 2.821 32.412 3.971 ;
     RECT  13.2 3.397 14.28 3.973 ;
     RECT  15.504 3.443 16.392 3.973 ;
     RECT  2.4 3.925 3.336 4.067 ;
     RECT  4.416 2.245 5.412 4.163 ;
     RECT  7.008 2.821 8.52 4.213 ;
     RECT  9.648 3.925 11.688 4.213 ;
     RECT  21.168 3.013 22.2 4.259 ;
     RECT  7.008 4.213 11.688 4.261 ;
     RECT  28.272 3.923 29.712 4.357 ;
     RECT  13.2 3.973 16.392 4.403 ;
     RECT  28.272 4.357 29.88 4.547 ;
     RECT  6.864 4.261 11.688 4.595 ;
     RECT  24 2.867 24.312 4.645 ;
     RECT  10.5 4.595 11.688 4.691 ;
     RECT  21.3 4.259 22.2 4.789 ;
     RECT  23.376 4.645 24.312 4.789 ;
     RECT  21.3 4.789 24.312 4.835 ;
     RECT  28.272 4.547 29.712 4.835 ;
     RECT  10.5 4.691 11.4 4.883 ;
     RECT  25.344 3.829 25.368 5.029 ;
     RECT  28.464 4.835 29.712 5.939 ;
     RECT  5.1 4.163 5.412 6.229 ;
     RECT  6.864 4.595 9.096 6.229 ;
     RECT  10.5 4.883 10.812 6.229 ;
     RECT  13.2 4.403 16.212 6.229 ;
     RECT  6.864 6.229 10.812 6.275 ;
     RECT  25.344 5.029 25.416 6.275 ;
     RECT  6.864 6.275 8.664 6.419 ;
     RECT  2.4 4.067 2.712 6.421 ;
     RECT  18.6 2.151 18.912 6.421 ;
     RECT  32.1 3.971 32.412 6.709 ;
     RECT  13.2 6.229 16.344 6.755 ;
     RECT  4.512 6.229 5.412 6.805 ;
     RECT  4.512 6.805 6.216 6.899 ;
     RECT  14.928 6.755 16.344 7.093 ;
     RECT  7.44 6.419 8.664 7.333 ;
     RECT  9.648 6.275 10.812 7.333 ;
     RECT  21.3 4.835 21.612 7.333 ;
     RECT  21.3 7.333 22.008 7.381 ;
     RECT  26.7 3.923 27.012 7.381 ;
     RECT  12.096 5.749 12.12 7.475 ;
     RECT  17.616 6.421 18.912 7.475 ;
     RECT  23.088 4.835 24.312 7.475 ;
     RECT  14.928 7.093 16.392 7.523 ;
     RECT  15.6 7.523 16.392 7.619 ;
     RECT  7.44 7.333 10.812 7.765 ;
     RECT  25.344 6.275 25.368 7.813 ;
     RECT  25.344 7.813 25.608 7.859 ;
     RECT  15.744 7.619 16.392 7.909 ;
     RECT  5.1 6.899 6.216 7.957 ;
     RECT  18.6 7.475 18.912 7.957 ;
     RECT  21.3 7.381 22.104 8.005 ;
     RECT  21.12 8.005 22.104 8.243 ;
     RECT  13.2 6.755 13.848 8.435 ;
     RECT  13.2 8.435 13.512 8.485 ;
     RECT  5.1 7.957 6.264 8.579 ;
     RECT  18.6 7.957 19.416 8.723 ;
     RECT  21.12 8.243 22.008 8.771 ;
     RECT  15.744 7.909 16.776 8.773 ;
     RECT  26.7 7.381 27.768 8.917 ;
     RECT  28.752 5.939 29.712 8.917 ;
     RECT  7.44 7.765 11.4 8.965 ;
     RECT  12.912 8.485 13.512 8.965 ;
     RECT  15.744 8.773 17.208 8.965 ;
     RECT  15.408 8.965 17.208 9.011 ;
     RECT  15.408 9.011 16.392 9.013 ;
     RECT  7.44 8.965 13.512 9.395 ;
     RECT  5.1 8.579 6.072 9.637 ;
     RECT  7.44 9.395 11.976 9.637 ;
     RECT  13.2 9.395 13.512 9.637 ;
     RECT  14.592 9.013 16.392 9.637 ;
     RECT  5.1 9.637 11.976 9.683 ;
     RECT  2.4 6.421 3.336 9.685 ;
     RECT  9.552 9.683 11.976 9.731 ;
     RECT  31.296 6.709 32.412 9.731 ;
     RECT  21.12 8.771 21.612 9.925 ;
     RECT  13.2 9.637 16.392 10.069 ;
     RECT  26.7 8.917 29.712 10.307 ;
     RECT  25.584 7.859 25.608 10.453 ;
     RECT  13.2 10.069 16.488 10.499 ;
     RECT  24 7.475 24.312 10.597 ;
     RECT  25.296 10.453 25.608 10.597 ;
     RECT  13.2 10.499 14.856 10.739 ;
     RECT  24 10.597 25.608 10.837 ;
     RECT  2.4 9.685 3.624 10.883 ;
     RECT  28.368 10.307 29.712 10.883 ;
     RECT  23.904 10.837 25.608 10.979 ;
     RECT  5.1 9.683 8.472 11.365 ;
     RECT  24 10.979 25.608 11.411 ;
     RECT  9.552 9.731 11.4 11.413 ;
     RECT  35.904 11.365 35.928 11.555 ;
     RECT  4.512 11.365 8.472 11.701 ;
     RECT  28.128 11.797 28.152 11.845 ;
     RECT  29.232 10.883 29.712 11.845 ;
     RECT  18.6 8.723 18.912 11.941 ;
     RECT  9.552 11.413 12.12 12.035 ;
     RECT  20.976 9.925 22.248 12.131 ;
     RECT  13.2 10.739 13.512 12.325 ;
     RECT  14.544 10.739 14.856 12.325 ;
     RECT  12.096 12.035 12.12 12.467 ;
     RECT  4.512 11.701 8.52 12.515 ;
     RECT  21.024 12.131 22.248 12.515 ;
     RECT  5.1 12.515 8.52 12.659 ;
     RECT  5.1 12.659 8.328 12.899 ;
     RECT  13.2 12.325 14.856 13.093 ;
     RECT  15.9 10.499 16.488 13.093 ;
     RECT  13.2 13.093 16.488 13.283 ;
     RECT  24 11.411 24.456 13.381 ;
     RECT  25.584 11.411 25.608 13.381 ;
     RECT  13.2 13.283 14.808 13.475 ;
     RECT  28.128 11.845 29.712 13.475 ;
     RECT  24 13.381 25.608 13.667 ;
     RECT  18.6 11.941 19.368 13.669 ;
     RECT  32.1 9.731 32.412 13.669 ;
     RECT  3.888 12.517 3.912 13.715 ;
     RECT  7.104 12.899 8.328 13.715 ;
     RECT  14.784 13.475 14.808 13.715 ;
     RECT  25.584 13.667 25.608 13.763 ;
     RECT  18.6 13.669 19.464 13.859 ;
     RECT  32.1 13.669 33.384 13.859 ;
     RECT  21.024 12.515 21.612 14.149 ;
     RECT  5.1 12.899 6.072 14.197 ;
     RECT  7.104 13.715 8.232 14.197 ;
     RECT  15.9 13.283 16.488 14.291 ;
     RECT  32.1 13.859 32.412 14.389 ;
     RECT  13.2 13.475 13.704 14.437 ;
     RECT  26.7 10.307 27.012 14.437 ;
     RECT  26.448 14.437 27.012 14.485 ;
     RECT  26.448 14.485 27.624 14.725 ;
     RECT  29.088 13.475 29.712 14.725 ;
     RECT  26.448 14.725 29.712 14.821 ;
     RECT  13.2 14.437 14.28 15.349 ;
     RECT  15.9 14.291 16.212 15.349 ;
     RECT  31.968 14.389 32.412 15.395 ;
     RECT  5.1 14.197 8.232 15.685 ;
     RECT  18.6 13.859 18.912 15.829 ;
     RECT  13.2 15.349 16.212 15.875 ;
     RECT  24 13.667 24.456 16.021 ;
     RECT  30.912 14.773 30.936 16.163 ;
     RECT  25.68 14.821 29.712 16.259 ;
     RECT  23.424 16.021 24.456 16.355 ;
     RECT  20.928 14.149 21.612 16.549 ;
     RECT  5.1 15.685 8.904 16.595 ;
     RECT  10.5 12.035 10.812 16.597 ;
     RECT  14.736 15.875 16.212 16.645 ;
     RECT  18.24 15.829 18.912 16.789 ;
     RECT  13.2 15.875 13.656 17.029 ;
     RECT  14.736 16.645 16.344 17.029 ;
     RECT  26.448 16.259 29.712 17.029 ;
     RECT  17.376 16.789 18.912 17.123 ;
     RECT  12.192 15.349 12.216 17.125 ;
     RECT  13.2 17.029 16.344 17.125 ;
     RECT  20.928 16.549 21.72 17.221 ;
     RECT  20.928 17.221 22.056 17.269 ;
     RECT  20.928 17.269 22.152 17.317 ;
     RECT  5.1 16.595 8.232 17.557 ;
     RECT  18.24 17.123 18.912 17.557 ;
     RECT  24 16.355 24.456 17.605 ;
     RECT  12.192 17.125 16.344 17.651 ;
     RECT  12.528 17.651 16.344 17.699 ;
     RECT  26.448 17.029 30.216 17.699 ;
     RECT  10.5 16.597 11.064 17.795 ;
     RECT  14.928 17.699 16.344 17.893 ;
     RECT  14.928 17.893 16.536 18.035 ;
     RECT  26.448 17.699 29.712 18.083 ;
     RECT  32.1 15.395 32.412 18.229 ;
     RECT  12.528 17.699 13.8 18.275 ;
     RECT  18.24 17.557 19.896 18.275 ;
     RECT  32.1 18.229 32.712 18.469 ;
     RECT  2.4 10.883 2.712 18.565 ;
     RECT  4.416 17.557 8.232 18.565 ;
     RECT  26.448 18.083 27.144 18.659 ;
     RECT  12.96 18.275 13.8 18.755 ;
     RECT  20.928 17.317 22.248 18.803 ;
     RECT  18.6 18.275 19.896 18.899 ;
     RECT  28.464 18.083 29.712 18.899 ;
     RECT  14.928 18.035 16.488 18.995 ;
     RECT  2.4 18.565 8.232 19.043 ;
     RECT  20.928 18.803 21.72 19.235 ;
     RECT  5.1 19.043 8.232 19.333 ;
     RECT  9.456 17.605 9.48 19.333 ;
     RECT  31.968 18.469 32.712 19.333 ;
     RECT  23.376 17.605 24.456 19.427 ;
     RECT  5.1 19.333 9.48 20.147 ;
     RECT  12.96 18.755 13.704 20.437 ;
     RECT  31.968 19.333 33.048 20.437 ;
     RECT  9.456 20.147 9.48 20.485 ;
     RECT  10.5 17.795 10.812 20.485 ;
     RECT  20.928 19.235 21.612 20.533 ;
     RECT  24 19.427 24.456 20.533 ;
     RECT  23.136 20.533 24.456 20.581 ;
     RECT  31.968 20.437 33.288 20.627 ;
     RECT  22.752 20.581 24.456 20.629 ;
     RECT  22.752 20.629 25.368 20.675 ;
     RECT  2.4 19.043 3.672 20.773 ;
     RECT  2.4 20.773 4.008 20.819 ;
     RECT  12.864 20.437 13.704 20.867 ;
     RECT  14.928 18.995 16.212 20.869 ;
     RECT  24 20.675 25.368 20.963 ;
     RECT  29.136 18.899 29.712 21.203 ;
     RECT  20.736 20.533 21.612 21.205 ;
     RECT  18.6 18.899 18.912 21.397 ;
     RECT  26.496 18.659 27.144 21.397 ;
     RECT  24 20.963 24.456 21.491 ;
     RECT  9.456 20.485 10.812 21.539 ;
     RECT  18.6 21.397 19.128 21.539 ;
     RECT  31.968 20.627 32.904 21.637 ;
     RECT  17.472 20.581 17.496 21.683 ;
     RECT  31.968 21.637 33.432 21.827 ;
     RECT  3.984 20.819 4.008 21.925 ;
     RECT  5.1 20.147 8.232 21.925 ;
     RECT  3.984 21.925 8.232 21.971 ;
     RECT  4.32 21.971 8.232 22.019 ;
     RECT  10.5 21.539 10.812 22.021 ;
     RECT  22.752 20.675 22.776 22.163 ;
     RECT  24 21.491 24.312 22.165 ;
     RECT  9.456 21.539 9.48 22.211 ;
     RECT  14.928 20.869 16.344 22.213 ;
     RECT  14.928 22.213 16.68 22.259 ;
     RECT  26.352 21.397 27.144 22.307 ;
     RECT  15.9 22.259 16.68 22.355 ;
     RECT  26.352 22.307 27.012 22.597 ;
     RECT  10.5 22.021 11.112 22.741 ;
     RECT  35.904 22.309 35.928 22.883 ;
     RECT  29.232 21.203 29.712 23.077 ;
     RECT  12.864 20.867 13.656 23.125 ;
     RECT  26.016 22.597 27.012 23.125 ;
     RECT  18.6 21.539 19.032 23.269 ;
     RECT  7.584 22.019 8.232 23.317 ;
     RECT  4.32 22.019 6.36 23.365 ;
     RECT  7.584 23.317 8.28 23.365 ;
     RECT  9.264 23.317 9.288 23.365 ;
     RECT  10.368 22.741 11.112 23.365 ;
     RECT  15.9 22.355 16.344 23.365 ;
     RECT  29.04 23.077 29.712 23.459 ;
     RECT  15.9 23.365 17.064 23.845 ;
     RECT  31.968 21.827 32.616 23.891 ;
     RECT  4.32 23.365 8.28 23.939 ;
     RECT  4.992 23.939 8.28 24.131 ;
     RECT  18.6 23.269 19.224 24.229 ;
     RECT  20.688 21.205 21.612 24.229 ;
     RECT  5.1 24.131 8.28 24.275 ;
     RECT  12.24 23.125 13.656 24.371 ;
     RECT  18.6 24.229 21.612 24.469 ;
     RECT  9.264 23.365 11.112 24.611 ;
     RECT  23.52 22.165 24.312 24.709 ;
     RECT  25.728 23.125 27.012 24.709 ;
     RECT  5.1 24.275 8.232 24.899 ;
     RECT  15.072 23.845 17.064 24.901 ;
     RECT  18.432 24.469 21.612 25.043 ;
     RECT  15.072 24.901 17.112 25.139 ;
     RECT  25.344 24.709 27.012 25.139 ;
     RECT  31.968 23.891 32.412 25.141 ;
     RECT  31.968 25.141 32.52 25.283 ;
     RECT  9.312 24.611 9.528 25.331 ;
     RECT  31.968 25.283 32.412 25.477 ;
     RECT  12.192 24.421 12.216 25.525 ;
     RECT  9.504 25.331 9.528 25.571 ;
     RECT  12.144 25.525 12.216 25.669 ;
     RECT  13.2 24.371 13.656 25.669 ;
     RECT  25.728 25.139 27.012 25.669 ;
     RECT  29.28 23.459 29.712 25.669 ;
     RECT  6.624 24.899 8.232 25.763 ;
     RECT  7.8 25.763 8.232 25.811 ;
     RECT  5.1 24.899 5.412 26.101 ;
     RECT  10.5 24.611 11.112 26.149 ;
     RECT  12.144 25.669 13.656 26.149 ;
     RECT  15.072 25.139 17.016 26.149 ;
     RECT  9.648 26.149 11.112 26.243 ;
     RECT  18.432 25.043 19.944 26.293 ;
     RECT  20.928 25.043 21.612 26.293 ;
     RECT  35.904 26.197 35.928 26.387 ;
     RECT  18.432 26.293 21.612 26.435 ;
     RECT  5.1 26.101 5.544 26.629 ;
     RECT  23.328 24.709 24.312 26.773 ;
     RECT  25.728 25.669 27.384 26.773 ;
     RECT  23.328 26.773 27.384 26.869 ;
     RECT  12.144 26.149 17.016 27.059 ;
     RECT  12.144 27.059 16.344 27.107 ;
     RECT  23.328 26.869 27.48 27.155 ;
     RECT  6.624 25.763 6.648 27.205 ;
     RECT  7.8 25.811 8.112 27.205 ;
     RECT  31.44 25.477 32.412 27.395 ;
     RECT  31.488 27.395 32.412 27.397 ;
     RECT  6.624 27.205 8.112 27.589 ;
     RECT  9.648 26.243 10.812 27.635 ;
     RECT  31.488 27.397 32.904 27.923 ;
     RECT  6.624 27.589 8.232 28.451 ;
     RECT  28.512 25.669 29.712 28.451 ;
     RECT  10.5 27.635 10.812 28.453 ;
     RECT  4.704 26.629 5.544 28.501 ;
     RECT  35.28 28.261 35.304 28.547 ;
     RECT  23.328 27.155 27.384 28.691 ;
     RECT  12.144 27.107 16.212 28.693 ;
     RECT  12.144 28.693 16.344 29.123 ;
     RECT  10.5 28.453 11.112 29.171 ;
     RECT  25.68 28.691 27.384 29.219 ;
     RECT  23.328 28.691 24.312 29.221 ;
     RECT  3.936 28.501 5.544 29.267 ;
     RECT  22.944 29.221 24.312 29.267 ;
     RECT  4.992 29.267 5.544 29.507 ;
     RECT  20.928 26.435 21.612 29.653 ;
     RECT  22.944 29.267 22.968 29.653 ;
     RECT  4.992 29.507 5.412 29.699 ;
     RECT  9.312 28.453 9.336 29.747 ;
     RECT  31.488 27.923 32.412 29.797 ;
     RECT  31.344 29.797 32.412 29.941 ;
     RECT  0.288 24.373 0.312 30.469 ;
     RECT  12.144 29.123 16.212 30.469 ;
     RECT  0.192 30.469 0.312 30.515 ;
     RECT  20.928 29.653 22.968 30.563 ;
     RECT  6.624 28.451 8.112 30.709 ;
     RECT  18.432 26.435 19.848 30.757 ;
     RECT  20.928 30.563 21.612 30.757 ;
     RECT  3.936 29.267 3.96 30.851 ;
     RECT  24 29.267 24.312 30.949 ;
     RECT  12.144 30.469 16.344 31.139 ;
     RECT  6.624 30.709 8.28 31.427 ;
     RECT  18.432 30.757 21.612 31.715 ;
     RECT  5.1 29.699 5.412 31.861 ;
     RECT  6.624 31.427 8.112 31.861 ;
     RECT  14.832 31.139 16.344 31.861 ;
     RECT  25.68 29.219 27.012 31.861 ;
     RECT  10.5 29.171 11.064 31.907 ;
     RECT  2.4 20.819 2.712 31.909 ;
     RECT  3.696 31.861 3.72 31.909 ;
     RECT  5.1 31.861 8.112 31.955 ;
     RECT  25.68 31.861 27.864 31.955 ;
     RECT  30.72 29.941 32.412 31.955 ;
     RECT  18.432 31.715 19.848 32.051 ;
     RECT  20.928 31.715 21.612 32.341 ;
     RECT  22.944 30.563 22.968 32.341 ;
     RECT  24 30.949 24.408 32.437 ;
     RECT  25.68 31.955 25.704 32.437 ;
     RECT  14.832 31.861 17.16 32.723 ;
     RECT  29.4 28.451 29.712 32.725 ;
     RECT  2.4 31.909 3.72 32.771 ;
     RECT  7.056 31.955 8.112 33.013 ;
     RECT  31.92 31.955 32.412 33.013 ;
     RECT  24 32.437 25.704 33.059 ;
     RECT  29.088 32.725 29.712 33.059 ;
     RECT  12.144 31.139 13.512 33.061 ;
     RECT  14.832 32.723 16.212 33.061 ;
     RECT  9.36 30.181 9.384 33.155 ;
     RECT  26.7 31.955 27.864 33.443 ;
     RECT  29.4 33.059 29.712 33.541 ;
     RECT  5.1 31.955 5.736 33.683 ;
     RECT  31.776 33.013 32.412 33.683 ;
     RECT  12.144 33.061 16.212 33.827 ;
     RECT  6.864 33.013 8.112 33.925 ;
     RECT  9.312 33.397 9.336 33.925 ;
     RECT  14.832 33.827 16.212 33.973 ;
     RECT  14.832 33.973 16.344 34.163 ;
     RECT  6.864 33.925 9.336 34.259 ;
     RECT  20.928 32.341 22.968 34.691 ;
     RECT  32.1 33.683 32.412 34.741 ;
     RECT  10.5 31.907 10.968 34.885 ;
     RECT  12.144 33.827 13.512 34.885 ;
     RECT  29.4 33.541 30.312 35.173 ;
     RECT  6.864 34.259 8.952 35.219 ;
     RECT  31.968 34.741 32.412 35.219 ;
     RECT  15.072 34.163 16.344 35.221 ;
     RECT  5.1 33.683 5.412 35.317 ;
     RECT  6.864 35.219 8.904 35.317 ;
     RECT  29.28 35.173 30.312 35.461 ;
     RECT  14.544 35.221 16.344 35.653 ;
     RECT  28.176 35.365 28.2 35.701 ;
     RECT  29.184 35.461 30.312 35.701 ;
     RECT  28.176 35.701 30.312 35.747 ;
     RECT  14.544 35.653 17.16 35.843 ;
     RECT  14.544 35.843 16.584 36.035 ;
     RECT  5.1 35.317 8.904 36.227 ;
     RECT  20.928 34.691 22.44 36.277 ;
     RECT  25.68 33.059 25.704 36.277 ;
     RECT  24 33.059 24.312 36.373 ;
     RECT  20.928 36.277 22.632 36.469 ;
     RECT  14.64 36.035 16.584 36.515 ;
     RECT  20.832 36.469 22.632 36.517 ;
     RECT  20.832 36.517 22.968 36.563 ;
     RECT  28.176 35.747 30.264 36.659 ;
     RECT  5.1 36.227 6.264 36.755 ;
     RECT  7.44 36.227 8.904 36.803 ;
     RECT  25.536 36.277 25.704 37.091 ;
     RECT  5.1 36.755 5.412 37.093 ;
     RECT  25.536 37.091 25.56 37.139 ;
     RECT  10.5 34.885 13.512 37.187 ;
     RECT  15.072 36.515 16.584 37.237 ;
     RECT  7.68 36.803 8.856 37.379 ;
     RECT  20.832 36.563 21.612 37.427 ;
     RECT  24 36.373 24.408 37.477 ;
     RECT  32.1 35.219 32.412 37.573 ;
     RECT  24 37.477 25.368 37.715 ;
     RECT  31.872 37.573 32.412 37.765 ;
     RECT  31.872 37.765 33.336 37.955 ;
     RECT  25.296 37.715 25.368 38.243 ;
     RECT  4.512 37.093 5.412 38.387 ;
     RECT  10.5 37.187 12.216 38.437 ;
     RECT  13.2 37.187 13.512 38.437 ;
     RECT  15.072 37.237 17.064 38.533 ;
     RECT  35.904 38.437 35.928 38.579 ;
     RECT  2.4 32.771 3.096 38.677 ;
     RECT  28.512 36.659 30.264 38.867 ;
     RECT  31.872 37.955 32.808 38.963 ;
     RECT  14.976 38.533 17.064 39.059 ;
     RECT  25.344 38.243 25.368 39.109 ;
     RECT  26.7 33.443 27.012 39.109 ;
     RECT  29.088 38.867 30.264 39.251 ;
     RECT  7.8 37.379 8.856 39.347 ;
     RECT  7.8 39.347 8.712 39.395 ;
     RECT  10.5 38.437 13.512 39.395 ;
     RECT  18.6 32.051 19.848 39.445 ;
     RECT  24 37.715 24.312 39.445 ;
     RECT  25.344 39.109 27.012 39.445 ;
     RECT  7.8 39.395 8.568 39.877 ;
     RECT  24 39.445 27.012 40.019 ;
     RECT  31.968 38.963 32.808 40.019 ;
     RECT  24 40.019 25.368 40.259 ;
     RECT  29.4 39.251 30.264 40.499 ;
     RECT  2.4 38.677 3.384 40.595 ;
     RECT  33.888 40.501 33.912 40.691 ;
     RECT  31.968 40.019 32.412 40.789 ;
     RECT  28.176 40.789 28.2 40.981 ;
     RECT  29.4 40.499 29.88 40.981 ;
     RECT  17.904 39.445 19.848 41.027 ;
     RECT  31.92 40.789 32.412 41.413 ;
     RECT  28.176 40.981 29.88 41.507 ;
     RECT  28.176 41.507 29.712 41.555 ;
     RECT  31.92 41.413 33.192 41.555 ;
     RECT  22.608 36.563 22.968 41.605 ;
     RECT  24 40.259 24.312 41.605 ;
     RECT  13.2 39.395 13.512 41.653 ;
     RECT  31.92 41.555 33.096 41.699 ;
     RECT  22.608 41.605 24.312 41.795 ;
     RECT  30.816 41.605 30.84 41.987 ;
     RECT  21.3 37.427 21.612 42.037 ;
     RECT  22.608 41.795 22.968 42.037 ;
     RECT  14.976 39.059 16.44 42.227 ;
     RECT  15.12 42.227 16.44 42.275 ;
     RECT  10.5 39.395 11.832 42.277 ;
     RECT  10.5 42.277 12.024 42.565 ;
     RECT  13.2 41.653 13.896 42.565 ;
     RECT  7.056 39.877 8.568 42.611 ;
     RECT  2.4 40.595 3.096 42.709 ;
     RECT  7.056 42.611 8.112 42.709 ;
     RECT  15.264 42.275 16.44 42.709 ;
     RECT  26.7 40.019 27.012 42.709 ;
     RECT  21.3 42.037 22.968 42.755 ;
     RECT  32.1 41.699 33.096 43.045 ;
     RECT  29.088 41.555 29.712 43.141 ;
     RECT  2.4 42.709 3.48 43.189 ;
     RECT  21.3 42.755 22.536 43.379 ;
     RECT  15.264 42.709 16.968 43.571 ;
     RECT  31.92 43.045 33.096 43.571 ;
     RECT  26.496 42.709 27.012 43.619 ;
     RECT  6.432 42.709 8.112 43.955 ;
     RECT  9.12 43.381 9.144 43.955 ;
     RECT  31.92 43.571 32.616 43.955 ;
     RECT  2.4 43.189 4.008 44.051 ;
     RECT  32.1 43.955 32.616 44.051 ;
     RECT  6.768 43.955 8.112 44.099 ;
     RECT  15.264 43.571 16.344 44.101 ;
     RECT  10.224 42.565 13.896 44.149 ;
     RECT  6.768 44.099 6.792 44.195 ;
     RECT  26.7 43.619 27.012 44.197 ;
     RECT  28.608 43.141 29.712 44.197 ;
     RECT  21.3 43.379 21.72 44.243 ;
     RECT  2.4 44.051 3.096 44.339 ;
     RECT  30.864 43.861 30.888 44.339 ;
     RECT  9.792 44.149 13.896 44.341 ;
     RECT  21.3 44.243 21.612 44.725 ;
     RECT  21.072 44.725 21.612 44.915 ;
     RECT  15.216 44.101 16.344 44.963 ;
     RECT  15.264 44.963 16.344 44.965 ;
     RECT  9.792 44.341 14.088 45.059 ;
     RECT  24 41.795 24.312 45.157 ;
     RECT  25.344 40.259 25.368 45.157 ;
     RECT  24 45.157 25.368 45.203 ;
     RECT  7.8 44.099 8.112 45.301 ;
     RECT  26.7 44.197 29.712 45.491 ;
     RECT  28.704 45.491 29.712 45.731 ;
     RECT  18.6 41.027 19.848 45.877 ;
     RECT  21.3 44.915 21.612 45.877 ;
     RECT  28.8 45.731 29.712 45.925 ;
     RECT  9.792 45.059 13.512 45.973 ;
     RECT  32.1 44.051 32.412 45.973 ;
     RECT  7.8 45.301 8.472 46.069 ;
     RECT  31.776 45.973 32.412 46.115 ;
     RECT  6.864 46.069 8.472 46.355 ;
     RECT  5.1 38.387 5.412 46.405 ;
     RECT  17.52 45.877 17.544 46.691 ;
     RECT  4.992 46.405 5.412 46.739 ;
     RECT  9.696 45.973 13.512 46.787 ;
     RECT  15.264 44.965 16.44 46.787 ;
     RECT  9.696 46.787 11.688 46.835 ;
     RECT  12.768 46.787 13.512 47.125 ;
     RECT  12.768 47.125 13.656 47.315 ;
     RECT  18.6 45.877 21.612 47.315 ;
     RECT  28.8 45.925 30.552 47.363 ;
     RECT  21.12 47.315 21.612 47.365 ;
     RECT  29.4 47.363 30.552 47.795 ;
     RECT  21.12 47.365 21.912 47.843 ;
     RECT  5.1 46.739 5.412 47.845 ;
     RECT  15.264 46.787 16.212 47.845 ;
     RECT  13.2 47.315 13.656 47.939 ;
     RECT  10.5 46.835 11.688 48.421 ;
     RECT  4.992 47.845 5.412 48.707 ;
     RECT  9.984 48.421 11.688 48.707 ;
     RECT  15.072 47.845 16.212 48.755 ;
     RECT  13.2 47.939 13.512 48.757 ;
     RECT  24 45.203 25.128 48.757 ;
     RECT  29.4 47.795 29.712 48.757 ;
     RECT  32.1 46.115 32.412 48.757 ;
     RECT  18.6 47.315 19.848 48.803 ;
     RECT  21.3 47.843 21.912 48.901 ;
     RECT  0.192 30.515 0.216 48.947 ;
     RECT  32.1 48.757 32.52 48.947 ;
     RECT  6.864 46.355 8.112 48.995 ;
     RECT  13.104 48.757 13.512 49.043 ;
     RECT  21.072 48.901 21.912 49.043 ;
     RECT  24 48.757 25.176 49.043 ;
     RECT  28.992 48.757 29.712 49.043 ;
     RECT  9.984 48.707 10.812 49.379 ;
     RECT  21.3 49.043 21.912 49.523 ;
     RECT  2.4 44.339 2.712 49.689 ;
     RECT  5.1 48.707 5.412 49.689 ;
     RECT  7.8 48.995 8.112 49.689 ;
     RECT  10.5 49.379 10.812 49.689 ;
     RECT  13.2 49.043 13.512 49.689 ;
     RECT  15.408 48.755 16.212 49.689 ;
     RECT  18.6 48.803 18.912 49.689 ;
     RECT  21.3 49.523 21.612 49.689 ;
     RECT  24 49.043 24.312 49.689 ;
     RECT  26.7 45.491 27.012 49.689 ;
     RECT  29.4 49.043 29.712 49.689 ;
     RECT  32.1 48.947 32.412 49.689 ;
     RECT  2.4 49.689 2.52 49.703 ;
     RECT  5.1 49.689 5.22 49.703 ;
     RECT  7.8 49.689 7.92 49.703 ;
     RECT  10.5 49.689 10.62 49.703 ;
     RECT  13.2 49.689 13.32 49.703 ;
     RECT  15.408 49.689 16.02 49.703 ;
     RECT  18.6 49.689 18.72 49.703 ;
     RECT  21.3 49.689 21.42 49.703 ;
     RECT  24 49.689 24.12 49.703 ;
     RECT  26.7 49.689 26.82 49.703 ;
     RECT  29.4 49.689 29.52 49.703 ;
     RECT  32.1 49.689 32.22 49.703 ;
     RECT  15.408 49.703 15.432 51.685 ;
     RECT  15.408 51.685 15.624 51.731 ;
     RECT  15.6 51.731 15.624 51.792 ;
  END
END dsfd_dvland_276
END LIBRARY
